VERSION 5.8 ;
BUSBITCHARS "[]" ;
DIVIDERCHAR "/" ;
UNITS
    DATABASE MICRONS 1000 ;
END UNITS

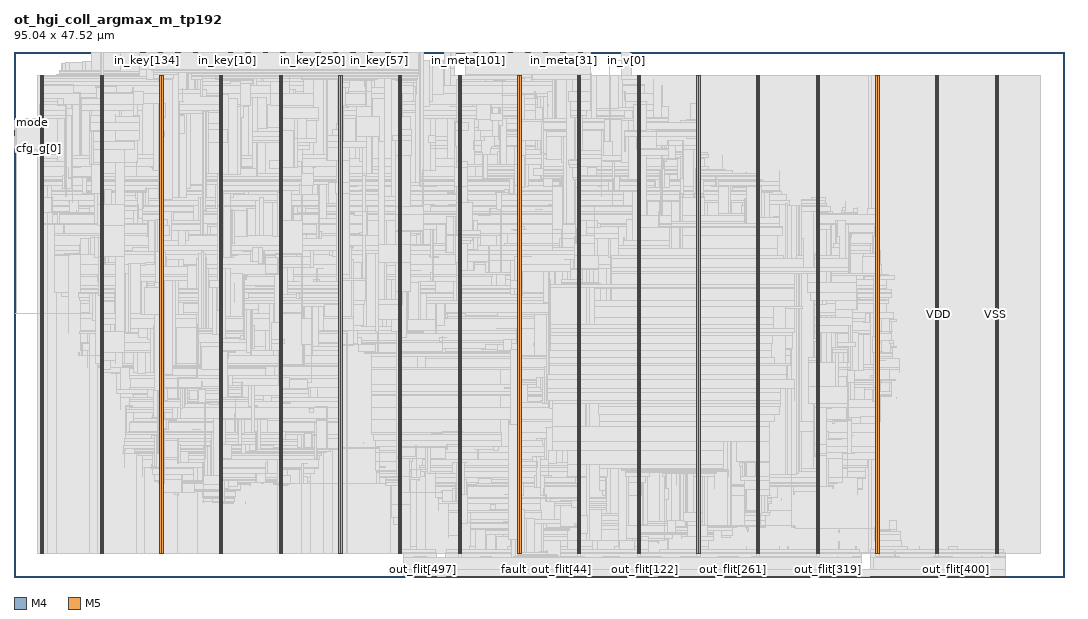
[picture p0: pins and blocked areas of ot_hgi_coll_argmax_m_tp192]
MACRO ot_hgi_coll_argmax_m_tp192
  FOREIGN ot_hgi_coll_argmax_m_tp192 0 0 ;
  CLASS BLOCK ;
  SIZE 95.04 BY 47.52 ;
  PIN cfg_g[0]
    DIRECTION INPUT ;
    USE SIGNAL ;
    PORT
      LAYER M4 ;
        RECT  0 38.736 0.084 38.76 ;
    END
  END cfg_g[0]
  PIN cfg_g[1]
    DIRECTION INPUT ;
    USE SIGNAL ;
    PORT
      LAYER M4 ;
        RECT  0 38.832 0.084 38.856 ;
    END
  END cfg_g[1]
  PIN cfg_g[2]
    DIRECTION INPUT ;
    USE SIGNAL ;
    PORT
      LAYER M4 ;
        RECT  0 38.928 0.084 38.952 ;
    END
  END cfg_g[2]
  PIN cfg_g[3]
    DIRECTION INPUT ;
    USE SIGNAL ;
    PORT
      LAYER M4 ;
        RECT  0 39.024 0.084 39.048 ;
    END
  END cfg_g[3]
  PIN cfg_g[4]
    DIRECTION INPUT ;
    USE SIGNAL ;
    PORT
      LAYER M4 ;
        RECT  0 39.12 0.084 39.144 ;
    END
  END cfg_g[4]
  PIN cfg_g[5]
    DIRECTION INPUT ;
    USE SIGNAL ;
    PORT
      LAYER M4 ;
        RECT  0 39.216 0.084 39.24 ;
    END
  END cfg_g[5]
  PIN cfg_g[6]
    DIRECTION INPUT ;
    USE SIGNAL ;
    PORT
      LAYER M4 ;
        RECT  0 39.312 0.084 39.336 ;
    END
  END cfg_g[6]
  PIN cfg_g[7]
    DIRECTION INPUT ;
    USE SIGNAL ;
    PORT
      LAYER M4 ;
        RECT  0 39.408 0.084 39.432 ;
    END
  END cfg_g[7]
  PIN cfg_gbase[0]
    DIRECTION INPUT ;
    USE SIGNAL ;
    PORT
      LAYER M4 ;
        RECT  0 39.504 0.084 39.528 ;
    END
  END cfg_gbase[0]
  PIN cfg_gbase[1]
    DIRECTION INPUT ;
    USE SIGNAL ;
    PORT
      LAYER M4 ;
        RECT  0 39.6 0.084 39.624 ;
    END
  END cfg_gbase[1]
  PIN cfg_gbase[2]
    DIRECTION INPUT ;
    USE SIGNAL ;
    PORT
      LAYER M4 ;
        RECT  0 39.696 0.084 39.72 ;
    END
  END cfg_gbase[2]
  PIN cfg_gbase[3]
    DIRECTION INPUT ;
    USE SIGNAL ;
    PORT
      LAYER M4 ;
        RECT  0 39.792 0.084 39.816 ;
    END
  END cfg_gbase[3]
  PIN cfg_gbase[4]
    DIRECTION INPUT ;
    USE SIGNAL ;
    PORT
      LAYER M4 ;
        RECT  0 39.888 0.084 39.912 ;
    END
  END cfg_gbase[4]
  PIN cfg_gbase[5]
    DIRECTION INPUT ;
    USE SIGNAL ;
    PORT
      LAYER M4 ;
        RECT  0 39.984 0.084 40.008 ;
    END
  END cfg_gbase[5]
  PIN cfg_gbase[6]
    DIRECTION INPUT ;
    USE SIGNAL ;
    PORT
      LAYER M4 ;
        RECT  0 40.08 0.084 40.104 ;
    END
  END cfg_gbase[6]
  PIN cfg_gbase[7]
    DIRECTION INPUT ;
    USE SIGNAL ;
    PORT
      LAYER M4 ;
        RECT  0 40.176 0.084 40.2 ;
    END
  END cfg_gbase[7]
  PIN cfg_rank[0]
    DIRECTION INPUT ;
    USE SIGNAL ;
    PORT
      LAYER M4 ;
        RECT  0 40.272 0.084 40.296 ;
    END
  END cfg_rank[0]
  PIN cfg_rank[1]
    DIRECTION INPUT ;
    USE SIGNAL ;
    PORT
      LAYER M4 ;
        RECT  0 40.368 0.084 40.392 ;
    END
  END cfg_rank[1]
  PIN cfg_rank[2]
    DIRECTION INPUT ;
    USE SIGNAL ;
    PORT
      LAYER M4 ;
        RECT  0 40.464 0.084 40.488 ;
    END
  END cfg_rank[2]
  PIN cfg_rank[3]
    DIRECTION INPUT ;
    USE SIGNAL ;
    PORT
      LAYER M4 ;
        RECT  0 40.56 0.084 40.584 ;
    END
  END cfg_rank[3]
  PIN cfg_rank[4]
    DIRECTION INPUT ;
    USE SIGNAL ;
    PORT
      LAYER M4 ;
        RECT  0 40.656 0.084 40.68 ;
    END
  END cfg_rank[4]
  PIN cfg_rank[5]
    DIRECTION INPUT ;
    USE SIGNAL ;
    PORT
      LAYER M4 ;
        RECT  0 40.752 0.084 40.776 ;
    END
  END cfg_rank[5]
  PIN cfg_rank[6]
    DIRECTION INPUT ;
    USE SIGNAL ;
    PORT
      LAYER M4 ;
        RECT  0 40.848 0.084 40.872 ;
    END
  END cfg_rank[6]
  PIN cfg_rank[7]
    DIRECTION INPUT ;
    USE SIGNAL ;
    PORT
      LAYER M4 ;
        RECT  0 40.944 0.084 40.968 ;
    END
  END cfg_rank[7]
  PIN clk
    DIRECTION INPUT ;
    USE SIGNAL ;
    PORT
      LAYER M4 ;
        RECT  0 41.04 0.084 41.064 ;
    END
  END clk
  PIN fault
    DIRECTION OUTPUT ;
    USE SIGNAL ;
    PORT
      LAYER M5 ;
        RECT  45.264 0 45.288 0.084 ;
    END
  END fault
  PIN flush_slot
    DIRECTION INPUT ;
    USE SIGNAL ;
    PORT
      LAYER M5 ;
        RECT  18.288 47.436 18.312 47.52 ;
    END
  END flush_slot
  PIN in_key[0]
    DIRECTION INPUT ;
    USE SIGNAL ;
    PORT
      LAYER M5 ;
        RECT  18.384 47.436 18.408 47.52 ;
    END
  END in_key[0]
  PIN in_key[100]
    DIRECTION INPUT ;
    USE SIGNAL ;
    PORT
      LAYER M5 ;
        RECT  34.128 47.436 34.152 47.52 ;
    END
  END in_key[100]
  PIN in_key[101]
    DIRECTION INPUT ;
    USE SIGNAL ;
    PORT
      LAYER M5 ;
        RECT  34.224 47.436 34.248 47.52 ;
    END
  END in_key[101]
  PIN in_key[102]
    DIRECTION INPUT ;
    USE SIGNAL ;
    PORT
      LAYER M5 ;
        RECT  34.32 47.436 34.344 47.52 ;
    END
  END in_key[102]
  PIN in_key[103]
    DIRECTION INPUT ;
    USE SIGNAL ;
    PORT
      LAYER M5 ;
        RECT  34.416 47.436 34.44 47.52 ;
    END
  END in_key[103]
  PIN in_key[104]
    DIRECTION INPUT ;
    USE SIGNAL ;
    PORT
      LAYER M5 ;
        RECT  34.512 47.436 34.536 47.52 ;
    END
  END in_key[104]
  PIN in_key[105]
    DIRECTION INPUT ;
    USE SIGNAL ;
    PORT
      LAYER M5 ;
        RECT  34.608 47.436 34.632 47.52 ;
    END
  END in_key[105]
  PIN in_key[106]
    DIRECTION INPUT ;
    USE SIGNAL ;
    PORT
      LAYER M5 ;
        RECT  34.704 47.436 34.728 47.52 ;
    END
  END in_key[106]
  PIN in_key[107]
    DIRECTION INPUT ;
    USE SIGNAL ;
    PORT
      LAYER M5 ;
        RECT  34.8 47.436 34.824 47.52 ;
    END
  END in_key[107]
  PIN in_key[108]
    DIRECTION INPUT ;
    USE SIGNAL ;
    PORT
      LAYER M5 ;
        RECT  34.896 47.436 34.92 47.52 ;
    END
  END in_key[108]
  PIN in_key[109]
    DIRECTION INPUT ;
    USE SIGNAL ;
    PORT
      LAYER M5 ;
        RECT  34.992 47.436 35.016 47.52 ;
    END
  END in_key[109]
  PIN in_key[10]
    DIRECTION INPUT ;
    USE SIGNAL ;
    PORT
      LAYER M5 ;
        RECT  19.344 47.436 19.368 47.52 ;
    END
  END in_key[10]
  PIN in_key[110]
    DIRECTION INPUT ;
    USE SIGNAL ;
    PORT
      LAYER M5 ;
        RECT  35.088 47.436 35.112 47.52 ;
    END
  END in_key[110]
  PIN in_key[111]
    DIRECTION INPUT ;
    USE SIGNAL ;
    PORT
      LAYER M5 ;
        RECT  35.184 47.436 35.208 47.52 ;
    END
  END in_key[111]
  PIN in_key[112]
    DIRECTION INPUT ;
    USE SIGNAL ;
    PORT
      LAYER M5 ;
        RECT  35.28 47.436 35.304 47.52 ;
    END
  END in_key[112]
  PIN in_key[113]
    DIRECTION INPUT ;
    USE SIGNAL ;
    PORT
      LAYER M5 ;
        RECT  35.376 47.436 35.4 47.52 ;
    END
  END in_key[113]
  PIN in_key[114]
    DIRECTION INPUT ;
    USE SIGNAL ;
    PORT
      LAYER M5 ;
        RECT  35.472 47.436 35.496 47.52 ;
    END
  END in_key[114]
  PIN in_key[115]
    DIRECTION INPUT ;
    USE SIGNAL ;
    PORT
      LAYER M5 ;
        RECT  35.568 47.436 35.592 47.52 ;
    END
  END in_key[115]
  PIN in_key[116]
    DIRECTION INPUT ;
    USE SIGNAL ;
    PORT
      LAYER M5 ;
        RECT  35.664 47.436 35.688 47.52 ;
    END
  END in_key[116]
  PIN in_key[117]
    DIRECTION INPUT ;
    USE SIGNAL ;
    PORT
      LAYER M5 ;
        RECT  35.76 47.436 35.784 47.52 ;
    END
  END in_key[117]
  PIN in_key[118]
    DIRECTION INPUT ;
    USE SIGNAL ;
    PORT
      LAYER M5 ;
        RECT  35.856 47.436 35.88 47.52 ;
    END
  END in_key[118]
  PIN in_key[119]
    DIRECTION INPUT ;
    USE SIGNAL ;
    PORT
      LAYER M5 ;
        RECT  35.952 47.436 35.976 47.52 ;
    END
  END in_key[119]
  PIN in_key[11]
    DIRECTION INPUT ;
    USE SIGNAL ;
    PORT
      LAYER M5 ;
        RECT  19.44 47.436 19.464 47.52 ;
    END
  END in_key[11]
  PIN in_key[120]
    DIRECTION INPUT ;
    USE SIGNAL ;
    PORT
      LAYER M5 ;
        RECT  36.048 47.436 36.072 47.52 ;
    END
  END in_key[120]
  PIN in_key[121]
    DIRECTION INPUT ;
    USE SIGNAL ;
    PORT
      LAYER M5 ;
        RECT  36.144 47.436 36.168 47.52 ;
    END
  END in_key[121]
  PIN in_key[122]
    DIRECTION INPUT ;
    USE SIGNAL ;
    PORT
      LAYER M5 ;
        RECT  36.24 47.436 36.264 47.52 ;
    END
  END in_key[122]
  PIN in_key[123]
    DIRECTION INPUT ;
    USE SIGNAL ;
    PORT
      LAYER M5 ;
        RECT  36.336 47.436 36.36 47.52 ;
    END
  END in_key[123]
  PIN in_key[124]
    DIRECTION INPUT ;
    USE SIGNAL ;
    PORT
      LAYER M5 ;
        RECT  36.432 47.436 36.456 47.52 ;
    END
  END in_key[124]
  PIN in_key[125]
    DIRECTION INPUT ;
    USE SIGNAL ;
    PORT
      LAYER M5 ;
        RECT  36.528 47.436 36.552 47.52 ;
    END
  END in_key[125]
  PIN in_key[126]
    DIRECTION INPUT ;
    USE SIGNAL ;
    PORT
      LAYER M5 ;
        RECT  36.624 47.436 36.648 47.52 ;
    END
  END in_key[126]
  PIN in_key[127]
    DIRECTION INPUT ;
    USE SIGNAL ;
    PORT
      LAYER M5 ;
        RECT  11.376 47.436 11.4 47.52 ;
    END
  END in_key[127]
  PIN in_key[128]
    DIRECTION INPUT ;
    USE SIGNAL ;
    PORT
      LAYER M5 ;
        RECT  11.472 47.436 11.496 47.52 ;
    END
  END in_key[128]
  PIN in_key[129]
    DIRECTION INPUT ;
    USE SIGNAL ;
    PORT
      LAYER M5 ;
        RECT  11.568 47.436 11.592 47.52 ;
    END
  END in_key[129]
  PIN in_key[12]
    DIRECTION INPUT ;
    USE SIGNAL ;
    PORT
      LAYER M5 ;
        RECT  19.536 47.436 19.56 47.52 ;
    END
  END in_key[12]
  PIN in_key[130]
    DIRECTION INPUT ;
    USE SIGNAL ;
    PORT
      LAYER M5 ;
        RECT  11.664 47.436 11.688 47.52 ;
    END
  END in_key[130]
  PIN in_key[131]
    DIRECTION INPUT ;
    USE SIGNAL ;
    PORT
      LAYER M5 ;
        RECT  11.76 47.436 11.784 47.52 ;
    END
  END in_key[131]
  PIN in_key[132]
    DIRECTION INPUT ;
    USE SIGNAL ;
    PORT
      LAYER M5 ;
        RECT  11.856 47.436 11.88 47.52 ;
    END
  END in_key[132]
  PIN in_key[133]
    DIRECTION INPUT ;
    USE SIGNAL ;
    PORT
      LAYER M5 ;
        RECT  11.952 47.436 11.976 47.52 ;
    END
  END in_key[133]
  PIN in_key[134]
    DIRECTION INPUT ;
    USE SIGNAL ;
    PORT
      LAYER M5 ;
        RECT  12.048 47.436 12.072 47.52 ;
    END
  END in_key[134]
  PIN in_key[135]
    DIRECTION INPUT ;
    USE SIGNAL ;
    PORT
      LAYER M5 ;
        RECT  12.144 47.436 12.168 47.52 ;
    END
  END in_key[135]
  PIN in_key[136]
    DIRECTION INPUT ;
    USE SIGNAL ;
    PORT
      LAYER M5 ;
        RECT  12.24 47.436 12.264 47.52 ;
    END
  END in_key[136]
  PIN in_key[137]
    DIRECTION INPUT ;
    USE SIGNAL ;
    PORT
      LAYER M5 ;
        RECT  12.336 47.436 12.36 47.52 ;
    END
  END in_key[137]
  PIN in_key[138]
    DIRECTION INPUT ;
    USE SIGNAL ;
    PORT
      LAYER M5 ;
        RECT  12.432 47.436 12.456 47.52 ;
    END
  END in_key[138]
  PIN in_key[139]
    DIRECTION INPUT ;
    USE SIGNAL ;
    PORT
      LAYER M5 ;
        RECT  12.528 47.436 12.552 47.52 ;
    END
  END in_key[139]
  PIN in_key[13]
    DIRECTION INPUT ;
    USE SIGNAL ;
    PORT
      LAYER M5 ;
        RECT  19.632 47.436 19.656 47.52 ;
    END
  END in_key[13]
  PIN in_key[140]
    DIRECTION INPUT ;
    USE SIGNAL ;
    PORT
      LAYER M5 ;
        RECT  12.624 47.436 12.648 47.52 ;
    END
  END in_key[140]
  PIN in_key[141]
    DIRECTION INPUT ;
    USE SIGNAL ;
    PORT
      LAYER M5 ;
        RECT  12.72 47.436 12.744 47.52 ;
    END
  END in_key[141]
  PIN in_key[142]
    DIRECTION INPUT ;
    USE SIGNAL ;
    PORT
      LAYER M5 ;
        RECT  12.816 47.436 12.84 47.52 ;
    END
  END in_key[142]
  PIN in_key[143]
    DIRECTION INPUT ;
    USE SIGNAL ;
    PORT
      LAYER M5 ;
        RECT  12.912 47.436 12.936 47.52 ;
    END
  END in_key[143]
  PIN in_key[144]
    DIRECTION INPUT ;
    USE SIGNAL ;
    PORT
      LAYER M5 ;
        RECT  13.008 47.436 13.032 47.52 ;
    END
  END in_key[144]
  PIN in_key[145]
    DIRECTION INPUT ;
    USE SIGNAL ;
    PORT
      LAYER M5 ;
        RECT  13.104 47.436 13.128 47.52 ;
    END
  END in_key[145]
  PIN in_key[146]
    DIRECTION INPUT ;
    USE SIGNAL ;
    PORT
      LAYER M5 ;
        RECT  13.2 47.436 13.224 47.52 ;
    END
  END in_key[146]
  PIN in_key[147]
    DIRECTION INPUT ;
    USE SIGNAL ;
    PORT
      LAYER M5 ;
        RECT  13.296 47.436 13.32 47.52 ;
    END
  END in_key[147]
  PIN in_key[148]
    DIRECTION INPUT ;
    USE SIGNAL ;
    PORT
      LAYER M5 ;
        RECT  13.392 47.436 13.416 47.52 ;
    END
  END in_key[148]
  PIN in_key[149]
    DIRECTION INPUT ;
    USE SIGNAL ;
    PORT
      LAYER M5 ;
        RECT  13.488 47.436 13.512 47.52 ;
    END
  END in_key[149]
  PIN in_key[14]
    DIRECTION INPUT ;
    USE SIGNAL ;
    PORT
      LAYER M5 ;
        RECT  19.728 47.436 19.752 47.52 ;
    END
  END in_key[14]
  PIN in_key[150]
    DIRECTION INPUT ;
    USE SIGNAL ;
    PORT
      LAYER M5 ;
        RECT  13.584 47.436 13.608 47.52 ;
    END
  END in_key[150]
  PIN in_key[151]
    DIRECTION INPUT ;
    USE SIGNAL ;
    PORT
      LAYER M5 ;
        RECT  13.68 47.436 13.704 47.52 ;
    END
  END in_key[151]
  PIN in_key[152]
    DIRECTION INPUT ;
    USE SIGNAL ;
    PORT
      LAYER M5 ;
        RECT  13.776 47.436 13.8 47.52 ;
    END
  END in_key[152]
  PIN in_key[153]
    DIRECTION INPUT ;
    USE SIGNAL ;
    PORT
      LAYER M5 ;
        RECT  13.872 47.436 13.896 47.52 ;
    END
  END in_key[153]
  PIN in_key[154]
    DIRECTION INPUT ;
    USE SIGNAL ;
    PORT
      LAYER M5 ;
        RECT  13.968 47.436 13.992 47.52 ;
    END
  END in_key[154]
  PIN in_key[155]
    DIRECTION INPUT ;
    USE SIGNAL ;
    PORT
      LAYER M5 ;
        RECT  14.064 47.436 14.088 47.52 ;
    END
  END in_key[155]
  PIN in_key[156]
    DIRECTION INPUT ;
    USE SIGNAL ;
    PORT
      LAYER M5 ;
        RECT  14.16 47.436 14.184 47.52 ;
    END
  END in_key[156]
  PIN in_key[157]
    DIRECTION INPUT ;
    USE SIGNAL ;
    PORT
      LAYER M5 ;
        RECT  14.256 47.436 14.28 47.52 ;
    END
  END in_key[157]
  PIN in_key[158]
    DIRECTION INPUT ;
    USE SIGNAL ;
    PORT
      LAYER M5 ;
        RECT  14.352 47.436 14.376 47.52 ;
    END
  END in_key[158]
  PIN in_key[159]
    DIRECTION INPUT ;
    USE SIGNAL ;
    PORT
      LAYER M5 ;
        RECT  27.504 47.436 27.528 47.52 ;
    END
  END in_key[159]
  PIN in_key[15]
    DIRECTION INPUT ;
    USE SIGNAL ;
    PORT
      LAYER M5 ;
        RECT  19.824 47.436 19.848 47.52 ;
    END
  END in_key[15]
  PIN in_key[160]
    DIRECTION INPUT ;
    USE SIGNAL ;
    PORT
      LAYER M5 ;
        RECT  27.6 47.436 27.624 47.52 ;
    END
  END in_key[160]
  PIN in_key[161]
    DIRECTION INPUT ;
    USE SIGNAL ;
    PORT
      LAYER M5 ;
        RECT  27.696 47.436 27.72 47.52 ;
    END
  END in_key[161]
  PIN in_key[162]
    DIRECTION INPUT ;
    USE SIGNAL ;
    PORT
      LAYER M5 ;
        RECT  27.792 47.436 27.816 47.52 ;
    END
  END in_key[162]
  PIN in_key[163]
    DIRECTION INPUT ;
    USE SIGNAL ;
    PORT
      LAYER M5 ;
        RECT  27.888 47.436 27.912 47.52 ;
    END
  END in_key[163]
  PIN in_key[164]
    DIRECTION INPUT ;
    USE SIGNAL ;
    PORT
      LAYER M5 ;
        RECT  27.984 47.436 28.008 47.52 ;
    END
  END in_key[164]
  PIN in_key[165]
    DIRECTION INPUT ;
    USE SIGNAL ;
    PORT
      LAYER M5 ;
        RECT  28.08 47.436 28.104 47.52 ;
    END
  END in_key[165]
  PIN in_key[166]
    DIRECTION INPUT ;
    USE SIGNAL ;
    PORT
      LAYER M5 ;
        RECT  28.176 47.436 28.2 47.52 ;
    END
  END in_key[166]
  PIN in_key[167]
    DIRECTION INPUT ;
    USE SIGNAL ;
    PORT
      LAYER M5 ;
        RECT  28.272 47.436 28.296 47.52 ;
    END
  END in_key[167]
  PIN in_key[168]
    DIRECTION INPUT ;
    USE SIGNAL ;
    PORT
      LAYER M5 ;
        RECT  28.368 47.436 28.392 47.52 ;
    END
  END in_key[168]
  PIN in_key[169]
    DIRECTION INPUT ;
    USE SIGNAL ;
    PORT
      LAYER M5 ;
        RECT  28.464 47.436 28.488 47.52 ;
    END
  END in_key[169]
  PIN in_key[16]
    DIRECTION INPUT ;
    USE SIGNAL ;
    PORT
      LAYER M5 ;
        RECT  19.92 47.436 19.944 47.52 ;
    END
  END in_key[16]
  PIN in_key[170]
    DIRECTION INPUT ;
    USE SIGNAL ;
    PORT
      LAYER M5 ;
        RECT  28.56 47.436 28.584 47.52 ;
    END
  END in_key[170]
  PIN in_key[171]
    DIRECTION INPUT ;
    USE SIGNAL ;
    PORT
      LAYER M5 ;
        RECT  28.656 47.436 28.68 47.52 ;
    END
  END in_key[171]
  PIN in_key[172]
    DIRECTION INPUT ;
    USE SIGNAL ;
    PORT
      LAYER M5 ;
        RECT  28.752 47.436 28.776 47.52 ;
    END
  END in_key[172]
  PIN in_key[173]
    DIRECTION INPUT ;
    USE SIGNAL ;
    PORT
      LAYER M5 ;
        RECT  28.848 47.436 28.872 47.52 ;
    END
  END in_key[173]
  PIN in_key[174]
    DIRECTION INPUT ;
    USE SIGNAL ;
    PORT
      LAYER M5 ;
        RECT  28.944 47.436 28.968 47.52 ;
    END
  END in_key[174]
  PIN in_key[175]
    DIRECTION INPUT ;
    USE SIGNAL ;
    PORT
      LAYER M5 ;
        RECT  29.04 47.436 29.064 47.52 ;
    END
  END in_key[175]
  PIN in_key[176]
    DIRECTION INPUT ;
    USE SIGNAL ;
    PORT
      LAYER M5 ;
        RECT  29.136 47.436 29.16 47.52 ;
    END
  END in_key[176]
  PIN in_key[177]
    DIRECTION INPUT ;
    USE SIGNAL ;
    PORT
      LAYER M5 ;
        RECT  29.232 47.436 29.256 47.52 ;
    END
  END in_key[177]
  PIN in_key[178]
    DIRECTION INPUT ;
    USE SIGNAL ;
    PORT
      LAYER M5 ;
        RECT  29.328 47.436 29.352 47.52 ;
    END
  END in_key[178]
  PIN in_key[179]
    DIRECTION INPUT ;
    USE SIGNAL ;
    PORT
      LAYER M5 ;
        RECT  29.424 47.436 29.448 47.52 ;
    END
  END in_key[179]
  PIN in_key[17]
    DIRECTION INPUT ;
    USE SIGNAL ;
    PORT
      LAYER M5 ;
        RECT  20.016 47.436 20.04 47.52 ;
    END
  END in_key[17]
  PIN in_key[180]
    DIRECTION INPUT ;
    USE SIGNAL ;
    PORT
      LAYER M5 ;
        RECT  29.52 47.436 29.544 47.52 ;
    END
  END in_key[180]
  PIN in_key[181]
    DIRECTION INPUT ;
    USE SIGNAL ;
    PORT
      LAYER M5 ;
        RECT  29.616 47.436 29.64 47.52 ;
    END
  END in_key[181]
  PIN in_key[182]
    DIRECTION INPUT ;
    USE SIGNAL ;
    PORT
      LAYER M5 ;
        RECT  29.712 47.436 29.736 47.52 ;
    END
  END in_key[182]
  PIN in_key[183]
    DIRECTION INPUT ;
    USE SIGNAL ;
    PORT
      LAYER M5 ;
        RECT  29.808 47.436 29.832 47.52 ;
    END
  END in_key[183]
  PIN in_key[184]
    DIRECTION INPUT ;
    USE SIGNAL ;
    PORT
      LAYER M5 ;
        RECT  29.904 47.436 29.928 47.52 ;
    END
  END in_key[184]
  PIN in_key[185]
    DIRECTION INPUT ;
    USE SIGNAL ;
    PORT
      LAYER M5 ;
        RECT  30 47.436 30.024 47.52 ;
    END
  END in_key[185]
  PIN in_key[186]
    DIRECTION INPUT ;
    USE SIGNAL ;
    PORT
      LAYER M5 ;
        RECT  30.096 47.436 30.12 47.52 ;
    END
  END in_key[186]
  PIN in_key[187]
    DIRECTION INPUT ;
    USE SIGNAL ;
    PORT
      LAYER M5 ;
        RECT  30.192 47.436 30.216 47.52 ;
    END
  END in_key[187]
  PIN in_key[188]
    DIRECTION INPUT ;
    USE SIGNAL ;
    PORT
      LAYER M5 ;
        RECT  30.288 47.436 30.312 47.52 ;
    END
  END in_key[188]
  PIN in_key[189]
    DIRECTION INPUT ;
    USE SIGNAL ;
    PORT
      LAYER M5 ;
        RECT  30.384 47.436 30.408 47.52 ;
    END
  END in_key[189]
  PIN in_key[18]
    DIRECTION INPUT ;
    USE SIGNAL ;
    PORT
      LAYER M5 ;
        RECT  20.112 47.436 20.136 47.52 ;
    END
  END in_key[18]
  PIN in_key[190]
    DIRECTION INPUT ;
    USE SIGNAL ;
    PORT
      LAYER M5 ;
        RECT  30.48 47.436 30.504 47.52 ;
    END
  END in_key[190]
  PIN in_key[191]
    DIRECTION INPUT ;
    USE SIGNAL ;
    PORT
      LAYER M5 ;
        RECT  14.448 47.436 14.472 47.52 ;
    END
  END in_key[191]
  PIN in_key[192]
    DIRECTION INPUT ;
    USE SIGNAL ;
    PORT
      LAYER M5 ;
        RECT  14.544 47.436 14.568 47.52 ;
    END
  END in_key[192]
  PIN in_key[193]
    DIRECTION INPUT ;
    USE SIGNAL ;
    PORT
      LAYER M5 ;
        RECT  14.64 47.436 14.664 47.52 ;
    END
  END in_key[193]
  PIN in_key[194]
    DIRECTION INPUT ;
    USE SIGNAL ;
    PORT
      LAYER M5 ;
        RECT  14.736 47.436 14.76 47.52 ;
    END
  END in_key[194]
  PIN in_key[195]
    DIRECTION INPUT ;
    USE SIGNAL ;
    PORT
      LAYER M5 ;
        RECT  14.832 47.436 14.856 47.52 ;
    END
  END in_key[195]
  PIN in_key[196]
    DIRECTION INPUT ;
    USE SIGNAL ;
    PORT
      LAYER M5 ;
        RECT  14.928 47.436 14.952 47.52 ;
    END
  END in_key[196]
  PIN in_key[197]
    DIRECTION INPUT ;
    USE SIGNAL ;
    PORT
      LAYER M5 ;
        RECT  15.024 47.436 15.048 47.52 ;
    END
  END in_key[197]
  PIN in_key[198]
    DIRECTION INPUT ;
    USE SIGNAL ;
    PORT
      LAYER M5 ;
        RECT  15.12 47.436 15.144 47.52 ;
    END
  END in_key[198]
  PIN in_key[199]
    DIRECTION INPUT ;
    USE SIGNAL ;
    PORT
      LAYER M5 ;
        RECT  15.216 47.436 15.24 47.52 ;
    END
  END in_key[199]
  PIN in_key[19]
    DIRECTION INPUT ;
    USE SIGNAL ;
    PORT
      LAYER M5 ;
        RECT  20.208 47.436 20.232 47.52 ;
    END
  END in_key[19]
  PIN in_key[1]
    DIRECTION INPUT ;
    USE SIGNAL ;
    PORT
      LAYER M5 ;
        RECT  18.48 47.436 18.504 47.52 ;
    END
  END in_key[1]
  PIN in_key[200]
    DIRECTION INPUT ;
    USE SIGNAL ;
    PORT
      LAYER M5 ;
        RECT  15.312 47.436 15.336 47.52 ;
    END
  END in_key[200]
  PIN in_key[201]
    DIRECTION INPUT ;
    USE SIGNAL ;
    PORT
      LAYER M5 ;
        RECT  15.408 47.436 15.432 47.52 ;
    END
  END in_key[201]
  PIN in_key[202]
    DIRECTION INPUT ;
    USE SIGNAL ;
    PORT
      LAYER M5 ;
        RECT  15.504 47.436 15.528 47.52 ;
    END
  END in_key[202]
  PIN in_key[203]
    DIRECTION INPUT ;
    USE SIGNAL ;
    PORT
      LAYER M5 ;
        RECT  15.6 47.436 15.624 47.52 ;
    END
  END in_key[203]
  PIN in_key[204]
    DIRECTION INPUT ;
    USE SIGNAL ;
    PORT
      LAYER M5 ;
        RECT  15.696 47.436 15.72 47.52 ;
    END
  END in_key[204]
  PIN in_key[205]
    DIRECTION INPUT ;
    USE SIGNAL ;
    PORT
      LAYER M5 ;
        RECT  15.792 47.436 15.816 47.52 ;
    END
  END in_key[205]
  PIN in_key[206]
    DIRECTION INPUT ;
    USE SIGNAL ;
    PORT
      LAYER M5 ;
        RECT  15.888 47.436 15.912 47.52 ;
    END
  END in_key[206]
  PIN in_key[207]
    DIRECTION INPUT ;
    USE SIGNAL ;
    PORT
      LAYER M5 ;
        RECT  15.984 47.436 16.008 47.52 ;
    END
  END in_key[207]
  PIN in_key[208]
    DIRECTION INPUT ;
    USE SIGNAL ;
    PORT
      LAYER M5 ;
        RECT  16.08 47.436 16.104 47.52 ;
    END
  END in_key[208]
  PIN in_key[209]
    DIRECTION INPUT ;
    USE SIGNAL ;
    PORT
      LAYER M5 ;
        RECT  16.176 47.436 16.2 47.52 ;
    END
  END in_key[209]
  PIN in_key[20]
    DIRECTION INPUT ;
    USE SIGNAL ;
    PORT
      LAYER M5 ;
        RECT  20.304 47.436 20.328 47.52 ;
    END
  END in_key[20]
  PIN in_key[210]
    DIRECTION INPUT ;
    USE SIGNAL ;
    PORT
      LAYER M5 ;
        RECT  16.272 47.436 16.296 47.52 ;
    END
  END in_key[210]
  PIN in_key[211]
    DIRECTION INPUT ;
    USE SIGNAL ;
    PORT
      LAYER M5 ;
        RECT  16.368 47.436 16.392 47.52 ;
    END
  END in_key[211]
  PIN in_key[212]
    DIRECTION INPUT ;
    USE SIGNAL ;
    PORT
      LAYER M5 ;
        RECT  16.464 47.436 16.488 47.52 ;
    END
  END in_key[212]
  PIN in_key[213]
    DIRECTION INPUT ;
    USE SIGNAL ;
    PORT
      LAYER M5 ;
        RECT  16.56 47.436 16.584 47.52 ;
    END
  END in_key[213]
  PIN in_key[214]
    DIRECTION INPUT ;
    USE SIGNAL ;
    PORT
      LAYER M5 ;
        RECT  16.656 47.436 16.68 47.52 ;
    END
  END in_key[214]
  PIN in_key[215]
    DIRECTION INPUT ;
    USE SIGNAL ;
    PORT
      LAYER M5 ;
        RECT  16.752 47.436 16.776 47.52 ;
    END
  END in_key[215]
  PIN in_key[216]
    DIRECTION INPUT ;
    USE SIGNAL ;
    PORT
      LAYER M5 ;
        RECT  16.848 47.436 16.872 47.52 ;
    END
  END in_key[216]
  PIN in_key[217]
    DIRECTION INPUT ;
    USE SIGNAL ;
    PORT
      LAYER M5 ;
        RECT  16.944 47.436 16.968 47.52 ;
    END
  END in_key[217]
  PIN in_key[218]
    DIRECTION INPUT ;
    USE SIGNAL ;
    PORT
      LAYER M5 ;
        RECT  17.04 47.436 17.064 47.52 ;
    END
  END in_key[218]
  PIN in_key[219]
    DIRECTION INPUT ;
    USE SIGNAL ;
    PORT
      LAYER M5 ;
        RECT  17.136 47.436 17.16 47.52 ;
    END
  END in_key[219]
  PIN in_key[21]
    DIRECTION INPUT ;
    USE SIGNAL ;
    PORT
      LAYER M5 ;
        RECT  20.4 47.436 20.424 47.52 ;
    END
  END in_key[21]
  PIN in_key[220]
    DIRECTION INPUT ;
    USE SIGNAL ;
    PORT
      LAYER M5 ;
        RECT  17.232 47.436 17.256 47.52 ;
    END
  END in_key[220]
  PIN in_key[221]
    DIRECTION INPUT ;
    USE SIGNAL ;
    PORT
      LAYER M5 ;
        RECT  17.328 47.436 17.352 47.52 ;
    END
  END in_key[221]
  PIN in_key[222]
    DIRECTION INPUT ;
    USE SIGNAL ;
    PORT
      LAYER M5 ;
        RECT  17.424 47.436 17.448 47.52 ;
    END
  END in_key[222]
  PIN in_key[223]
    DIRECTION INPUT ;
    USE SIGNAL ;
    PORT
      LAYER M5 ;
        RECT  24.432 47.436 24.456 47.52 ;
    END
  END in_key[223]
  PIN in_key[224]
    DIRECTION INPUT ;
    USE SIGNAL ;
    PORT
      LAYER M5 ;
        RECT  24.528 47.436 24.552 47.52 ;
    END
  END in_key[224]
  PIN in_key[225]
    DIRECTION INPUT ;
    USE SIGNAL ;
    PORT
      LAYER M5 ;
        RECT  24.624 47.436 24.648 47.52 ;
    END
  END in_key[225]
  PIN in_key[226]
    DIRECTION INPUT ;
    USE SIGNAL ;
    PORT
      LAYER M5 ;
        RECT  24.72 47.436 24.744 47.52 ;
    END
  END in_key[226]
  PIN in_key[227]
    DIRECTION INPUT ;
    USE SIGNAL ;
    PORT
      LAYER M5 ;
        RECT  24.816 47.436 24.84 47.52 ;
    END
  END in_key[227]
  PIN in_key[228]
    DIRECTION INPUT ;
    USE SIGNAL ;
    PORT
      LAYER M5 ;
        RECT  24.912 47.436 24.936 47.52 ;
    END
  END in_key[228]
  PIN in_key[229]
    DIRECTION INPUT ;
    USE SIGNAL ;
    PORT
      LAYER M5 ;
        RECT  25.008 47.436 25.032 47.52 ;
    END
  END in_key[229]
  PIN in_key[22]
    DIRECTION INPUT ;
    USE SIGNAL ;
    PORT
      LAYER M5 ;
        RECT  20.496 47.436 20.52 47.52 ;
    END
  END in_key[22]
  PIN in_key[230]
    DIRECTION INPUT ;
    USE SIGNAL ;
    PORT
      LAYER M5 ;
        RECT  25.104 47.436 25.128 47.52 ;
    END
  END in_key[230]
  PIN in_key[231]
    DIRECTION INPUT ;
    USE SIGNAL ;
    PORT
      LAYER M5 ;
        RECT  25.2 47.436 25.224 47.52 ;
    END
  END in_key[231]
  PIN in_key[232]
    DIRECTION INPUT ;
    USE SIGNAL ;
    PORT
      LAYER M5 ;
        RECT  25.296 47.436 25.32 47.52 ;
    END
  END in_key[232]
  PIN in_key[233]
    DIRECTION INPUT ;
    USE SIGNAL ;
    PORT
      LAYER M5 ;
        RECT  25.392 47.436 25.416 47.52 ;
    END
  END in_key[233]
  PIN in_key[234]
    DIRECTION INPUT ;
    USE SIGNAL ;
    PORT
      LAYER M5 ;
        RECT  25.488 47.436 25.512 47.52 ;
    END
  END in_key[234]
  PIN in_key[235]
    DIRECTION INPUT ;
    USE SIGNAL ;
    PORT
      LAYER M5 ;
        RECT  25.584 47.436 25.608 47.52 ;
    END
  END in_key[235]
  PIN in_key[236]
    DIRECTION INPUT ;
    USE SIGNAL ;
    PORT
      LAYER M5 ;
        RECT  25.68 47.436 25.704 47.52 ;
    END
  END in_key[236]
  PIN in_key[237]
    DIRECTION INPUT ;
    USE SIGNAL ;
    PORT
      LAYER M5 ;
        RECT  25.776 47.436 25.8 47.52 ;
    END
  END in_key[237]
  PIN in_key[238]
    DIRECTION INPUT ;
    USE SIGNAL ;
    PORT
      LAYER M5 ;
        RECT  25.872 47.436 25.896 47.52 ;
    END
  END in_key[238]
  PIN in_key[239]
    DIRECTION INPUT ;
    USE SIGNAL ;
    PORT
      LAYER M5 ;
        RECT  25.968 47.436 25.992 47.52 ;
    END
  END in_key[239]
  PIN in_key[23]
    DIRECTION INPUT ;
    USE SIGNAL ;
    PORT
      LAYER M5 ;
        RECT  20.592 47.436 20.616 47.52 ;
    END
  END in_key[23]
  PIN in_key[240]
    DIRECTION INPUT ;
    USE SIGNAL ;
    PORT
      LAYER M5 ;
        RECT  26.064 47.436 26.088 47.52 ;
    END
  END in_key[240]
  PIN in_key[241]
    DIRECTION INPUT ;
    USE SIGNAL ;
    PORT
      LAYER M5 ;
        RECT  26.16 47.436 26.184 47.52 ;
    END
  END in_key[241]
  PIN in_key[242]
    DIRECTION INPUT ;
    USE SIGNAL ;
    PORT
      LAYER M5 ;
        RECT  26.256 47.436 26.28 47.52 ;
    END
  END in_key[242]
  PIN in_key[243]
    DIRECTION INPUT ;
    USE SIGNAL ;
    PORT
      LAYER M5 ;
        RECT  26.352 47.436 26.376 47.52 ;
    END
  END in_key[243]
  PIN in_key[244]
    DIRECTION INPUT ;
    USE SIGNAL ;
    PORT
      LAYER M5 ;
        RECT  26.448 47.436 26.472 47.52 ;
    END
  END in_key[244]
  PIN in_key[245]
    DIRECTION INPUT ;
    USE SIGNAL ;
    PORT
      LAYER M5 ;
        RECT  26.544 47.436 26.568 47.52 ;
    END
  END in_key[245]
  PIN in_key[246]
    DIRECTION INPUT ;
    USE SIGNAL ;
    PORT
      LAYER M5 ;
        RECT  26.64 47.436 26.664 47.52 ;
    END
  END in_key[246]
  PIN in_key[247]
    DIRECTION INPUT ;
    USE SIGNAL ;
    PORT
      LAYER M5 ;
        RECT  26.736 47.436 26.76 47.52 ;
    END
  END in_key[247]
  PIN in_key[248]
    DIRECTION INPUT ;
    USE SIGNAL ;
    PORT
      LAYER M5 ;
        RECT  26.832 47.436 26.856 47.52 ;
    END
  END in_key[248]
  PIN in_key[249]
    DIRECTION INPUT ;
    USE SIGNAL ;
    PORT
      LAYER M5 ;
        RECT  26.928 47.436 26.952 47.52 ;
    END
  END in_key[249]
  PIN in_key[24]
    DIRECTION INPUT ;
    USE SIGNAL ;
    PORT
      LAYER M5 ;
        RECT  20.688 47.436 20.712 47.52 ;
    END
  END in_key[24]
  PIN in_key[250]
    DIRECTION INPUT ;
    USE SIGNAL ;
    PORT
      LAYER M5 ;
        RECT  27.024 47.436 27.048 47.52 ;
    END
  END in_key[250]
  PIN in_key[251]
    DIRECTION INPUT ;
    USE SIGNAL ;
    PORT
      LAYER M5 ;
        RECT  27.12 47.436 27.144 47.52 ;
    END
  END in_key[251]
  PIN in_key[252]
    DIRECTION INPUT ;
    USE SIGNAL ;
    PORT
      LAYER M5 ;
        RECT  27.216 47.436 27.24 47.52 ;
    END
  END in_key[252]
  PIN in_key[253]
    DIRECTION INPUT ;
    USE SIGNAL ;
    PORT
      LAYER M5 ;
        RECT  27.312 47.436 27.336 47.52 ;
    END
  END in_key[253]
  PIN in_key[254]
    DIRECTION INPUT ;
    USE SIGNAL ;
    PORT
      LAYER M5 ;
        RECT  27.408 47.436 27.432 47.52 ;
    END
  END in_key[254]
  PIN in_key[255]
    DIRECTION INPUT ;
    USE SIGNAL ;
    PORT
      LAYER M5 ;
        RECT  43.632 47.436 43.656 47.52 ;
    END
  END in_key[255]
  PIN in_key[25]
    DIRECTION INPUT ;
    USE SIGNAL ;
    PORT
      LAYER M5 ;
        RECT  20.784 47.436 20.808 47.52 ;
    END
  END in_key[25]
  PIN in_key[26]
    DIRECTION INPUT ;
    USE SIGNAL ;
    PORT
      LAYER M5 ;
        RECT  20.88 47.436 20.904 47.52 ;
    END
  END in_key[26]
  PIN in_key[27]
    DIRECTION INPUT ;
    USE SIGNAL ;
    PORT
      LAYER M5 ;
        RECT  20.976 47.436 21 47.52 ;
    END
  END in_key[27]
  PIN in_key[28]
    DIRECTION INPUT ;
    USE SIGNAL ;
    PORT
      LAYER M5 ;
        RECT  21.072 47.436 21.096 47.52 ;
    END
  END in_key[28]
  PIN in_key[29]
    DIRECTION INPUT ;
    USE SIGNAL ;
    PORT
      LAYER M5 ;
        RECT  21.168 47.436 21.192 47.52 ;
    END
  END in_key[29]
  PIN in_key[2]
    DIRECTION INPUT ;
    USE SIGNAL ;
    PORT
      LAYER M5 ;
        RECT  18.576 47.436 18.6 47.52 ;
    END
  END in_key[2]
  PIN in_key[30]
    DIRECTION INPUT ;
    USE SIGNAL ;
    PORT
      LAYER M5 ;
        RECT  21.264 47.436 21.288 47.52 ;
    END
  END in_key[30]
  PIN in_key[31]
    DIRECTION INPUT ;
    USE SIGNAL ;
    PORT
      LAYER M5 ;
        RECT  30.576 47.436 30.6 47.52 ;
    END
  END in_key[31]
  PIN in_key[32]
    DIRECTION INPUT ;
    USE SIGNAL ;
    PORT
      LAYER M5 ;
        RECT  30.672 47.436 30.696 47.52 ;
    END
  END in_key[32]
  PIN in_key[33]
    DIRECTION INPUT ;
    USE SIGNAL ;
    PORT
      LAYER M5 ;
        RECT  30.768 47.436 30.792 47.52 ;
    END
  END in_key[33]
  PIN in_key[34]
    DIRECTION INPUT ;
    USE SIGNAL ;
    PORT
      LAYER M5 ;
        RECT  30.864 47.436 30.888 47.52 ;
    END
  END in_key[34]
  PIN in_key[35]
    DIRECTION INPUT ;
    USE SIGNAL ;
    PORT
      LAYER M5 ;
        RECT  30.96 47.436 30.984 47.52 ;
    END
  END in_key[35]
  PIN in_key[36]
    DIRECTION INPUT ;
    USE SIGNAL ;
    PORT
      LAYER M5 ;
        RECT  31.056 47.436 31.08 47.52 ;
    END
  END in_key[36]
  PIN in_key[37]
    DIRECTION INPUT ;
    USE SIGNAL ;
    PORT
      LAYER M5 ;
        RECT  31.152 47.436 31.176 47.52 ;
    END
  END in_key[37]
  PIN in_key[38]
    DIRECTION INPUT ;
    USE SIGNAL ;
    PORT
      LAYER M5 ;
        RECT  31.248 47.436 31.272 47.52 ;
    END
  END in_key[38]
  PIN in_key[39]
    DIRECTION INPUT ;
    USE SIGNAL ;
    PORT
      LAYER M5 ;
        RECT  31.344 47.436 31.368 47.52 ;
    END
  END in_key[39]
  PIN in_key[3]
    DIRECTION INPUT ;
    USE SIGNAL ;
    PORT
      LAYER M5 ;
        RECT  18.672 47.436 18.696 47.52 ;
    END
  END in_key[3]
  PIN in_key[40]
    DIRECTION INPUT ;
    USE SIGNAL ;
    PORT
      LAYER M5 ;
        RECT  31.44 47.436 31.464 47.52 ;
    END
  END in_key[40]
  PIN in_key[41]
    DIRECTION INPUT ;
    USE SIGNAL ;
    PORT
      LAYER M5 ;
        RECT  31.536 47.436 31.56 47.52 ;
    END
  END in_key[41]
  PIN in_key[42]
    DIRECTION INPUT ;
    USE SIGNAL ;
    PORT
      LAYER M5 ;
        RECT  31.632 47.436 31.656 47.52 ;
    END
  END in_key[42]
  PIN in_key[43]
    DIRECTION INPUT ;
    USE SIGNAL ;
    PORT
      LAYER M5 ;
        RECT  31.728 47.436 31.752 47.52 ;
    END
  END in_key[43]
  PIN in_key[44]
    DIRECTION INPUT ;
    USE SIGNAL ;
    PORT
      LAYER M5 ;
        RECT  31.824 47.436 31.848 47.52 ;
    END
  END in_key[44]
  PIN in_key[45]
    DIRECTION INPUT ;
    USE SIGNAL ;
    PORT
      LAYER M5 ;
        RECT  31.92 47.436 31.944 47.52 ;
    END
  END in_key[45]
  PIN in_key[46]
    DIRECTION INPUT ;
    USE SIGNAL ;
    PORT
      LAYER M5 ;
        RECT  32.016 47.436 32.04 47.52 ;
    END
  END in_key[46]
  PIN in_key[47]
    DIRECTION INPUT ;
    USE SIGNAL ;
    PORT
      LAYER M5 ;
        RECT  32.112 47.436 32.136 47.52 ;
    END
  END in_key[47]
  PIN in_key[48]
    DIRECTION INPUT ;
    USE SIGNAL ;
    PORT
      LAYER M5 ;
        RECT  32.208 47.436 32.232 47.52 ;
    END
  END in_key[48]
  PIN in_key[49]
    DIRECTION INPUT ;
    USE SIGNAL ;
    PORT
      LAYER M5 ;
        RECT  32.304 47.436 32.328 47.52 ;
    END
  END in_key[49]
  PIN in_key[4]
    DIRECTION INPUT ;
    USE SIGNAL ;
    PORT
      LAYER M5 ;
        RECT  18.768 47.436 18.792 47.52 ;
    END
  END in_key[4]
  PIN in_key[50]
    DIRECTION INPUT ;
    USE SIGNAL ;
    PORT
      LAYER M5 ;
        RECT  32.4 47.436 32.424 47.52 ;
    END
  END in_key[50]
  PIN in_key[51]
    DIRECTION INPUT ;
    USE SIGNAL ;
    PORT
      LAYER M5 ;
        RECT  32.496 47.436 32.52 47.52 ;
    END
  END in_key[51]
  PIN in_key[52]
    DIRECTION INPUT ;
    USE SIGNAL ;
    PORT
      LAYER M5 ;
        RECT  32.592 47.436 32.616 47.52 ;
    END
  END in_key[52]
  PIN in_key[53]
    DIRECTION INPUT ;
    USE SIGNAL ;
    PORT
      LAYER M5 ;
        RECT  32.688 47.436 32.712 47.52 ;
    END
  END in_key[53]
  PIN in_key[54]
    DIRECTION INPUT ;
    USE SIGNAL ;
    PORT
      LAYER M5 ;
        RECT  32.784 47.436 32.808 47.52 ;
    END
  END in_key[54]
  PIN in_key[55]
    DIRECTION INPUT ;
    USE SIGNAL ;
    PORT
      LAYER M5 ;
        RECT  32.88 47.436 32.904 47.52 ;
    END
  END in_key[55]
  PIN in_key[56]
    DIRECTION INPUT ;
    USE SIGNAL ;
    PORT
      LAYER M5 ;
        RECT  32.976 47.436 33 47.52 ;
    END
  END in_key[56]
  PIN in_key[57]
    DIRECTION INPUT ;
    USE SIGNAL ;
    PORT
      LAYER M5 ;
        RECT  33.072 47.436 33.096 47.52 ;
    END
  END in_key[57]
  PIN in_key[58]
    DIRECTION INPUT ;
    USE SIGNAL ;
    PORT
      LAYER M5 ;
        RECT  33.168 47.436 33.192 47.52 ;
    END
  END in_key[58]
  PIN in_key[59]
    DIRECTION INPUT ;
    USE SIGNAL ;
    PORT
      LAYER M5 ;
        RECT  33.264 47.436 33.288 47.52 ;
    END
  END in_key[59]
  PIN in_key[5]
    DIRECTION INPUT ;
    USE SIGNAL ;
    PORT
      LAYER M5 ;
        RECT  18.864 47.436 18.888 47.52 ;
    END
  END in_key[5]
  PIN in_key[60]
    DIRECTION INPUT ;
    USE SIGNAL ;
    PORT
      LAYER M5 ;
        RECT  33.36 47.436 33.384 47.52 ;
    END
  END in_key[60]
  PIN in_key[61]
    DIRECTION INPUT ;
    USE SIGNAL ;
    PORT
      LAYER M5 ;
        RECT  33.456 47.436 33.48 47.52 ;
    END
  END in_key[61]
  PIN in_key[62]
    DIRECTION INPUT ;
    USE SIGNAL ;
    PORT
      LAYER M5 ;
        RECT  33.552 47.436 33.576 47.52 ;
    END
  END in_key[62]
  PIN in_key[63]
    DIRECTION INPUT ;
    USE SIGNAL ;
    PORT
      LAYER M5 ;
        RECT  21.36 47.436 21.384 47.52 ;
    END
  END in_key[63]
  PIN in_key[64]
    DIRECTION INPUT ;
    USE SIGNAL ;
    PORT
      LAYER M5 ;
        RECT  21.456 47.436 21.48 47.52 ;
    END
  END in_key[64]
  PIN in_key[65]
    DIRECTION INPUT ;
    USE SIGNAL ;
    PORT
      LAYER M5 ;
        RECT  21.552 47.436 21.576 47.52 ;
    END
  END in_key[65]
  PIN in_key[66]
    DIRECTION INPUT ;
    USE SIGNAL ;
    PORT
      LAYER M5 ;
        RECT  21.648 47.436 21.672 47.52 ;
    END
  END in_key[66]
  PIN in_key[67]
    DIRECTION INPUT ;
    USE SIGNAL ;
    PORT
      LAYER M5 ;
        RECT  21.744 47.436 21.768 47.52 ;
    END
  END in_key[67]
  PIN in_key[68]
    DIRECTION INPUT ;
    USE SIGNAL ;
    PORT
      LAYER M5 ;
        RECT  21.84 47.436 21.864 47.52 ;
    END
  END in_key[68]
  PIN in_key[69]
    DIRECTION INPUT ;
    USE SIGNAL ;
    PORT
      LAYER M5 ;
        RECT  21.936 47.436 21.96 47.52 ;
    END
  END in_key[69]
  PIN in_key[6]
    DIRECTION INPUT ;
    USE SIGNAL ;
    PORT
      LAYER M5 ;
        RECT  18.96 47.436 18.984 47.52 ;
    END
  END in_key[6]
  PIN in_key[70]
    DIRECTION INPUT ;
    USE SIGNAL ;
    PORT
      LAYER M5 ;
        RECT  22.032 47.436 22.056 47.52 ;
    END
  END in_key[70]
  PIN in_key[71]
    DIRECTION INPUT ;
    USE SIGNAL ;
    PORT
      LAYER M5 ;
        RECT  22.128 47.436 22.152 47.52 ;
    END
  END in_key[71]
  PIN in_key[72]
    DIRECTION INPUT ;
    USE SIGNAL ;
    PORT
      LAYER M5 ;
        RECT  22.224 47.436 22.248 47.52 ;
    END
  END in_key[72]
  PIN in_key[73]
    DIRECTION INPUT ;
    USE SIGNAL ;
    PORT
      LAYER M5 ;
        RECT  22.32 47.436 22.344 47.52 ;
    END
  END in_key[73]
  PIN in_key[74]
    DIRECTION INPUT ;
    USE SIGNAL ;
    PORT
      LAYER M5 ;
        RECT  22.416 47.436 22.44 47.52 ;
    END
  END in_key[74]
  PIN in_key[75]
    DIRECTION INPUT ;
    USE SIGNAL ;
    PORT
      LAYER M5 ;
        RECT  22.512 47.436 22.536 47.52 ;
    END
  END in_key[75]
  PIN in_key[76]
    DIRECTION INPUT ;
    USE SIGNAL ;
    PORT
      LAYER M5 ;
        RECT  22.608 47.436 22.632 47.52 ;
    END
  END in_key[76]
  PIN in_key[77]
    DIRECTION INPUT ;
    USE SIGNAL ;
    PORT
      LAYER M5 ;
        RECT  22.704 47.436 22.728 47.52 ;
    END
  END in_key[77]
  PIN in_key[78]
    DIRECTION INPUT ;
    USE SIGNAL ;
    PORT
      LAYER M5 ;
        RECT  22.8 47.436 22.824 47.52 ;
    END
  END in_key[78]
  PIN in_key[79]
    DIRECTION INPUT ;
    USE SIGNAL ;
    PORT
      LAYER M5 ;
        RECT  22.896 47.436 22.92 47.52 ;
    END
  END in_key[79]
  PIN in_key[7]
    DIRECTION INPUT ;
    USE SIGNAL ;
    PORT
      LAYER M5 ;
        RECT  19.056 47.436 19.08 47.52 ;
    END
  END in_key[7]
  PIN in_key[80]
    DIRECTION INPUT ;
    USE SIGNAL ;
    PORT
      LAYER M5 ;
        RECT  22.992 47.436 23.016 47.52 ;
    END
  END in_key[80]
  PIN in_key[81]
    DIRECTION INPUT ;
    USE SIGNAL ;
    PORT
      LAYER M5 ;
        RECT  23.088 47.436 23.112 47.52 ;
    END
  END in_key[81]
  PIN in_key[82]
    DIRECTION INPUT ;
    USE SIGNAL ;
    PORT
      LAYER M5 ;
        RECT  23.184 47.436 23.208 47.52 ;
    END
  END in_key[82]
  PIN in_key[83]
    DIRECTION INPUT ;
    USE SIGNAL ;
    PORT
      LAYER M5 ;
        RECT  23.28 47.436 23.304 47.52 ;
    END
  END in_key[83]
  PIN in_key[84]
    DIRECTION INPUT ;
    USE SIGNAL ;
    PORT
      LAYER M5 ;
        RECT  23.376 47.436 23.4 47.52 ;
    END
  END in_key[84]
  PIN in_key[85]
    DIRECTION INPUT ;
    USE SIGNAL ;
    PORT
      LAYER M5 ;
        RECT  23.472 47.436 23.496 47.52 ;
    END
  END in_key[85]
  PIN in_key[86]
    DIRECTION INPUT ;
    USE SIGNAL ;
    PORT
      LAYER M5 ;
        RECT  23.568 47.436 23.592 47.52 ;
    END
  END in_key[86]
  PIN in_key[87]
    DIRECTION INPUT ;
    USE SIGNAL ;
    PORT
      LAYER M5 ;
        RECT  23.664 47.436 23.688 47.52 ;
    END
  END in_key[87]
  PIN in_key[88]
    DIRECTION INPUT ;
    USE SIGNAL ;
    PORT
      LAYER M5 ;
        RECT  23.76 47.436 23.784 47.52 ;
    END
  END in_key[88]
  PIN in_key[89]
    DIRECTION INPUT ;
    USE SIGNAL ;
    PORT
      LAYER M5 ;
        RECT  23.856 47.436 23.88 47.52 ;
    END
  END in_key[89]
  PIN in_key[8]
    DIRECTION INPUT ;
    USE SIGNAL ;
    PORT
      LAYER M5 ;
        RECT  19.152 47.436 19.176 47.52 ;
    END
  END in_key[8]
  PIN in_key[90]
    DIRECTION INPUT ;
    USE SIGNAL ;
    PORT
      LAYER M5 ;
        RECT  23.952 47.436 23.976 47.52 ;
    END
  END in_key[90]
  PIN in_key[91]
    DIRECTION INPUT ;
    USE SIGNAL ;
    PORT
      LAYER M5 ;
        RECT  24.048 47.436 24.072 47.52 ;
    END
  END in_key[91]
  PIN in_key[92]
    DIRECTION INPUT ;
    USE SIGNAL ;
    PORT
      LAYER M5 ;
        RECT  24.144 47.436 24.168 47.52 ;
    END
  END in_key[92]
  PIN in_key[93]
    DIRECTION INPUT ;
    USE SIGNAL ;
    PORT
      LAYER M5 ;
        RECT  24.24 47.436 24.264 47.52 ;
    END
  END in_key[93]
  PIN in_key[94]
    DIRECTION INPUT ;
    USE SIGNAL ;
    PORT
      LAYER M5 ;
        RECT  24.336 47.436 24.36 47.52 ;
    END
  END in_key[94]
  PIN in_key[95]
    DIRECTION INPUT ;
    USE SIGNAL ;
    PORT
      LAYER M5 ;
        RECT  33.648 47.436 33.672 47.52 ;
    END
  END in_key[95]
  PIN in_key[96]
    DIRECTION INPUT ;
    USE SIGNAL ;
    PORT
      LAYER M5 ;
        RECT  33.744 47.436 33.768 47.52 ;
    END
  END in_key[96]
  PIN in_key[97]
    DIRECTION INPUT ;
    USE SIGNAL ;
    PORT
      LAYER M5 ;
        RECT  33.84 47.436 33.864 47.52 ;
    END
  END in_key[97]
  PIN in_key[98]
    DIRECTION INPUT ;
    USE SIGNAL ;
    PORT
      LAYER M5 ;
        RECT  33.936 47.436 33.96 47.52 ;
    END
  END in_key[98]
  PIN in_key[99]
    DIRECTION INPUT ;
    USE SIGNAL ;
    PORT
      LAYER M5 ;
        RECT  34.032 47.436 34.056 47.52 ;
    END
  END in_key[99]
  PIN in_key[9]
    DIRECTION INPUT ;
    USE SIGNAL ;
    PORT
      LAYER M5 ;
        RECT  19.248 47.436 19.272 47.52 ;
    END
  END in_key[9]
  PIN in_meta[0]
    DIRECTION INPUT ;
    USE SIGNAL ;
    PORT
      LAYER M5 ;
        RECT  43.728 47.436 43.752 47.52 ;
    END
  END in_meta[0]
  PIN in_meta[100]
    DIRECTION INPUT ;
    USE SIGNAL ;
    PORT
      LAYER M5 ;
        RECT  41.04 47.436 41.064 47.52 ;
    END
  END in_meta[100]
  PIN in_meta[101]
    DIRECTION INPUT ;
    USE SIGNAL ;
    PORT
      LAYER M5 ;
        RECT  41.136 47.436 41.16 47.52 ;
    END
  END in_meta[101]
  PIN in_meta[102]
    DIRECTION INPUT ;
    USE SIGNAL ;
    PORT
      LAYER M5 ;
        RECT  41.232 47.436 41.256 47.52 ;
    END
  END in_meta[102]
  PIN in_meta[103]
    DIRECTION INPUT ;
    USE SIGNAL ;
    PORT
      LAYER M5 ;
        RECT  41.328 47.436 41.352 47.52 ;
    END
  END in_meta[103]
  PIN in_meta[104]
    DIRECTION INPUT ;
    USE SIGNAL ;
    PORT
      LAYER M5 ;
        RECT  41.424 47.436 41.448 47.52 ;
    END
  END in_meta[104]
  PIN in_meta[105]
    DIRECTION INPUT ;
    USE SIGNAL ;
    PORT
      LAYER M5 ;
        RECT  41.52 47.436 41.544 47.52 ;
    END
  END in_meta[105]
  PIN in_meta[106]
    DIRECTION INPUT ;
    USE SIGNAL ;
    PORT
      LAYER M5 ;
        RECT  41.616 47.436 41.64 47.52 ;
    END
  END in_meta[106]
  PIN in_meta[107]
    DIRECTION INPUT ;
    USE SIGNAL ;
    PORT
      LAYER M5 ;
        RECT  41.712 47.436 41.736 47.52 ;
    END
  END in_meta[107]
  PIN in_meta[108]
    DIRECTION INPUT ;
    USE SIGNAL ;
    PORT
      LAYER M5 ;
        RECT  41.808 47.436 41.832 47.52 ;
    END
  END in_meta[108]
  PIN in_meta[109]
    DIRECTION INPUT ;
    USE SIGNAL ;
    PORT
      LAYER M5 ;
        RECT  41.904 47.436 41.928 47.52 ;
    END
  END in_meta[109]
  PIN in_meta[10]
    DIRECTION INPUT ;
    USE SIGNAL ;
    PORT
      LAYER M5 ;
        RECT  44.688 47.436 44.712 47.52 ;
    END
  END in_meta[10]
  PIN in_meta[110]
    DIRECTION INPUT ;
    USE SIGNAL ;
    PORT
      LAYER M5 ;
        RECT  42 47.436 42.024 47.52 ;
    END
  END in_meta[110]
  PIN in_meta[111]
    DIRECTION INPUT ;
    USE SIGNAL ;
    PORT
      LAYER M5 ;
        RECT  42.096 47.436 42.12 47.52 ;
    END
  END in_meta[111]
  PIN in_meta[112]
    DIRECTION INPUT ;
    USE SIGNAL ;
    PORT
      LAYER M5 ;
        RECT  42.192 47.436 42.216 47.52 ;
    END
  END in_meta[112]
  PIN in_meta[113]
    DIRECTION INPUT ;
    USE SIGNAL ;
    PORT
      LAYER M5 ;
        RECT  42.288 47.436 42.312 47.52 ;
    END
  END in_meta[113]
  PIN in_meta[114]
    DIRECTION INPUT ;
    USE SIGNAL ;
    PORT
      LAYER M5 ;
        RECT  42.384 47.436 42.408 47.52 ;
    END
  END in_meta[114]
  PIN in_meta[115]
    DIRECTION INPUT ;
    USE SIGNAL ;
    PORT
      LAYER M5 ;
        RECT  42.48 47.436 42.504 47.52 ;
    END
  END in_meta[115]
  PIN in_meta[116]
    DIRECTION INPUT ;
    USE SIGNAL ;
    PORT
      LAYER M5 ;
        RECT  42.576 47.436 42.6 47.52 ;
    END
  END in_meta[116]
  PIN in_meta[117]
    DIRECTION INPUT ;
    USE SIGNAL ;
    PORT
      LAYER M5 ;
        RECT  42.672 47.436 42.696 47.52 ;
    END
  END in_meta[117]
  PIN in_meta[118]
    DIRECTION INPUT ;
    USE SIGNAL ;
    PORT
      LAYER M5 ;
        RECT  42.768 47.436 42.792 47.52 ;
    END
  END in_meta[118]
  PIN in_meta[119]
    DIRECTION INPUT ;
    USE SIGNAL ;
    PORT
      LAYER M5 ;
        RECT  42.864 47.436 42.888 47.52 ;
    END
  END in_meta[119]
  PIN in_meta[11]
    DIRECTION INPUT ;
    USE SIGNAL ;
    PORT
      LAYER M5 ;
        RECT  44.784 47.436 44.808 47.52 ;
    END
  END in_meta[11]
  PIN in_meta[120]
    DIRECTION INPUT ;
    USE SIGNAL ;
    PORT
      LAYER M5 ;
        RECT  42.96 47.436 42.984 47.52 ;
    END
  END in_meta[120]
  PIN in_meta[121]
    DIRECTION INPUT ;
    USE SIGNAL ;
    PORT
      LAYER M5 ;
        RECT  43.056 47.436 43.08 47.52 ;
    END
  END in_meta[121]
  PIN in_meta[122]
    DIRECTION INPUT ;
    USE SIGNAL ;
    PORT
      LAYER M5 ;
        RECT  43.152 47.436 43.176 47.52 ;
    END
  END in_meta[122]
  PIN in_meta[123]
    DIRECTION INPUT ;
    USE SIGNAL ;
    PORT
      LAYER M5 ;
        RECT  43.248 47.436 43.272 47.52 ;
    END
  END in_meta[123]
  PIN in_meta[124]
    DIRECTION INPUT ;
    USE SIGNAL ;
    PORT
      LAYER M5 ;
        RECT  43.344 47.436 43.368 47.52 ;
    END
  END in_meta[124]
  PIN in_meta[125]
    DIRECTION INPUT ;
    USE SIGNAL ;
    PORT
      LAYER M5 ;
        RECT  43.44 47.436 43.464 47.52 ;
    END
  END in_meta[125]
  PIN in_meta[126]
    DIRECTION INPUT ;
    USE SIGNAL ;
    PORT
      LAYER M5 ;
        RECT  43.536 47.436 43.56 47.52 ;
    END
  END in_meta[126]
  PIN in_meta[127]
    DIRECTION INPUT ;
    USE SIGNAL ;
    PORT
      LAYER M5 ;
        RECT  54.576 47.436 54.6 47.52 ;
    END
  END in_meta[127]
  PIN in_meta[128]
    DIRECTION INPUT ;
    USE SIGNAL ;
    PORT
      LAYER M5 ;
        RECT  54.672 47.436 54.696 47.52 ;
    END
  END in_meta[128]
  PIN in_meta[129]
    DIRECTION INPUT ;
    USE SIGNAL ;
    PORT
      LAYER M5 ;
        RECT  54.768 47.436 54.792 47.52 ;
    END
  END in_meta[129]
  PIN in_meta[12]
    DIRECTION INPUT ;
    USE SIGNAL ;
    PORT
      LAYER M5 ;
        RECT  44.88 47.436 44.904 47.52 ;
    END
  END in_meta[12]
  PIN in_meta[130]
    DIRECTION INPUT ;
    USE SIGNAL ;
    PORT
      LAYER M5 ;
        RECT  54.864 47.436 54.888 47.52 ;
    END
  END in_meta[130]
  PIN in_meta[131]
    DIRECTION INPUT ;
    USE SIGNAL ;
    PORT
      LAYER M5 ;
        RECT  54.96 47.436 54.984 47.52 ;
    END
  END in_meta[131]
  PIN in_meta[13]
    DIRECTION INPUT ;
    USE SIGNAL ;
    PORT
      LAYER M5 ;
        RECT  44.976 47.436 45 47.52 ;
    END
  END in_meta[13]
  PIN in_meta[14]
    DIRECTION INPUT ;
    USE SIGNAL ;
    PORT
      LAYER M5 ;
        RECT  45.072 47.436 45.096 47.52 ;
    END
  END in_meta[14]
  PIN in_meta[15]
    DIRECTION INPUT ;
    USE SIGNAL ;
    PORT
      LAYER M5 ;
        RECT  45.168 47.436 45.192 47.52 ;
    END
  END in_meta[15]
  PIN in_meta[16]
    DIRECTION INPUT ;
    USE SIGNAL ;
    PORT
      LAYER M5 ;
        RECT  45.264 47.436 45.288 47.52 ;
    END
  END in_meta[16]
  PIN in_meta[17]
    DIRECTION INPUT ;
    USE SIGNAL ;
    PORT
      LAYER M5 ;
        RECT  45.36 47.436 45.384 47.52 ;
    END
  END in_meta[17]
  PIN in_meta[18]
    DIRECTION INPUT ;
    USE SIGNAL ;
    PORT
      LAYER M5 ;
        RECT  45.456 47.436 45.48 47.52 ;
    END
  END in_meta[18]
  PIN in_meta[19]
    DIRECTION INPUT ;
    USE SIGNAL ;
    PORT
      LAYER M5 ;
        RECT  45.552 47.436 45.576 47.52 ;
    END
  END in_meta[19]
  PIN in_meta[1]
    DIRECTION INPUT ;
    USE SIGNAL ;
    PORT
      LAYER M5 ;
        RECT  43.824 47.436 43.848 47.52 ;
    END
  END in_meta[1]
  PIN in_meta[20]
    DIRECTION INPUT ;
    USE SIGNAL ;
    PORT
      LAYER M5 ;
        RECT  45.648 47.436 45.672 47.52 ;
    END
  END in_meta[20]
  PIN in_meta[21]
    DIRECTION INPUT ;
    USE SIGNAL ;
    PORT
      LAYER M5 ;
        RECT  45.744 47.436 45.768 47.52 ;
    END
  END in_meta[21]
  PIN in_meta[22]
    DIRECTION INPUT ;
    USE SIGNAL ;
    PORT
      LAYER M5 ;
        RECT  45.84 47.436 45.864 47.52 ;
    END
  END in_meta[22]
  PIN in_meta[23]
    DIRECTION INPUT ;
    USE SIGNAL ;
    PORT
      LAYER M5 ;
        RECT  45.936 47.436 45.96 47.52 ;
    END
  END in_meta[23]
  PIN in_meta[24]
    DIRECTION INPUT ;
    USE SIGNAL ;
    PORT
      LAYER M5 ;
        RECT  46.032 47.436 46.056 47.52 ;
    END
  END in_meta[24]
  PIN in_meta[25]
    DIRECTION INPUT ;
    USE SIGNAL ;
    PORT
      LAYER M5 ;
        RECT  46.128 47.436 46.152 47.52 ;
    END
  END in_meta[25]
  PIN in_meta[26]
    DIRECTION INPUT ;
    USE SIGNAL ;
    PORT
      LAYER M5 ;
        RECT  46.224 47.436 46.248 47.52 ;
    END
  END in_meta[26]
  PIN in_meta[27]
    DIRECTION INPUT ;
    USE SIGNAL ;
    PORT
      LAYER M5 ;
        RECT  46.32 47.436 46.344 47.52 ;
    END
  END in_meta[27]
  PIN in_meta[28]
    DIRECTION INPUT ;
    USE SIGNAL ;
    PORT
      LAYER M5 ;
        RECT  46.416 47.436 46.44 47.52 ;
    END
  END in_meta[28]
  PIN in_meta[29]
    DIRECTION INPUT ;
    USE SIGNAL ;
    PORT
      LAYER M5 ;
        RECT  46.512 47.436 46.536 47.52 ;
    END
  END in_meta[29]
  PIN in_meta[2]
    DIRECTION INPUT ;
    USE SIGNAL ;
    PORT
      LAYER M5 ;
        RECT  43.92 47.436 43.944 47.52 ;
    END
  END in_meta[2]
  PIN in_meta[30]
    DIRECTION INPUT ;
    USE SIGNAL ;
    PORT
      LAYER M5 ;
        RECT  46.608 47.436 46.632 47.52 ;
    END
  END in_meta[30]
  PIN in_meta[31]
    DIRECTION INPUT ;
    USE SIGNAL ;
    PORT
      LAYER M5 ;
        RECT  49.776 47.436 49.8 47.52 ;
    END
  END in_meta[31]
  PIN in_meta[32]
    DIRECTION INPUT ;
    USE SIGNAL ;
    PORT
      LAYER M5 ;
        RECT  49.872 47.436 49.896 47.52 ;
    END
  END in_meta[32]
  PIN in_meta[33]
    DIRECTION INPUT ;
    USE SIGNAL ;
    PORT
      LAYER M5 ;
        RECT  49.968 47.436 49.992 47.52 ;
    END
  END in_meta[33]
  PIN in_meta[34]
    DIRECTION INPUT ;
    USE SIGNAL ;
    PORT
      LAYER M5 ;
        RECT  50.064 47.436 50.088 47.52 ;
    END
  END in_meta[34]
  PIN in_meta[35]
    DIRECTION INPUT ;
    USE SIGNAL ;
    PORT
      LAYER M5 ;
        RECT  50.16 47.436 50.184 47.52 ;
    END
  END in_meta[35]
  PIN in_meta[36]
    DIRECTION INPUT ;
    USE SIGNAL ;
    PORT
      LAYER M5 ;
        RECT  50.256 47.436 50.28 47.52 ;
    END
  END in_meta[36]
  PIN in_meta[37]
    DIRECTION INPUT ;
    USE SIGNAL ;
    PORT
      LAYER M5 ;
        RECT  50.352 47.436 50.376 47.52 ;
    END
  END in_meta[37]
  PIN in_meta[38]
    DIRECTION INPUT ;
    USE SIGNAL ;
    PORT
      LAYER M5 ;
        RECT  50.448 47.436 50.472 47.52 ;
    END
  END in_meta[38]
  PIN in_meta[39]
    DIRECTION INPUT ;
    USE SIGNAL ;
    PORT
      LAYER M5 ;
        RECT  50.544 47.436 50.568 47.52 ;
    END
  END in_meta[39]
  PIN in_meta[3]
    DIRECTION INPUT ;
    USE SIGNAL ;
    PORT
      LAYER M5 ;
        RECT  44.016 47.436 44.04 47.52 ;
    END
  END in_meta[3]
  PIN in_meta[40]
    DIRECTION INPUT ;
    USE SIGNAL ;
    PORT
      LAYER M5 ;
        RECT  50.64 47.436 50.664 47.52 ;
    END
  END in_meta[40]
  PIN in_meta[41]
    DIRECTION INPUT ;
    USE SIGNAL ;
    PORT
      LAYER M5 ;
        RECT  50.736 47.436 50.76 47.52 ;
    END
  END in_meta[41]
  PIN in_meta[42]
    DIRECTION INPUT ;
    USE SIGNAL ;
    PORT
      LAYER M5 ;
        RECT  50.832 47.436 50.856 47.52 ;
    END
  END in_meta[42]
  PIN in_meta[43]
    DIRECTION INPUT ;
    USE SIGNAL ;
    PORT
      LAYER M5 ;
        RECT  50.928 47.436 50.952 47.52 ;
    END
  END in_meta[43]
  PIN in_meta[44]
    DIRECTION INPUT ;
    USE SIGNAL ;
    PORT
      LAYER M5 ;
        RECT  51.024 47.436 51.048 47.52 ;
    END
  END in_meta[44]
  PIN in_meta[45]
    DIRECTION INPUT ;
    USE SIGNAL ;
    PORT
      LAYER M5 ;
        RECT  51.12 47.436 51.144 47.52 ;
    END
  END in_meta[45]
  PIN in_meta[46]
    DIRECTION INPUT ;
    USE SIGNAL ;
    PORT
      LAYER M5 ;
        RECT  51.216 47.436 51.24 47.52 ;
    END
  END in_meta[46]
  PIN in_meta[47]
    DIRECTION INPUT ;
    USE SIGNAL ;
    PORT
      LAYER M5 ;
        RECT  51.312 47.436 51.336 47.52 ;
    END
  END in_meta[47]
  PIN in_meta[48]
    DIRECTION INPUT ;
    USE SIGNAL ;
    PORT
      LAYER M5 ;
        RECT  51.408 47.436 51.432 47.52 ;
    END
  END in_meta[48]
  PIN in_meta[49]
    DIRECTION INPUT ;
    USE SIGNAL ;
    PORT
      LAYER M5 ;
        RECT  51.504 47.436 51.528 47.52 ;
    END
  END in_meta[49]
  PIN in_meta[4]
    DIRECTION INPUT ;
    USE SIGNAL ;
    PORT
      LAYER M5 ;
        RECT  44.112 47.436 44.136 47.52 ;
    END
  END in_meta[4]
  PIN in_meta[50]
    DIRECTION INPUT ;
    USE SIGNAL ;
    PORT
      LAYER M5 ;
        RECT  51.6 47.436 51.624 47.52 ;
    END
  END in_meta[50]
  PIN in_meta[51]
    DIRECTION INPUT ;
    USE SIGNAL ;
    PORT
      LAYER M5 ;
        RECT  51.696 47.436 51.72 47.52 ;
    END
  END in_meta[51]
  PIN in_meta[52]
    DIRECTION INPUT ;
    USE SIGNAL ;
    PORT
      LAYER M5 ;
        RECT  51.792 47.436 51.816 47.52 ;
    END
  END in_meta[52]
  PIN in_meta[53]
    DIRECTION INPUT ;
    USE SIGNAL ;
    PORT
      LAYER M5 ;
        RECT  51.888 47.436 51.912 47.52 ;
    END
  END in_meta[53]
  PIN in_meta[54]
    DIRECTION INPUT ;
    USE SIGNAL ;
    PORT
      LAYER M5 ;
        RECT  51.984 47.436 52.008 47.52 ;
    END
  END in_meta[54]
  PIN in_meta[55]
    DIRECTION INPUT ;
    USE SIGNAL ;
    PORT
      LAYER M5 ;
        RECT  52.08 47.436 52.104 47.52 ;
    END
  END in_meta[55]
  PIN in_meta[56]
    DIRECTION INPUT ;
    USE SIGNAL ;
    PORT
      LAYER M5 ;
        RECT  52.176 47.436 52.2 47.52 ;
    END
  END in_meta[56]
  PIN in_meta[57]
    DIRECTION INPUT ;
    USE SIGNAL ;
    PORT
      LAYER M5 ;
        RECT  52.272 47.436 52.296 47.52 ;
    END
  END in_meta[57]
  PIN in_meta[58]
    DIRECTION INPUT ;
    USE SIGNAL ;
    PORT
      LAYER M5 ;
        RECT  52.368 47.436 52.392 47.52 ;
    END
  END in_meta[58]
  PIN in_meta[59]
    DIRECTION INPUT ;
    USE SIGNAL ;
    PORT
      LAYER M5 ;
        RECT  52.464 47.436 52.488 47.52 ;
    END
  END in_meta[59]
  PIN in_meta[5]
    DIRECTION INPUT ;
    USE SIGNAL ;
    PORT
      LAYER M5 ;
        RECT  44.208 47.436 44.232 47.52 ;
    END
  END in_meta[5]
  PIN in_meta[60]
    DIRECTION INPUT ;
    USE SIGNAL ;
    PORT
      LAYER M5 ;
        RECT  52.56 47.436 52.584 47.52 ;
    END
  END in_meta[60]
  PIN in_meta[61]
    DIRECTION INPUT ;
    USE SIGNAL ;
    PORT
      LAYER M5 ;
        RECT  52.656 47.436 52.68 47.52 ;
    END
  END in_meta[61]
  PIN in_meta[62]
    DIRECTION INPUT ;
    USE SIGNAL ;
    PORT
      LAYER M5 ;
        RECT  52.752 47.436 52.776 47.52 ;
    END
  END in_meta[62]
  PIN in_meta[63]
    DIRECTION INPUT ;
    USE SIGNAL ;
    PORT
      LAYER M5 ;
        RECT  46.704 47.436 46.728 47.52 ;
    END
  END in_meta[63]
  PIN in_meta[64]
    DIRECTION INPUT ;
    USE SIGNAL ;
    PORT
      LAYER M5 ;
        RECT  46.8 47.436 46.824 47.52 ;
    END
  END in_meta[64]
  PIN in_meta[65]
    DIRECTION INPUT ;
    USE SIGNAL ;
    PORT
      LAYER M5 ;
        RECT  46.896 47.436 46.92 47.52 ;
    END
  END in_meta[65]
  PIN in_meta[66]
    DIRECTION INPUT ;
    USE SIGNAL ;
    PORT
      LAYER M5 ;
        RECT  46.992 47.436 47.016 47.52 ;
    END
  END in_meta[66]
  PIN in_meta[67]
    DIRECTION INPUT ;
    USE SIGNAL ;
    PORT
      LAYER M5 ;
        RECT  47.088 47.436 47.112 47.52 ;
    END
  END in_meta[67]
  PIN in_meta[68]
    DIRECTION INPUT ;
    USE SIGNAL ;
    PORT
      LAYER M5 ;
        RECT  47.184 47.436 47.208 47.52 ;
    END
  END in_meta[68]
  PIN in_meta[69]
    DIRECTION INPUT ;
    USE SIGNAL ;
    PORT
      LAYER M5 ;
        RECT  47.28 47.436 47.304 47.52 ;
    END
  END in_meta[69]
  PIN in_meta[6]
    DIRECTION INPUT ;
    USE SIGNAL ;
    PORT
      LAYER M5 ;
        RECT  44.304 47.436 44.328 47.52 ;
    END
  END in_meta[6]
  PIN in_meta[70]
    DIRECTION INPUT ;
    USE SIGNAL ;
    PORT
      LAYER M5 ;
        RECT  47.376 47.436 47.4 47.52 ;
    END
  END in_meta[70]
  PIN in_meta[71]
    DIRECTION INPUT ;
    USE SIGNAL ;
    PORT
      LAYER M5 ;
        RECT  47.472 47.436 47.496 47.52 ;
    END
  END in_meta[71]
  PIN in_meta[72]
    DIRECTION INPUT ;
    USE SIGNAL ;
    PORT
      LAYER M5 ;
        RECT  47.568 47.436 47.592 47.52 ;
    END
  END in_meta[72]
  PIN in_meta[73]
    DIRECTION INPUT ;
    USE SIGNAL ;
    PORT
      LAYER M5 ;
        RECT  47.664 47.436 47.688 47.52 ;
    END
  END in_meta[73]
  PIN in_meta[74]
    DIRECTION INPUT ;
    USE SIGNAL ;
    PORT
      LAYER M5 ;
        RECT  47.76 47.436 47.784 47.52 ;
    END
  END in_meta[74]
  PIN in_meta[75]
    DIRECTION INPUT ;
    USE SIGNAL ;
    PORT
      LAYER M5 ;
        RECT  47.856 47.436 47.88 47.52 ;
    END
  END in_meta[75]
  PIN in_meta[76]
    DIRECTION INPUT ;
    USE SIGNAL ;
    PORT
      LAYER M5 ;
        RECT  47.952 47.436 47.976 47.52 ;
    END
  END in_meta[76]
  PIN in_meta[77]
    DIRECTION INPUT ;
    USE SIGNAL ;
    PORT
      LAYER M5 ;
        RECT  48.048 47.436 48.072 47.52 ;
    END
  END in_meta[77]
  PIN in_meta[78]
    DIRECTION INPUT ;
    USE SIGNAL ;
    PORT
      LAYER M5 ;
        RECT  48.144 47.436 48.168 47.52 ;
    END
  END in_meta[78]
  PIN in_meta[79]
    DIRECTION INPUT ;
    USE SIGNAL ;
    PORT
      LAYER M5 ;
        RECT  48.24 47.436 48.264 47.52 ;
    END
  END in_meta[79]
  PIN in_meta[7]
    DIRECTION INPUT ;
    USE SIGNAL ;
    PORT
      LAYER M5 ;
        RECT  44.4 47.436 44.424 47.52 ;
    END
  END in_meta[7]
  PIN in_meta[80]
    DIRECTION INPUT ;
    USE SIGNAL ;
    PORT
      LAYER M5 ;
        RECT  48.336 47.436 48.36 47.52 ;
    END
  END in_meta[80]
  PIN in_meta[81]
    DIRECTION INPUT ;
    USE SIGNAL ;
    PORT
      LAYER M5 ;
        RECT  48.432 47.436 48.456 47.52 ;
    END
  END in_meta[81]
  PIN in_meta[82]
    DIRECTION INPUT ;
    USE SIGNAL ;
    PORT
      LAYER M5 ;
        RECT  48.528 47.436 48.552 47.52 ;
    END
  END in_meta[82]
  PIN in_meta[83]
    DIRECTION INPUT ;
    USE SIGNAL ;
    PORT
      LAYER M5 ;
        RECT  48.624 47.436 48.648 47.52 ;
    END
  END in_meta[83]
  PIN in_meta[84]
    DIRECTION INPUT ;
    USE SIGNAL ;
    PORT
      LAYER M5 ;
        RECT  48.72 47.436 48.744 47.52 ;
    END
  END in_meta[84]
  PIN in_meta[85]
    DIRECTION INPUT ;
    USE SIGNAL ;
    PORT
      LAYER M5 ;
        RECT  48.816 47.436 48.84 47.52 ;
    END
  END in_meta[85]
  PIN in_meta[86]
    DIRECTION INPUT ;
    USE SIGNAL ;
    PORT
      LAYER M5 ;
        RECT  48.912 47.436 48.936 47.52 ;
    END
  END in_meta[86]
  PIN in_meta[87]
    DIRECTION INPUT ;
    USE SIGNAL ;
    PORT
      LAYER M5 ;
        RECT  49.008 47.436 49.032 47.52 ;
    END
  END in_meta[87]
  PIN in_meta[88]
    DIRECTION INPUT ;
    USE SIGNAL ;
    PORT
      LAYER M5 ;
        RECT  49.104 47.436 49.128 47.52 ;
    END
  END in_meta[88]
  PIN in_meta[89]
    DIRECTION INPUT ;
    USE SIGNAL ;
    PORT
      LAYER M5 ;
        RECT  49.2 47.436 49.224 47.52 ;
    END
  END in_meta[89]
  PIN in_meta[8]
    DIRECTION INPUT ;
    USE SIGNAL ;
    PORT
      LAYER M5 ;
        RECT  44.496 47.436 44.52 47.52 ;
    END
  END in_meta[8]
  PIN in_meta[90]
    DIRECTION INPUT ;
    USE SIGNAL ;
    PORT
      LAYER M5 ;
        RECT  49.296 47.436 49.32 47.52 ;
    END
  END in_meta[90]
  PIN in_meta[91]
    DIRECTION INPUT ;
    USE SIGNAL ;
    PORT
      LAYER M5 ;
        RECT  49.392 47.436 49.416 47.52 ;
    END
  END in_meta[91]
  PIN in_meta[92]
    DIRECTION INPUT ;
    USE SIGNAL ;
    PORT
      LAYER M5 ;
        RECT  49.488 47.436 49.512 47.52 ;
    END
  END in_meta[92]
  PIN in_meta[93]
    DIRECTION INPUT ;
    USE SIGNAL ;
    PORT
      LAYER M5 ;
        RECT  49.584 47.436 49.608 47.52 ;
    END
  END in_meta[93]
  PIN in_meta[94]
    DIRECTION INPUT ;
    USE SIGNAL ;
    PORT
      LAYER M5 ;
        RECT  49.68 47.436 49.704 47.52 ;
    END
  END in_meta[94]
  PIN in_meta[95]
    DIRECTION INPUT ;
    USE SIGNAL ;
    PORT
      LAYER M5 ;
        RECT  40.56 47.436 40.584 47.52 ;
    END
  END in_meta[95]
  PIN in_meta[96]
    DIRECTION INPUT ;
    USE SIGNAL ;
    PORT
      LAYER M5 ;
        RECT  40.656 47.436 40.68 47.52 ;
    END
  END in_meta[96]
  PIN in_meta[97]
    DIRECTION INPUT ;
    USE SIGNAL ;
    PORT
      LAYER M5 ;
        RECT  40.752 47.436 40.776 47.52 ;
    END
  END in_meta[97]
  PIN in_meta[98]
    DIRECTION INPUT ;
    USE SIGNAL ;
    PORT
      LAYER M5 ;
        RECT  40.848 47.436 40.872 47.52 ;
    END
  END in_meta[98]
  PIN in_meta[99]
    DIRECTION INPUT ;
    USE SIGNAL ;
    PORT
      LAYER M5 ;
        RECT  40.944 47.436 40.968 47.52 ;
    END
  END in_meta[99]
  PIN in_meta[9]
    DIRECTION INPUT ;
    USE SIGNAL ;
    PORT
      LAYER M5 ;
        RECT  44.592 47.436 44.616 47.52 ;
    END
  END in_meta[9]
  PIN in_slot[0]
    DIRECTION INPUT ;
    USE SIGNAL ;
    PORT
      LAYER M5 ;
        RECT  55.056 47.436 55.08 47.52 ;
    END
  END in_slot[0]
  PIN in_slot[1]
    DIRECTION INPUT ;
    USE SIGNAL ;
    PORT
      LAYER M5 ;
        RECT  55.152 47.436 55.176 47.52 ;
    END
  END in_slot[1]
  PIN in_slot[2]
    DIRECTION INPUT ;
    USE SIGNAL ;
    PORT
      LAYER M5 ;
        RECT  55.248 47.436 55.272 47.52 ;
    END
  END in_slot[2]
  PIN in_slot[3]
    DIRECTION INPUT ;
    USE SIGNAL ;
    PORT
      LAYER M5 ;
        RECT  55.344 47.436 55.368 47.52 ;
    END
  END in_slot[3]
  PIN in_v[0]
    DIRECTION INPUT ;
    USE SIGNAL ;
    PORT
      LAYER M5 ;
        RECT  55.44 47.436 55.464 47.52 ;
    END
  END in_v[0]
  PIN in_v[1]
    DIRECTION INPUT ;
    USE SIGNAL ;
    PORT
      LAYER M5 ;
        RECT  55.536 47.436 55.56 47.52 ;
    END
  END in_v[1]
  PIN in_v[2]
    DIRECTION INPUT ;
    USE SIGNAL ;
    PORT
      LAYER M5 ;
        RECT  55.632 47.436 55.656 47.52 ;
    END
  END in_v[2]
  PIN in_v[3]
    DIRECTION INPUT ;
    USE SIGNAL ;
    PORT
      LAYER M5 ;
        RECT  55.728 47.436 55.752 47.52 ;
    END
  END in_v[3]
  PIN mode
    DIRECTION INPUT ;
    USE SIGNAL ;
    PORT
      LAYER M4 ;
        RECT  0 41.136 0.084 41.16 ;
    END
  END mode
  PIN out_flit[0]
    DIRECTION OUTPUT ;
    USE SIGNAL ;
    PORT
      LAYER M5 ;
        RECT  45.36 0 45.384 0.084 ;
    END
  END out_flit[0]
  PIN out_flit[100]
    DIRECTION OUTPUT ;
    USE SIGNAL ;
    PORT
      LAYER M5 ;
        RECT  54.96 0 54.984 0.084 ;
    END
  END out_flit[100]
  PIN out_flit[101]
    DIRECTION OUTPUT ;
    USE SIGNAL ;
    PORT
      LAYER M5 ;
        RECT  55.056 0 55.08 0.084 ;
    END
  END out_flit[101]
  PIN out_flit[102]
    DIRECTION OUTPUT ;
    USE SIGNAL ;
    PORT
      LAYER M5 ;
        RECT  55.152 0 55.176 0.084 ;
    END
  END out_flit[102]
  PIN out_flit[103]
    DIRECTION OUTPUT ;
    USE SIGNAL ;
    PORT
      LAYER M5 ;
        RECT  55.248 0 55.272 0.084 ;
    END
  END out_flit[103]
  PIN out_flit[104]
    DIRECTION OUTPUT ;
    USE SIGNAL ;
    PORT
      LAYER M5 ;
        RECT  55.344 0 55.368 0.084 ;
    END
  END out_flit[104]
  PIN out_flit[105]
    DIRECTION OUTPUT ;
    USE SIGNAL ;
    PORT
      LAYER M5 ;
        RECT  55.44 0 55.464 0.084 ;
    END
  END out_flit[105]
  PIN out_flit[106]
    DIRECTION OUTPUT ;
    USE SIGNAL ;
    PORT
      LAYER M5 ;
        RECT  55.536 0 55.56 0.084 ;
    END
  END out_flit[106]
  PIN out_flit[107]
    DIRECTION OUTPUT ;
    USE SIGNAL ;
    PORT
      LAYER M5 ;
        RECT  55.632 0 55.656 0.084 ;
    END
  END out_flit[107]
  PIN out_flit[108]
    DIRECTION OUTPUT ;
    USE SIGNAL ;
    PORT
      LAYER M5 ;
        RECT  55.728 0 55.752 0.084 ;
    END
  END out_flit[108]
  PIN out_flit[109]
    DIRECTION OUTPUT ;
    USE SIGNAL ;
    PORT
      LAYER M5 ;
        RECT  55.824 0 55.848 0.084 ;
    END
  END out_flit[109]
  PIN out_flit[10]
    DIRECTION OUTPUT ;
    USE SIGNAL ;
    PORT
      LAYER M5 ;
        RECT  46.32 0 46.344 0.084 ;
    END
  END out_flit[10]
  PIN out_flit[110]
    DIRECTION OUTPUT ;
    USE SIGNAL ;
    PORT
      LAYER M5 ;
        RECT  55.92 0 55.944 0.084 ;
    END
  END out_flit[110]
  PIN out_flit[111]
    DIRECTION OUTPUT ;
    USE SIGNAL ;
    PORT
      LAYER M5 ;
        RECT  56.016 0 56.04 0.084 ;
    END
  END out_flit[111]
  PIN out_flit[112]
    DIRECTION OUTPUT ;
    USE SIGNAL ;
    PORT
      LAYER M5 ;
        RECT  56.112 0 56.136 0.084 ;
    END
  END out_flit[112]
  PIN out_flit[113]
    DIRECTION OUTPUT ;
    USE SIGNAL ;
    PORT
      LAYER M5 ;
        RECT  56.208 0 56.232 0.084 ;
    END
  END out_flit[113]
  PIN out_flit[114]
    DIRECTION OUTPUT ;
    USE SIGNAL ;
    PORT
      LAYER M5 ;
        RECT  56.304 0 56.328 0.084 ;
    END
  END out_flit[114]
  PIN out_flit[115]
    DIRECTION OUTPUT ;
    USE SIGNAL ;
    PORT
      LAYER M5 ;
        RECT  56.4 0 56.424 0.084 ;
    END
  END out_flit[115]
  PIN out_flit[116]
    DIRECTION OUTPUT ;
    USE SIGNAL ;
    PORT
      LAYER M5 ;
        RECT  56.496 0 56.52 0.084 ;
    END
  END out_flit[116]
  PIN out_flit[117]
    DIRECTION OUTPUT ;
    USE SIGNAL ;
    PORT
      LAYER M5 ;
        RECT  56.592 0 56.616 0.084 ;
    END
  END out_flit[117]
  PIN out_flit[118]
    DIRECTION OUTPUT ;
    USE SIGNAL ;
    PORT
      LAYER M5 ;
        RECT  56.688 0 56.712 0.084 ;
    END
  END out_flit[118]
  PIN out_flit[119]
    DIRECTION OUTPUT ;
    USE SIGNAL ;
    PORT
      LAYER M5 ;
        RECT  56.784 0 56.808 0.084 ;
    END
  END out_flit[119]
  PIN out_flit[11]
    DIRECTION OUTPUT ;
    USE SIGNAL ;
    PORT
      LAYER M5 ;
        RECT  46.416 0 46.44 0.084 ;
    END
  END out_flit[11]
  PIN out_flit[120]
    DIRECTION OUTPUT ;
    USE SIGNAL ;
    PORT
      LAYER M5 ;
        RECT  56.88 0 56.904 0.084 ;
    END
  END out_flit[120]
  PIN out_flit[121]
    DIRECTION OUTPUT ;
    USE SIGNAL ;
    PORT
      LAYER M5 ;
        RECT  56.976 0 57 0.084 ;
    END
  END out_flit[121]
  PIN out_flit[122]
    DIRECTION OUTPUT ;
    USE SIGNAL ;
    PORT
      LAYER M5 ;
        RECT  57.072 0 57.096 0.084 ;
    END
  END out_flit[122]
  PIN out_flit[123]
    DIRECTION OUTPUT ;
    USE SIGNAL ;
    PORT
      LAYER M5 ;
        RECT  57.168 0 57.192 0.084 ;
    END
  END out_flit[123]
  PIN out_flit[124]
    DIRECTION OUTPUT ;
    USE SIGNAL ;
    PORT
      LAYER M5 ;
        RECT  57.264 0 57.288 0.084 ;
    END
  END out_flit[124]
  PIN out_flit[125]
    DIRECTION OUTPUT ;
    USE SIGNAL ;
    PORT
      LAYER M5 ;
        RECT  57.36 0 57.384 0.084 ;
    END
  END out_flit[125]
  PIN out_flit[126]
    DIRECTION OUTPUT ;
    USE SIGNAL ;
    PORT
      LAYER M5 ;
        RECT  57.456 0 57.48 0.084 ;
    END
  END out_flit[126]
  PIN out_flit[127]
    DIRECTION OUTPUT ;
    USE SIGNAL ;
    PORT
      LAYER M5 ;
        RECT  39.12 0 39.144 0.084 ;
    END
  END out_flit[127]
  PIN out_flit[128]
    DIRECTION OUTPUT ;
    USE SIGNAL ;
    PORT
      LAYER M5 ;
        RECT  39.216 0 39.24 0.084 ;
    END
  END out_flit[128]
  PIN out_flit[129]
    DIRECTION OUTPUT ;
    USE SIGNAL ;
    PORT
      LAYER M5 ;
        RECT  39.312 0 39.336 0.084 ;
    END
  END out_flit[129]
  PIN out_flit[12]
    DIRECTION OUTPUT ;
    USE SIGNAL ;
    PORT
      LAYER M5 ;
        RECT  46.512 0 46.536 0.084 ;
    END
  END out_flit[12]
  PIN out_flit[130]
    DIRECTION OUTPUT ;
    USE SIGNAL ;
    PORT
      LAYER M5 ;
        RECT  39.408 0 39.432 0.084 ;
    END
  END out_flit[130]
  PIN out_flit[131]
    DIRECTION OUTPUT ;
    USE SIGNAL ;
    PORT
      LAYER M5 ;
        RECT  39.504 0 39.528 0.084 ;
    END
  END out_flit[131]
  PIN out_flit[132]
    DIRECTION OUTPUT ;
    USE SIGNAL ;
    PORT
      LAYER M5 ;
        RECT  39.6 0 39.624 0.084 ;
    END
  END out_flit[132]
  PIN out_flit[133]
    DIRECTION OUTPUT ;
    USE SIGNAL ;
    PORT
      LAYER M5 ;
        RECT  39.696 0 39.72 0.084 ;
    END
  END out_flit[133]
  PIN out_flit[134]
    DIRECTION OUTPUT ;
    USE SIGNAL ;
    PORT
      LAYER M5 ;
        RECT  39.792 0 39.816 0.084 ;
    END
  END out_flit[134]
  PIN out_flit[135]
    DIRECTION OUTPUT ;
    USE SIGNAL ;
    PORT
      LAYER M5 ;
        RECT  39.888 0 39.912 0.084 ;
    END
  END out_flit[135]
  PIN out_flit[136]
    DIRECTION OUTPUT ;
    USE SIGNAL ;
    PORT
      LAYER M5 ;
        RECT  39.984 0 40.008 0.084 ;
    END
  END out_flit[136]
  PIN out_flit[137]
    DIRECTION OUTPUT ;
    USE SIGNAL ;
    PORT
      LAYER M5 ;
        RECT  40.08 0 40.104 0.084 ;
    END
  END out_flit[137]
  PIN out_flit[138]
    DIRECTION OUTPUT ;
    USE SIGNAL ;
    PORT
      LAYER M5 ;
        RECT  40.176 0 40.2 0.084 ;
    END
  END out_flit[138]
  PIN out_flit[139]
    DIRECTION OUTPUT ;
    USE SIGNAL ;
    PORT
      LAYER M5 ;
        RECT  40.272 0 40.296 0.084 ;
    END
  END out_flit[139]
  PIN out_flit[13]
    DIRECTION OUTPUT ;
    USE SIGNAL ;
    PORT
      LAYER M5 ;
        RECT  46.608 0 46.632 0.084 ;
    END
  END out_flit[13]
  PIN out_flit[140]
    DIRECTION OUTPUT ;
    USE SIGNAL ;
    PORT
      LAYER M5 ;
        RECT  40.368 0 40.392 0.084 ;
    END
  END out_flit[140]
  PIN out_flit[141]
    DIRECTION OUTPUT ;
    USE SIGNAL ;
    PORT
      LAYER M5 ;
        RECT  40.464 0 40.488 0.084 ;
    END
  END out_flit[141]
  PIN out_flit[142]
    DIRECTION OUTPUT ;
    USE SIGNAL ;
    PORT
      LAYER M5 ;
        RECT  40.56 0 40.584 0.084 ;
    END
  END out_flit[142]
  PIN out_flit[143]
    DIRECTION OUTPUT ;
    USE SIGNAL ;
    PORT
      LAYER M5 ;
        RECT  40.656 0 40.68 0.084 ;
    END
  END out_flit[143]
  PIN out_flit[144]
    DIRECTION OUTPUT ;
    USE SIGNAL ;
    PORT
      LAYER M5 ;
        RECT  40.752 0 40.776 0.084 ;
    END
  END out_flit[144]
  PIN out_flit[145]
    DIRECTION OUTPUT ;
    USE SIGNAL ;
    PORT
      LAYER M5 ;
        RECT  40.848 0 40.872 0.084 ;
    END
  END out_flit[145]
  PIN out_flit[146]
    DIRECTION OUTPUT ;
    USE SIGNAL ;
    PORT
      LAYER M5 ;
        RECT  40.944 0 40.968 0.084 ;
    END
  END out_flit[146]
  PIN out_flit[147]
    DIRECTION OUTPUT ;
    USE SIGNAL ;
    PORT
      LAYER M5 ;
        RECT  41.04 0 41.064 0.084 ;
    END
  END out_flit[147]
  PIN out_flit[148]
    DIRECTION OUTPUT ;
    USE SIGNAL ;
    PORT
      LAYER M5 ;
        RECT  41.136 0 41.16 0.084 ;
    END
  END out_flit[148]
  PIN out_flit[149]
    DIRECTION OUTPUT ;
    USE SIGNAL ;
    PORT
      LAYER M5 ;
        RECT  41.232 0 41.256 0.084 ;
    END
  END out_flit[149]
  PIN out_flit[14]
    DIRECTION OUTPUT ;
    USE SIGNAL ;
    PORT
      LAYER M5 ;
        RECT  46.704 0 46.728 0.084 ;
    END
  END out_flit[14]
  PIN out_flit[150]
    DIRECTION OUTPUT ;
    USE SIGNAL ;
    PORT
      LAYER M5 ;
        RECT  41.328 0 41.352 0.084 ;
    END
  END out_flit[150]
  PIN out_flit[151]
    DIRECTION OUTPUT ;
    USE SIGNAL ;
    PORT
      LAYER M5 ;
        RECT  41.424 0 41.448 0.084 ;
    END
  END out_flit[151]
  PIN out_flit[152]
    DIRECTION OUTPUT ;
    USE SIGNAL ;
    PORT
      LAYER M5 ;
        RECT  41.52 0 41.544 0.084 ;
    END
  END out_flit[152]
  PIN out_flit[153]
    DIRECTION OUTPUT ;
    USE SIGNAL ;
    PORT
      LAYER M5 ;
        RECT  41.616 0 41.64 0.084 ;
    END
  END out_flit[153]
  PIN out_flit[154]
    DIRECTION OUTPUT ;
    USE SIGNAL ;
    PORT
      LAYER M5 ;
        RECT  41.712 0 41.736 0.084 ;
    END
  END out_flit[154]
  PIN out_flit[155]
    DIRECTION OUTPUT ;
    USE SIGNAL ;
    PORT
      LAYER M5 ;
        RECT  41.808 0 41.832 0.084 ;
    END
  END out_flit[155]
  PIN out_flit[156]
    DIRECTION OUTPUT ;
    USE SIGNAL ;
    PORT
      LAYER M5 ;
        RECT  41.904 0 41.928 0.084 ;
    END
  END out_flit[156]
  PIN out_flit[157]
    DIRECTION OUTPUT ;
    USE SIGNAL ;
    PORT
      LAYER M5 ;
        RECT  42 0 42.024 0.084 ;
    END
  END out_flit[157]
  PIN out_flit[158]
    DIRECTION OUTPUT ;
    USE SIGNAL ;
    PORT
      LAYER M5 ;
        RECT  42.096 0 42.12 0.084 ;
    END
  END out_flit[158]
  PIN out_flit[159]
    DIRECTION OUTPUT ;
    USE SIGNAL ;
    PORT
      LAYER M5 ;
        RECT  51.408 0 51.432 0.084 ;
    END
  END out_flit[159]
  PIN out_flit[15]
    DIRECTION OUTPUT ;
    USE SIGNAL ;
    PORT
      LAYER M5 ;
        RECT  46.8 0 46.824 0.084 ;
    END
  END out_flit[15]
  PIN out_flit[160]
    DIRECTION OUTPUT ;
    USE SIGNAL ;
    PORT
      LAYER M5 ;
        RECT  51.504 0 51.528 0.084 ;
    END
  END out_flit[160]
  PIN out_flit[161]
    DIRECTION OUTPUT ;
    USE SIGNAL ;
    PORT
      LAYER M5 ;
        RECT  51.6 0 51.624 0.084 ;
    END
  END out_flit[161]
  PIN out_flit[162]
    DIRECTION OUTPUT ;
    USE SIGNAL ;
    PORT
      LAYER M5 ;
        RECT  51.696 0 51.72 0.084 ;
    END
  END out_flit[162]
  PIN out_flit[163]
    DIRECTION OUTPUT ;
    USE SIGNAL ;
    PORT
      LAYER M5 ;
        RECT  51.792 0 51.816 0.084 ;
    END
  END out_flit[163]
  PIN out_flit[164]
    DIRECTION OUTPUT ;
    USE SIGNAL ;
    PORT
      LAYER M5 ;
        RECT  51.888 0 51.912 0.084 ;
    END
  END out_flit[164]
  PIN out_flit[165]
    DIRECTION OUTPUT ;
    USE SIGNAL ;
    PORT
      LAYER M5 ;
        RECT  51.984 0 52.008 0.084 ;
    END
  END out_flit[165]
  PIN out_flit[166]
    DIRECTION OUTPUT ;
    USE SIGNAL ;
    PORT
      LAYER M5 ;
        RECT  52.08 0 52.104 0.084 ;
    END
  END out_flit[166]
  PIN out_flit[167]
    DIRECTION OUTPUT ;
    USE SIGNAL ;
    PORT
      LAYER M5 ;
        RECT  52.176 0 52.2 0.084 ;
    END
  END out_flit[167]
  PIN out_flit[168]
    DIRECTION OUTPUT ;
    USE SIGNAL ;
    PORT
      LAYER M5 ;
        RECT  52.272 0 52.296 0.084 ;
    END
  END out_flit[168]
  PIN out_flit[169]
    DIRECTION OUTPUT ;
    USE SIGNAL ;
    PORT
      LAYER M5 ;
        RECT  52.368 0 52.392 0.084 ;
    END
  END out_flit[169]
  PIN out_flit[16]
    DIRECTION OUTPUT ;
    USE SIGNAL ;
    PORT
      LAYER M5 ;
        RECT  46.896 0 46.92 0.084 ;
    END
  END out_flit[16]
  PIN out_flit[170]
    DIRECTION OUTPUT ;
    USE SIGNAL ;
    PORT
      LAYER M5 ;
        RECT  52.464 0 52.488 0.084 ;
    END
  END out_flit[170]
  PIN out_flit[171]
    DIRECTION OUTPUT ;
    USE SIGNAL ;
    PORT
      LAYER M5 ;
        RECT  52.56 0 52.584 0.084 ;
    END
  END out_flit[171]
  PIN out_flit[172]
    DIRECTION OUTPUT ;
    USE SIGNAL ;
    PORT
      LAYER M5 ;
        RECT  52.656 0 52.68 0.084 ;
    END
  END out_flit[172]
  PIN out_flit[173]
    DIRECTION OUTPUT ;
    USE SIGNAL ;
    PORT
      LAYER M5 ;
        RECT  52.752 0 52.776 0.084 ;
    END
  END out_flit[173]
  PIN out_flit[174]
    DIRECTION OUTPUT ;
    USE SIGNAL ;
    PORT
      LAYER M5 ;
        RECT  52.848 0 52.872 0.084 ;
    END
  END out_flit[174]
  PIN out_flit[175]
    DIRECTION OUTPUT ;
    USE SIGNAL ;
    PORT
      LAYER M5 ;
        RECT  52.944 0 52.968 0.084 ;
    END
  END out_flit[175]
  PIN out_flit[176]
    DIRECTION OUTPUT ;
    USE SIGNAL ;
    PORT
      LAYER M5 ;
        RECT  53.04 0 53.064 0.084 ;
    END
  END out_flit[176]
  PIN out_flit[177]
    DIRECTION OUTPUT ;
    USE SIGNAL ;
    PORT
      LAYER M5 ;
        RECT  53.136 0 53.16 0.084 ;
    END
  END out_flit[177]
  PIN out_flit[178]
    DIRECTION OUTPUT ;
    USE SIGNAL ;
    PORT
      LAYER M5 ;
        RECT  53.232 0 53.256 0.084 ;
    END
  END out_flit[178]
  PIN out_flit[179]
    DIRECTION OUTPUT ;
    USE SIGNAL ;
    PORT
      LAYER M5 ;
        RECT  53.328 0 53.352 0.084 ;
    END
  END out_flit[179]
  PIN out_flit[17]
    DIRECTION OUTPUT ;
    USE SIGNAL ;
    PORT
      LAYER M5 ;
        RECT  46.992 0 47.016 0.084 ;
    END
  END out_flit[17]
  PIN out_flit[180]
    DIRECTION OUTPUT ;
    USE SIGNAL ;
    PORT
      LAYER M5 ;
        RECT  53.424 0 53.448 0.084 ;
    END
  END out_flit[180]
  PIN out_flit[181]
    DIRECTION OUTPUT ;
    USE SIGNAL ;
    PORT
      LAYER M5 ;
        RECT  53.52 0 53.544 0.084 ;
    END
  END out_flit[181]
  PIN out_flit[182]
    DIRECTION OUTPUT ;
    USE SIGNAL ;
    PORT
      LAYER M5 ;
        RECT  53.616 0 53.64 0.084 ;
    END
  END out_flit[182]
  PIN out_flit[183]
    DIRECTION OUTPUT ;
    USE SIGNAL ;
    PORT
      LAYER M5 ;
        RECT  53.712 0 53.736 0.084 ;
    END
  END out_flit[183]
  PIN out_flit[184]
    DIRECTION OUTPUT ;
    USE SIGNAL ;
    PORT
      LAYER M5 ;
        RECT  53.808 0 53.832 0.084 ;
    END
  END out_flit[184]
  PIN out_flit[185]
    DIRECTION OUTPUT ;
    USE SIGNAL ;
    PORT
      LAYER M5 ;
        RECT  53.904 0 53.928 0.084 ;
    END
  END out_flit[185]
  PIN out_flit[186]
    DIRECTION OUTPUT ;
    USE SIGNAL ;
    PORT
      LAYER M5 ;
        RECT  54 0 54.024 0.084 ;
    END
  END out_flit[186]
  PIN out_flit[187]
    DIRECTION OUTPUT ;
    USE SIGNAL ;
    PORT
      LAYER M5 ;
        RECT  54.096 0 54.12 0.084 ;
    END
  END out_flit[187]
  PIN out_flit[188]
    DIRECTION OUTPUT ;
    USE SIGNAL ;
    PORT
      LAYER M5 ;
        RECT  54.192 0 54.216 0.084 ;
    END
  END out_flit[188]
  PIN out_flit[189]
    DIRECTION OUTPUT ;
    USE SIGNAL ;
    PORT
      LAYER M5 ;
        RECT  54.288 0 54.312 0.084 ;
    END
  END out_flit[189]
  PIN out_flit[18]
    DIRECTION OUTPUT ;
    USE SIGNAL ;
    PORT
      LAYER M5 ;
        RECT  47.088 0 47.112 0.084 ;
    END
  END out_flit[18]
  PIN out_flit[190]
    DIRECTION OUTPUT ;
    USE SIGNAL ;
    PORT
      LAYER M5 ;
        RECT  54.384 0 54.408 0.084 ;
    END
  END out_flit[190]
  PIN out_flit[191]
    DIRECTION OUTPUT ;
    USE SIGNAL ;
    PORT
      LAYER M5 ;
        RECT  42.192 0 42.216 0.084 ;
    END
  END out_flit[191]
  PIN out_flit[192]
    DIRECTION OUTPUT ;
    USE SIGNAL ;
    PORT
      LAYER M5 ;
        RECT  42.288 0 42.312 0.084 ;
    END
  END out_flit[192]
  PIN out_flit[193]
    DIRECTION OUTPUT ;
    USE SIGNAL ;
    PORT
      LAYER M5 ;
        RECT  42.384 0 42.408 0.084 ;
    END
  END out_flit[193]
  PIN out_flit[194]
    DIRECTION OUTPUT ;
    USE SIGNAL ;
    PORT
      LAYER M5 ;
        RECT  42.48 0 42.504 0.084 ;
    END
  END out_flit[194]
  PIN out_flit[195]
    DIRECTION OUTPUT ;
    USE SIGNAL ;
    PORT
      LAYER M5 ;
        RECT  42.576 0 42.6 0.084 ;
    END
  END out_flit[195]
  PIN out_flit[196]
    DIRECTION OUTPUT ;
    USE SIGNAL ;
    PORT
      LAYER M5 ;
        RECT  42.672 0 42.696 0.084 ;
    END
  END out_flit[196]
  PIN out_flit[197]
    DIRECTION OUTPUT ;
    USE SIGNAL ;
    PORT
      LAYER M5 ;
        RECT  42.768 0 42.792 0.084 ;
    END
  END out_flit[197]
  PIN out_flit[198]
    DIRECTION OUTPUT ;
    USE SIGNAL ;
    PORT
      LAYER M5 ;
        RECT  42.864 0 42.888 0.084 ;
    END
  END out_flit[198]
  PIN out_flit[199]
    DIRECTION OUTPUT ;
    USE SIGNAL ;
    PORT
      LAYER M5 ;
        RECT  42.96 0 42.984 0.084 ;
    END
  END out_flit[199]
  PIN out_flit[19]
    DIRECTION OUTPUT ;
    USE SIGNAL ;
    PORT
      LAYER M5 ;
        RECT  47.184 0 47.208 0.084 ;
    END
  END out_flit[19]
  PIN out_flit[1]
    DIRECTION OUTPUT ;
    USE SIGNAL ;
    PORT
      LAYER M5 ;
        RECT  45.456 0 45.48 0.084 ;
    END
  END out_flit[1]
  PIN out_flit[200]
    DIRECTION OUTPUT ;
    USE SIGNAL ;
    PORT
      LAYER M5 ;
        RECT  43.056 0 43.08 0.084 ;
    END
  END out_flit[200]
  PIN out_flit[201]
    DIRECTION OUTPUT ;
    USE SIGNAL ;
    PORT
      LAYER M5 ;
        RECT  43.152 0 43.176 0.084 ;
    END
  END out_flit[201]
  PIN out_flit[202]
    DIRECTION OUTPUT ;
    USE SIGNAL ;
    PORT
      LAYER M5 ;
        RECT  43.248 0 43.272 0.084 ;
    END
  END out_flit[202]
  PIN out_flit[203]
    DIRECTION OUTPUT ;
    USE SIGNAL ;
    PORT
      LAYER M5 ;
        RECT  43.344 0 43.368 0.084 ;
    END
  END out_flit[203]
  PIN out_flit[204]
    DIRECTION OUTPUT ;
    USE SIGNAL ;
    PORT
      LAYER M5 ;
        RECT  43.44 0 43.464 0.084 ;
    END
  END out_flit[204]
  PIN out_flit[205]
    DIRECTION OUTPUT ;
    USE SIGNAL ;
    PORT
      LAYER M5 ;
        RECT  43.536 0 43.56 0.084 ;
    END
  END out_flit[205]
  PIN out_flit[206]
    DIRECTION OUTPUT ;
    USE SIGNAL ;
    PORT
      LAYER M5 ;
        RECT  43.632 0 43.656 0.084 ;
    END
  END out_flit[206]
  PIN out_flit[207]
    DIRECTION OUTPUT ;
    USE SIGNAL ;
    PORT
      LAYER M5 ;
        RECT  43.728 0 43.752 0.084 ;
    END
  END out_flit[207]
  PIN out_flit[208]
    DIRECTION OUTPUT ;
    USE SIGNAL ;
    PORT
      LAYER M5 ;
        RECT  43.824 0 43.848 0.084 ;
    END
  END out_flit[208]
  PIN out_flit[209]
    DIRECTION OUTPUT ;
    USE SIGNAL ;
    PORT
      LAYER M5 ;
        RECT  43.92 0 43.944 0.084 ;
    END
  END out_flit[209]
  PIN out_flit[20]
    DIRECTION OUTPUT ;
    USE SIGNAL ;
    PORT
      LAYER M5 ;
        RECT  47.28 0 47.304 0.084 ;
    END
  END out_flit[20]
  PIN out_flit[210]
    DIRECTION OUTPUT ;
    USE SIGNAL ;
    PORT
      LAYER M5 ;
        RECT  44.016 0 44.04 0.084 ;
    END
  END out_flit[210]
  PIN out_flit[211]
    DIRECTION OUTPUT ;
    USE SIGNAL ;
    PORT
      LAYER M5 ;
        RECT  44.112 0 44.136 0.084 ;
    END
  END out_flit[211]
  PIN out_flit[212]
    DIRECTION OUTPUT ;
    USE SIGNAL ;
    PORT
      LAYER M5 ;
        RECT  44.208 0 44.232 0.084 ;
    END
  END out_flit[212]
  PIN out_flit[213]
    DIRECTION OUTPUT ;
    USE SIGNAL ;
    PORT
      LAYER M5 ;
        RECT  44.304 0 44.328 0.084 ;
    END
  END out_flit[213]
  PIN out_flit[214]
    DIRECTION OUTPUT ;
    USE SIGNAL ;
    PORT
      LAYER M5 ;
        RECT  44.4 0 44.424 0.084 ;
    END
  END out_flit[214]
  PIN out_flit[215]
    DIRECTION OUTPUT ;
    USE SIGNAL ;
    PORT
      LAYER M5 ;
        RECT  44.496 0 44.52 0.084 ;
    END
  END out_flit[215]
  PIN out_flit[216]
    DIRECTION OUTPUT ;
    USE SIGNAL ;
    PORT
      LAYER M5 ;
        RECT  44.592 0 44.616 0.084 ;
    END
  END out_flit[216]
  PIN out_flit[217]
    DIRECTION OUTPUT ;
    USE SIGNAL ;
    PORT
      LAYER M5 ;
        RECT  44.688 0 44.712 0.084 ;
    END
  END out_flit[217]
  PIN out_flit[218]
    DIRECTION OUTPUT ;
    USE SIGNAL ;
    PORT
      LAYER M5 ;
        RECT  44.784 0 44.808 0.084 ;
    END
  END out_flit[218]
  PIN out_flit[219]
    DIRECTION OUTPUT ;
    USE SIGNAL ;
    PORT
      LAYER M5 ;
        RECT  44.88 0 44.904 0.084 ;
    END
  END out_flit[219]
  PIN out_flit[21]
    DIRECTION OUTPUT ;
    USE SIGNAL ;
    PORT
      LAYER M5 ;
        RECT  47.376 0 47.4 0.084 ;
    END
  END out_flit[21]
  PIN out_flit[220]
    DIRECTION OUTPUT ;
    USE SIGNAL ;
    PORT
      LAYER M5 ;
        RECT  44.976 0 45 0.084 ;
    END
  END out_flit[220]
  PIN out_flit[221]
    DIRECTION OUTPUT ;
    USE SIGNAL ;
    PORT
      LAYER M5 ;
        RECT  45.072 0 45.096 0.084 ;
    END
  END out_flit[221]
  PIN out_flit[222]
    DIRECTION OUTPUT ;
    USE SIGNAL ;
    PORT
      LAYER M5 ;
        RECT  45.168 0 45.192 0.084 ;
    END
  END out_flit[222]
  PIN out_flit[223]
    DIRECTION OUTPUT ;
    USE SIGNAL ;
    PORT
      LAYER M5 ;
        RECT  58.32 0 58.344 0.084 ;
    END
  END out_flit[223]
  PIN out_flit[224]
    DIRECTION OUTPUT ;
    USE SIGNAL ;
    PORT
      LAYER M5 ;
        RECT  58.416 0 58.44 0.084 ;
    END
  END out_flit[224]
  PIN out_flit[225]
    DIRECTION OUTPUT ;
    USE SIGNAL ;
    PORT
      LAYER M5 ;
        RECT  58.512 0 58.536 0.084 ;
    END
  END out_flit[225]
  PIN out_flit[226]
    DIRECTION OUTPUT ;
    USE SIGNAL ;
    PORT
      LAYER M5 ;
        RECT  58.608 0 58.632 0.084 ;
    END
  END out_flit[226]
  PIN out_flit[227]
    DIRECTION OUTPUT ;
    USE SIGNAL ;
    PORT
      LAYER M5 ;
        RECT  58.704 0 58.728 0.084 ;
    END
  END out_flit[227]
  PIN out_flit[228]
    DIRECTION OUTPUT ;
    USE SIGNAL ;
    PORT
      LAYER M5 ;
        RECT  58.8 0 58.824 0.084 ;
    END
  END out_flit[228]
  PIN out_flit[229]
    DIRECTION OUTPUT ;
    USE SIGNAL ;
    PORT
      LAYER M5 ;
        RECT  58.896 0 58.92 0.084 ;
    END
  END out_flit[229]
  PIN out_flit[22]
    DIRECTION OUTPUT ;
    USE SIGNAL ;
    PORT
      LAYER M5 ;
        RECT  47.472 0 47.496 0.084 ;
    END
  END out_flit[22]
  PIN out_flit[230]
    DIRECTION OUTPUT ;
    USE SIGNAL ;
    PORT
      LAYER M5 ;
        RECT  58.992 0 59.016 0.084 ;
    END
  END out_flit[230]
  PIN out_flit[231]
    DIRECTION OUTPUT ;
    USE SIGNAL ;
    PORT
      LAYER M5 ;
        RECT  59.088 0 59.112 0.084 ;
    END
  END out_flit[231]
  PIN out_flit[232]
    DIRECTION OUTPUT ;
    USE SIGNAL ;
    PORT
      LAYER M5 ;
        RECT  59.184 0 59.208 0.084 ;
    END
  END out_flit[232]
  PIN out_flit[233]
    DIRECTION OUTPUT ;
    USE SIGNAL ;
    PORT
      LAYER M5 ;
        RECT  59.28 0 59.304 0.084 ;
    END
  END out_flit[233]
  PIN out_flit[234]
    DIRECTION OUTPUT ;
    USE SIGNAL ;
    PORT
      LAYER M5 ;
        RECT  59.376 0 59.4 0.084 ;
    END
  END out_flit[234]
  PIN out_flit[235]
    DIRECTION OUTPUT ;
    USE SIGNAL ;
    PORT
      LAYER M5 ;
        RECT  59.472 0 59.496 0.084 ;
    END
  END out_flit[235]
  PIN out_flit[236]
    DIRECTION OUTPUT ;
    USE SIGNAL ;
    PORT
      LAYER M5 ;
        RECT  59.568 0 59.592 0.084 ;
    END
  END out_flit[236]
  PIN out_flit[237]
    DIRECTION OUTPUT ;
    USE SIGNAL ;
    PORT
      LAYER M5 ;
        RECT  59.664 0 59.688 0.084 ;
    END
  END out_flit[237]
  PIN out_flit[238]
    DIRECTION OUTPUT ;
    USE SIGNAL ;
    PORT
      LAYER M5 ;
        RECT  59.76 0 59.784 0.084 ;
    END
  END out_flit[238]
  PIN out_flit[239]
    DIRECTION OUTPUT ;
    USE SIGNAL ;
    PORT
      LAYER M5 ;
        RECT  59.856 0 59.88 0.084 ;
    END
  END out_flit[239]
  PIN out_flit[23]
    DIRECTION OUTPUT ;
    USE SIGNAL ;
    PORT
      LAYER M5 ;
        RECT  47.568 0 47.592 0.084 ;
    END
  END out_flit[23]
  PIN out_flit[240]
    DIRECTION OUTPUT ;
    USE SIGNAL ;
    PORT
      LAYER M5 ;
        RECT  59.952 0 59.976 0.084 ;
    END
  END out_flit[240]
  PIN out_flit[241]
    DIRECTION OUTPUT ;
    USE SIGNAL ;
    PORT
      LAYER M5 ;
        RECT  60.048 0 60.072 0.084 ;
    END
  END out_flit[241]
  PIN out_flit[242]
    DIRECTION OUTPUT ;
    USE SIGNAL ;
    PORT
      LAYER M5 ;
        RECT  60.144 0 60.168 0.084 ;
    END
  END out_flit[242]
  PIN out_flit[243]
    DIRECTION OUTPUT ;
    USE SIGNAL ;
    PORT
      LAYER M5 ;
        RECT  60.24 0 60.264 0.084 ;
    END
  END out_flit[243]
  PIN out_flit[244]
    DIRECTION OUTPUT ;
    USE SIGNAL ;
    PORT
      LAYER M5 ;
        RECT  60.336 0 60.36 0.084 ;
    END
  END out_flit[244]
  PIN out_flit[245]
    DIRECTION OUTPUT ;
    USE SIGNAL ;
    PORT
      LAYER M5 ;
        RECT  60.432 0 60.456 0.084 ;
    END
  END out_flit[245]
  PIN out_flit[246]
    DIRECTION OUTPUT ;
    USE SIGNAL ;
    PORT
      LAYER M5 ;
        RECT  60.528 0 60.552 0.084 ;
    END
  END out_flit[246]
  PIN out_flit[247]
    DIRECTION OUTPUT ;
    USE SIGNAL ;
    PORT
      LAYER M5 ;
        RECT  60.624 0 60.648 0.084 ;
    END
  END out_flit[247]
  PIN out_flit[248]
    DIRECTION OUTPUT ;
    USE SIGNAL ;
    PORT
      LAYER M5 ;
        RECT  60.72 0 60.744 0.084 ;
    END
  END out_flit[248]
  PIN out_flit[249]
    DIRECTION OUTPUT ;
    USE SIGNAL ;
    PORT
      LAYER M5 ;
        RECT  60.816 0 60.84 0.084 ;
    END
  END out_flit[249]
  PIN out_flit[24]
    DIRECTION OUTPUT ;
    USE SIGNAL ;
    PORT
      LAYER M5 ;
        RECT  47.664 0 47.688 0.084 ;
    END
  END out_flit[24]
  PIN out_flit[250]
    DIRECTION OUTPUT ;
    USE SIGNAL ;
    PORT
      LAYER M5 ;
        RECT  60.912 0 60.936 0.084 ;
    END
  END out_flit[250]
  PIN out_flit[251]
    DIRECTION OUTPUT ;
    USE SIGNAL ;
    PORT
      LAYER M5 ;
        RECT  61.008 0 61.032 0.084 ;
    END
  END out_flit[251]
  PIN out_flit[252]
    DIRECTION OUTPUT ;
    USE SIGNAL ;
    PORT
      LAYER M5 ;
        RECT  61.104 0 61.128 0.084 ;
    END
  END out_flit[252]
  PIN out_flit[253]
    DIRECTION OUTPUT ;
    USE SIGNAL ;
    PORT
      LAYER M5 ;
        RECT  61.2 0 61.224 0.084 ;
    END
  END out_flit[253]
  PIN out_flit[254]
    DIRECTION OUTPUT ;
    USE SIGNAL ;
    PORT
      LAYER M5 ;
        RECT  61.296 0 61.32 0.084 ;
    END
  END out_flit[254]
  PIN out_flit[255]
    DIRECTION OUTPUT ;
    USE SIGNAL ;
    PORT
      LAYER M5 ;
        RECT  64.464 0 64.488 0.084 ;
    END
  END out_flit[255]
  PIN out_flit[256]
    DIRECTION OUTPUT ;
    USE SIGNAL ;
    PORT
      LAYER M5 ;
        RECT  64.56 0 64.584 0.084 ;
    END
  END out_flit[256]
  PIN out_flit[257]
    DIRECTION OUTPUT ;
    USE SIGNAL ;
    PORT
      LAYER M5 ;
        RECT  64.656 0 64.68 0.084 ;
    END
  END out_flit[257]
  PIN out_flit[258]
    DIRECTION OUTPUT ;
    USE SIGNAL ;
    PORT
      LAYER M5 ;
        RECT  64.752 0 64.776 0.084 ;
    END
  END out_flit[258]
  PIN out_flit[259]
    DIRECTION OUTPUT ;
    USE SIGNAL ;
    PORT
      LAYER M5 ;
        RECT  64.848 0 64.872 0.084 ;
    END
  END out_flit[259]
  PIN out_flit[25]
    DIRECTION OUTPUT ;
    USE SIGNAL ;
    PORT
      LAYER M5 ;
        RECT  47.76 0 47.784 0.084 ;
    END
  END out_flit[25]
  PIN out_flit[260]
    DIRECTION OUTPUT ;
    USE SIGNAL ;
    PORT
      LAYER M5 ;
        RECT  64.944 0 64.968 0.084 ;
    END
  END out_flit[260]
  PIN out_flit[261]
    DIRECTION OUTPUT ;
    USE SIGNAL ;
    PORT
      LAYER M5 ;
        RECT  65.04 0 65.064 0.084 ;
    END
  END out_flit[261]
  PIN out_flit[262]
    DIRECTION OUTPUT ;
    USE SIGNAL ;
    PORT
      LAYER M5 ;
        RECT  65.136 0 65.16 0.084 ;
    END
  END out_flit[262]
  PIN out_flit[263]
    DIRECTION OUTPUT ;
    USE SIGNAL ;
    PORT
      LAYER M5 ;
        RECT  65.232 0 65.256 0.084 ;
    END
  END out_flit[263]
  PIN out_flit[264]
    DIRECTION OUTPUT ;
    USE SIGNAL ;
    PORT
      LAYER M5 ;
        RECT  65.328 0 65.352 0.084 ;
    END
  END out_flit[264]
  PIN out_flit[265]
    DIRECTION OUTPUT ;
    USE SIGNAL ;
    PORT
      LAYER M5 ;
        RECT  65.424 0 65.448 0.084 ;
    END
  END out_flit[265]
  PIN out_flit[266]
    DIRECTION OUTPUT ;
    USE SIGNAL ;
    PORT
      LAYER M5 ;
        RECT  65.52 0 65.544 0.084 ;
    END
  END out_flit[266]
  PIN out_flit[267]
    DIRECTION OUTPUT ;
    USE SIGNAL ;
    PORT
      LAYER M5 ;
        RECT  65.616 0 65.64 0.084 ;
    END
  END out_flit[267]
  PIN out_flit[268]
    DIRECTION OUTPUT ;
    USE SIGNAL ;
    PORT
      LAYER M5 ;
        RECT  65.712 0 65.736 0.084 ;
    END
  END out_flit[268]
  PIN out_flit[269]
    DIRECTION OUTPUT ;
    USE SIGNAL ;
    PORT
      LAYER M5 ;
        RECT  65.808 0 65.832 0.084 ;
    END
  END out_flit[269]
  PIN out_flit[26]
    DIRECTION OUTPUT ;
    USE SIGNAL ;
    PORT
      LAYER M5 ;
        RECT  47.856 0 47.88 0.084 ;
    END
  END out_flit[26]
  PIN out_flit[270]
    DIRECTION OUTPUT ;
    USE SIGNAL ;
    PORT
      LAYER M5 ;
        RECT  65.904 0 65.928 0.084 ;
    END
  END out_flit[270]
  PIN out_flit[271]
    DIRECTION OUTPUT ;
    USE SIGNAL ;
    PORT
      LAYER M5 ;
        RECT  66 0 66.024 0.084 ;
    END
  END out_flit[271]
  PIN out_flit[272]
    DIRECTION OUTPUT ;
    USE SIGNAL ;
    PORT
      LAYER M5 ;
        RECT  66.096 0 66.12 0.084 ;
    END
  END out_flit[272]
  PIN out_flit[273]
    DIRECTION OUTPUT ;
    USE SIGNAL ;
    PORT
      LAYER M5 ;
        RECT  66.192 0 66.216 0.084 ;
    END
  END out_flit[273]
  PIN out_flit[274]
    DIRECTION OUTPUT ;
    USE SIGNAL ;
    PORT
      LAYER M5 ;
        RECT  66.288 0 66.312 0.084 ;
    END
  END out_flit[274]
  PIN out_flit[275]
    DIRECTION OUTPUT ;
    USE SIGNAL ;
    PORT
      LAYER M5 ;
        RECT  66.384 0 66.408 0.084 ;
    END
  END out_flit[275]
  PIN out_flit[276]
    DIRECTION OUTPUT ;
    USE SIGNAL ;
    PORT
      LAYER M5 ;
        RECT  66.48 0 66.504 0.084 ;
    END
  END out_flit[276]
  PIN out_flit[277]
    DIRECTION OUTPUT ;
    USE SIGNAL ;
    PORT
      LAYER M5 ;
        RECT  66.576 0 66.6 0.084 ;
    END
  END out_flit[277]
  PIN out_flit[278]
    DIRECTION OUTPUT ;
    USE SIGNAL ;
    PORT
      LAYER M5 ;
        RECT  66.672 0 66.696 0.084 ;
    END
  END out_flit[278]
  PIN out_flit[279]
    DIRECTION OUTPUT ;
    USE SIGNAL ;
    PORT
      LAYER M5 ;
        RECT  66.768 0 66.792 0.084 ;
    END
  END out_flit[279]
  PIN out_flit[27]
    DIRECTION OUTPUT ;
    USE SIGNAL ;
    PORT
      LAYER M5 ;
        RECT  47.952 0 47.976 0.084 ;
    END
  END out_flit[27]
  PIN out_flit[280]
    DIRECTION OUTPUT ;
    USE SIGNAL ;
    PORT
      LAYER M5 ;
        RECT  66.864 0 66.888 0.084 ;
    END
  END out_flit[280]
  PIN out_flit[281]
    DIRECTION OUTPUT ;
    USE SIGNAL ;
    PORT
      LAYER M5 ;
        RECT  66.96 0 66.984 0.084 ;
    END
  END out_flit[281]
  PIN out_flit[282]
    DIRECTION OUTPUT ;
    USE SIGNAL ;
    PORT
      LAYER M5 ;
        RECT  67.056 0 67.08 0.084 ;
    END
  END out_flit[282]
  PIN out_flit[283]
    DIRECTION OUTPUT ;
    USE SIGNAL ;
    PORT
      LAYER M5 ;
        RECT  67.152 0 67.176 0.084 ;
    END
  END out_flit[283]
  PIN out_flit[284]
    DIRECTION OUTPUT ;
    USE SIGNAL ;
    PORT
      LAYER M5 ;
        RECT  67.248 0 67.272 0.084 ;
    END
  END out_flit[284]
  PIN out_flit[285]
    DIRECTION OUTPUT ;
    USE SIGNAL ;
    PORT
      LAYER M5 ;
        RECT  67.344 0 67.368 0.084 ;
    END
  END out_flit[285]
  PIN out_flit[286]
    DIRECTION OUTPUT ;
    USE SIGNAL ;
    PORT
      LAYER M5 ;
        RECT  67.44 0 67.464 0.084 ;
    END
  END out_flit[286]
  PIN out_flit[287]
    DIRECTION OUTPUT ;
    USE SIGNAL ;
    PORT
      LAYER M5 ;
        RECT  61.392 0 61.416 0.084 ;
    END
  END out_flit[287]
  PIN out_flit[288]
    DIRECTION OUTPUT ;
    USE SIGNAL ;
    PORT
      LAYER M5 ;
        RECT  61.488 0 61.512 0.084 ;
    END
  END out_flit[288]
  PIN out_flit[289]
    DIRECTION OUTPUT ;
    USE SIGNAL ;
    PORT
      LAYER M5 ;
        RECT  61.584 0 61.608 0.084 ;
    END
  END out_flit[289]
  PIN out_flit[28]
    DIRECTION OUTPUT ;
    USE SIGNAL ;
    PORT
      LAYER M5 ;
        RECT  48.048 0 48.072 0.084 ;
    END
  END out_flit[28]
  PIN out_flit[290]
    DIRECTION OUTPUT ;
    USE SIGNAL ;
    PORT
      LAYER M5 ;
        RECT  61.68 0 61.704 0.084 ;
    END
  END out_flit[290]
  PIN out_flit[291]
    DIRECTION OUTPUT ;
    USE SIGNAL ;
    PORT
      LAYER M5 ;
        RECT  61.776 0 61.8 0.084 ;
    END
  END out_flit[291]
  PIN out_flit[292]
    DIRECTION OUTPUT ;
    USE SIGNAL ;
    PORT
      LAYER M5 ;
        RECT  61.872 0 61.896 0.084 ;
    END
  END out_flit[292]
  PIN out_flit[293]
    DIRECTION OUTPUT ;
    USE SIGNAL ;
    PORT
      LAYER M5 ;
        RECT  61.968 0 61.992 0.084 ;
    END
  END out_flit[293]
  PIN out_flit[294]
    DIRECTION OUTPUT ;
    USE SIGNAL ;
    PORT
      LAYER M5 ;
        RECT  62.064 0 62.088 0.084 ;
    END
  END out_flit[294]
  PIN out_flit[295]
    DIRECTION OUTPUT ;
    USE SIGNAL ;
    PORT
      LAYER M5 ;
        RECT  62.16 0 62.184 0.084 ;
    END
  END out_flit[295]
  PIN out_flit[296]
    DIRECTION OUTPUT ;
    USE SIGNAL ;
    PORT
      LAYER M5 ;
        RECT  62.256 0 62.28 0.084 ;
    END
  END out_flit[296]
  PIN out_flit[297]
    DIRECTION OUTPUT ;
    USE SIGNAL ;
    PORT
      LAYER M5 ;
        RECT  62.352 0 62.376 0.084 ;
    END
  END out_flit[297]
  PIN out_flit[298]
    DIRECTION OUTPUT ;
    USE SIGNAL ;
    PORT
      LAYER M5 ;
        RECT  62.448 0 62.472 0.084 ;
    END
  END out_flit[298]
  PIN out_flit[299]
    DIRECTION OUTPUT ;
    USE SIGNAL ;
    PORT
      LAYER M5 ;
        RECT  62.544 0 62.568 0.084 ;
    END
  END out_flit[299]
  PIN out_flit[29]
    DIRECTION OUTPUT ;
    USE SIGNAL ;
    PORT
      LAYER M5 ;
        RECT  48.144 0 48.168 0.084 ;
    END
  END out_flit[29]
  PIN out_flit[2]
    DIRECTION OUTPUT ;
    USE SIGNAL ;
    PORT
      LAYER M5 ;
        RECT  45.552 0 45.576 0.084 ;
    END
  END out_flit[2]
  PIN out_flit[300]
    DIRECTION OUTPUT ;
    USE SIGNAL ;
    PORT
      LAYER M5 ;
        RECT  62.64 0 62.664 0.084 ;
    END
  END out_flit[300]
  PIN out_flit[301]
    DIRECTION OUTPUT ;
    USE SIGNAL ;
    PORT
      LAYER M5 ;
        RECT  62.736 0 62.76 0.084 ;
    END
  END out_flit[301]
  PIN out_flit[302]
    DIRECTION OUTPUT ;
    USE SIGNAL ;
    PORT
      LAYER M5 ;
        RECT  62.832 0 62.856 0.084 ;
    END
  END out_flit[302]
  PIN out_flit[303]
    DIRECTION OUTPUT ;
    USE SIGNAL ;
    PORT
      LAYER M5 ;
        RECT  62.928 0 62.952 0.084 ;
    END
  END out_flit[303]
  PIN out_flit[304]
    DIRECTION OUTPUT ;
    USE SIGNAL ;
    PORT
      LAYER M5 ;
        RECT  63.024 0 63.048 0.084 ;
    END
  END out_flit[304]
  PIN out_flit[305]
    DIRECTION OUTPUT ;
    USE SIGNAL ;
    PORT
      LAYER M5 ;
        RECT  63.12 0 63.144 0.084 ;
    END
  END out_flit[305]
  PIN out_flit[306]
    DIRECTION OUTPUT ;
    USE SIGNAL ;
    PORT
      LAYER M5 ;
        RECT  63.216 0 63.24 0.084 ;
    END
  END out_flit[306]
  PIN out_flit[307]
    DIRECTION OUTPUT ;
    USE SIGNAL ;
    PORT
      LAYER M5 ;
        RECT  63.312 0 63.336 0.084 ;
    END
  END out_flit[307]
  PIN out_flit[308]
    DIRECTION OUTPUT ;
    USE SIGNAL ;
    PORT
      LAYER M5 ;
        RECT  63.408 0 63.432 0.084 ;
    END
  END out_flit[308]
  PIN out_flit[309]
    DIRECTION OUTPUT ;
    USE SIGNAL ;
    PORT
      LAYER M5 ;
        RECT  63.504 0 63.528 0.084 ;
    END
  END out_flit[309]
  PIN out_flit[30]
    DIRECTION OUTPUT ;
    USE SIGNAL ;
    PORT
      LAYER M5 ;
        RECT  48.24 0 48.264 0.084 ;
    END
  END out_flit[30]
  PIN out_flit[310]
    DIRECTION OUTPUT ;
    USE SIGNAL ;
    PORT
      LAYER M5 ;
        RECT  63.6 0 63.624 0.084 ;
    END
  END out_flit[310]
  PIN out_flit[311]
    DIRECTION OUTPUT ;
    USE SIGNAL ;
    PORT
      LAYER M5 ;
        RECT  63.696 0 63.72 0.084 ;
    END
  END out_flit[311]
  PIN out_flit[312]
    DIRECTION OUTPUT ;
    USE SIGNAL ;
    PORT
      LAYER M5 ;
        RECT  63.792 0 63.816 0.084 ;
    END
  END out_flit[312]
  PIN out_flit[313]
    DIRECTION OUTPUT ;
    USE SIGNAL ;
    PORT
      LAYER M5 ;
        RECT  63.888 0 63.912 0.084 ;
    END
  END out_flit[313]
  PIN out_flit[314]
    DIRECTION OUTPUT ;
    USE SIGNAL ;
    PORT
      LAYER M5 ;
        RECT  63.984 0 64.008 0.084 ;
    END
  END out_flit[314]
  PIN out_flit[315]
    DIRECTION OUTPUT ;
    USE SIGNAL ;
    PORT
      LAYER M5 ;
        RECT  64.08 0 64.104 0.084 ;
    END
  END out_flit[315]
  PIN out_flit[316]
    DIRECTION OUTPUT ;
    USE SIGNAL ;
    PORT
      LAYER M5 ;
        RECT  64.176 0 64.2 0.084 ;
    END
  END out_flit[316]
  PIN out_flit[317]
    DIRECTION OUTPUT ;
    USE SIGNAL ;
    PORT
      LAYER M5 ;
        RECT  64.272 0 64.296 0.084 ;
    END
  END out_flit[317]
  PIN out_flit[318]
    DIRECTION OUTPUT ;
    USE SIGNAL ;
    PORT
      LAYER M5 ;
        RECT  64.368 0 64.392 0.084 ;
    END
  END out_flit[318]
  PIN out_flit[319]
    DIRECTION OUTPUT ;
    USE SIGNAL ;
    PORT
      LAYER M5 ;
        RECT  73.68 0 73.704 0.084 ;
    END
  END out_flit[319]
  PIN out_flit[31]
    DIRECTION OUTPUT ;
    USE SIGNAL ;
    PORT
      LAYER M5 ;
        RECT  48.336 0 48.36 0.084 ;
    END
  END out_flit[31]
  PIN out_flit[320]
    DIRECTION OUTPUT ;
    USE SIGNAL ;
    PORT
      LAYER M5 ;
        RECT  73.776 0 73.8 0.084 ;
    END
  END out_flit[320]
  PIN out_flit[321]
    DIRECTION OUTPUT ;
    USE SIGNAL ;
    PORT
      LAYER M5 ;
        RECT  73.872 0 73.896 0.084 ;
    END
  END out_flit[321]
  PIN out_flit[322]
    DIRECTION OUTPUT ;
    USE SIGNAL ;
    PORT
      LAYER M5 ;
        RECT  73.968 0 73.992 0.084 ;
    END
  END out_flit[322]
  PIN out_flit[323]
    DIRECTION OUTPUT ;
    USE SIGNAL ;
    PORT
      LAYER M5 ;
        RECT  74.064 0 74.088 0.084 ;
    END
  END out_flit[323]
  PIN out_flit[324]
    DIRECTION OUTPUT ;
    USE SIGNAL ;
    PORT
      LAYER M5 ;
        RECT  74.16 0 74.184 0.084 ;
    END
  END out_flit[324]
  PIN out_flit[325]
    DIRECTION OUTPUT ;
    USE SIGNAL ;
    PORT
      LAYER M5 ;
        RECT  74.256 0 74.28 0.084 ;
    END
  END out_flit[325]
  PIN out_flit[326]
    DIRECTION OUTPUT ;
    USE SIGNAL ;
    PORT
      LAYER M5 ;
        RECT  74.352 0 74.376 0.084 ;
    END
  END out_flit[326]
  PIN out_flit[327]
    DIRECTION OUTPUT ;
    USE SIGNAL ;
    PORT
      LAYER M5 ;
        RECT  74.448 0 74.472 0.084 ;
    END
  END out_flit[327]
  PIN out_flit[328]
    DIRECTION OUTPUT ;
    USE SIGNAL ;
    PORT
      LAYER M5 ;
        RECT  74.544 0 74.568 0.084 ;
    END
  END out_flit[328]
  PIN out_flit[329]
    DIRECTION OUTPUT ;
    USE SIGNAL ;
    PORT
      LAYER M5 ;
        RECT  74.64 0 74.664 0.084 ;
    END
  END out_flit[329]
  PIN out_flit[32]
    DIRECTION OUTPUT ;
    USE SIGNAL ;
    PORT
      LAYER M5 ;
        RECT  48.432 0 48.456 0.084 ;
    END
  END out_flit[32]
  PIN out_flit[330]
    DIRECTION OUTPUT ;
    USE SIGNAL ;
    PORT
      LAYER M5 ;
        RECT  74.736 0 74.76 0.084 ;
    END
  END out_flit[330]
  PIN out_flit[331]
    DIRECTION OUTPUT ;
    USE SIGNAL ;
    PORT
      LAYER M5 ;
        RECT  74.832 0 74.856 0.084 ;
    END
  END out_flit[331]
  PIN out_flit[332]
    DIRECTION OUTPUT ;
    USE SIGNAL ;
    PORT
      LAYER M5 ;
        RECT  74.928 0 74.952 0.084 ;
    END
  END out_flit[332]
  PIN out_flit[333]
    DIRECTION OUTPUT ;
    USE SIGNAL ;
    PORT
      LAYER M5 ;
        RECT  75.024 0 75.048 0.084 ;
    END
  END out_flit[333]
  PIN out_flit[334]
    DIRECTION OUTPUT ;
    USE SIGNAL ;
    PORT
      LAYER M5 ;
        RECT  75.12 0 75.144 0.084 ;
    END
  END out_flit[334]
  PIN out_flit[335]
    DIRECTION OUTPUT ;
    USE SIGNAL ;
    PORT
      LAYER M5 ;
        RECT  75.216 0 75.24 0.084 ;
    END
  END out_flit[335]
  PIN out_flit[336]
    DIRECTION OUTPUT ;
    USE SIGNAL ;
    PORT
      LAYER M5 ;
        RECT  75.312 0 75.336 0.084 ;
    END
  END out_flit[336]
  PIN out_flit[337]
    DIRECTION OUTPUT ;
    USE SIGNAL ;
    PORT
      LAYER M5 ;
        RECT  75.408 0 75.432 0.084 ;
    END
  END out_flit[337]
  PIN out_flit[338]
    DIRECTION OUTPUT ;
    USE SIGNAL ;
    PORT
      LAYER M5 ;
        RECT  75.504 0 75.528 0.084 ;
    END
  END out_flit[338]
  PIN out_flit[339]
    DIRECTION OUTPUT ;
    USE SIGNAL ;
    PORT
      LAYER M5 ;
        RECT  75.6 0 75.624 0.084 ;
    END
  END out_flit[339]
  PIN out_flit[33]
    DIRECTION OUTPUT ;
    USE SIGNAL ;
    PORT
      LAYER M5 ;
        RECT  48.528 0 48.552 0.084 ;
    END
  END out_flit[33]
  PIN out_flit[340]
    DIRECTION OUTPUT ;
    USE SIGNAL ;
    PORT
      LAYER M5 ;
        RECT  75.696 0 75.72 0.084 ;
    END
  END out_flit[340]
  PIN out_flit[341]
    DIRECTION OUTPUT ;
    USE SIGNAL ;
    PORT
      LAYER M5 ;
        RECT  75.792 0 75.816 0.084 ;
    END
  END out_flit[341]
  PIN out_flit[342]
    DIRECTION OUTPUT ;
    USE SIGNAL ;
    PORT
      LAYER M5 ;
        RECT  75.888 0 75.912 0.084 ;
    END
  END out_flit[342]
  PIN out_flit[343]
    DIRECTION OUTPUT ;
    USE SIGNAL ;
    PORT
      LAYER M5 ;
        RECT  75.984 0 76.008 0.084 ;
    END
  END out_flit[343]
  PIN out_flit[344]
    DIRECTION OUTPUT ;
    USE SIGNAL ;
    PORT
      LAYER M5 ;
        RECT  76.08 0 76.104 0.084 ;
    END
  END out_flit[344]
  PIN out_flit[345]
    DIRECTION OUTPUT ;
    USE SIGNAL ;
    PORT
      LAYER M5 ;
        RECT  76.176 0 76.2 0.084 ;
    END
  END out_flit[345]
  PIN out_flit[346]
    DIRECTION OUTPUT ;
    USE SIGNAL ;
    PORT
      LAYER M5 ;
        RECT  76.272 0 76.296 0.084 ;
    END
  END out_flit[346]
  PIN out_flit[347]
    DIRECTION OUTPUT ;
    USE SIGNAL ;
    PORT
      LAYER M5 ;
        RECT  76.368 0 76.392 0.084 ;
    END
  END out_flit[347]
  PIN out_flit[348]
    DIRECTION OUTPUT ;
    USE SIGNAL ;
    PORT
      LAYER M5 ;
        RECT  76.464 0 76.488 0.084 ;
    END
  END out_flit[348]
  PIN out_flit[349]
    DIRECTION OUTPUT ;
    USE SIGNAL ;
    PORT
      LAYER M5 ;
        RECT  76.56 0 76.584 0.084 ;
    END
  END out_flit[349]
  PIN out_flit[34]
    DIRECTION OUTPUT ;
    USE SIGNAL ;
    PORT
      LAYER M5 ;
        RECT  48.624 0 48.648 0.084 ;
    END
  END out_flit[34]
  PIN out_flit[350]
    DIRECTION OUTPUT ;
    USE SIGNAL ;
    PORT
      LAYER M5 ;
        RECT  76.656 0 76.68 0.084 ;
    END
  END out_flit[350]
  PIN out_flit[351]
    DIRECTION OUTPUT ;
    USE SIGNAL ;
    PORT
      LAYER M5 ;
        RECT  67.536 0 67.56 0.084 ;
    END
  END out_flit[351]
  PIN out_flit[352]
    DIRECTION OUTPUT ;
    USE SIGNAL ;
    PORT
      LAYER M5 ;
        RECT  67.632 0 67.656 0.084 ;
    END
  END out_flit[352]
  PIN out_flit[353]
    DIRECTION OUTPUT ;
    USE SIGNAL ;
    PORT
      LAYER M5 ;
        RECT  67.728 0 67.752 0.084 ;
    END
  END out_flit[353]
  PIN out_flit[354]
    DIRECTION OUTPUT ;
    USE SIGNAL ;
    PORT
      LAYER M5 ;
        RECT  67.824 0 67.848 0.084 ;
    END
  END out_flit[354]
  PIN out_flit[355]
    DIRECTION OUTPUT ;
    USE SIGNAL ;
    PORT
      LAYER M5 ;
        RECT  67.92 0 67.944 0.084 ;
    END
  END out_flit[355]
  PIN out_flit[356]
    DIRECTION OUTPUT ;
    USE SIGNAL ;
    PORT
      LAYER M5 ;
        RECT  68.016 0 68.04 0.084 ;
    END
  END out_flit[356]
  PIN out_flit[357]
    DIRECTION OUTPUT ;
    USE SIGNAL ;
    PORT
      LAYER M5 ;
        RECT  68.112 0 68.136 0.084 ;
    END
  END out_flit[357]
  PIN out_flit[358]
    DIRECTION OUTPUT ;
    USE SIGNAL ;
    PORT
      LAYER M5 ;
        RECT  68.208 0 68.232 0.084 ;
    END
  END out_flit[358]
  PIN out_flit[359]
    DIRECTION OUTPUT ;
    USE SIGNAL ;
    PORT
      LAYER M5 ;
        RECT  68.304 0 68.328 0.084 ;
    END
  END out_flit[359]
  PIN out_flit[35]
    DIRECTION OUTPUT ;
    USE SIGNAL ;
    PORT
      LAYER M5 ;
        RECT  48.72 0 48.744 0.084 ;
    END
  END out_flit[35]
  PIN out_flit[360]
    DIRECTION OUTPUT ;
    USE SIGNAL ;
    PORT
      LAYER M5 ;
        RECT  68.4 0 68.424 0.084 ;
    END
  END out_flit[360]
  PIN out_flit[361]
    DIRECTION OUTPUT ;
    USE SIGNAL ;
    PORT
      LAYER M5 ;
        RECT  68.496 0 68.52 0.084 ;
    END
  END out_flit[361]
  PIN out_flit[362]
    DIRECTION OUTPUT ;
    USE SIGNAL ;
    PORT
      LAYER M5 ;
        RECT  68.592 0 68.616 0.084 ;
    END
  END out_flit[362]
  PIN out_flit[363]
    DIRECTION OUTPUT ;
    USE SIGNAL ;
    PORT
      LAYER M5 ;
        RECT  68.688 0 68.712 0.084 ;
    END
  END out_flit[363]
  PIN out_flit[364]
    DIRECTION OUTPUT ;
    USE SIGNAL ;
    PORT
      LAYER M5 ;
        RECT  68.784 0 68.808 0.084 ;
    END
  END out_flit[364]
  PIN out_flit[365]
    DIRECTION OUTPUT ;
    USE SIGNAL ;
    PORT
      LAYER M5 ;
        RECT  68.88 0 68.904 0.084 ;
    END
  END out_flit[365]
  PIN out_flit[366]
    DIRECTION OUTPUT ;
    USE SIGNAL ;
    PORT
      LAYER M5 ;
        RECT  68.976 0 69 0.084 ;
    END
  END out_flit[366]
  PIN out_flit[367]
    DIRECTION OUTPUT ;
    USE SIGNAL ;
    PORT
      LAYER M5 ;
        RECT  69.072 0 69.096 0.084 ;
    END
  END out_flit[367]
  PIN out_flit[368]
    DIRECTION OUTPUT ;
    USE SIGNAL ;
    PORT
      LAYER M5 ;
        RECT  69.168 0 69.192 0.084 ;
    END
  END out_flit[368]
  PIN out_flit[369]
    DIRECTION OUTPUT ;
    USE SIGNAL ;
    PORT
      LAYER M5 ;
        RECT  69.264 0 69.288 0.084 ;
    END
  END out_flit[369]
  PIN out_flit[36]
    DIRECTION OUTPUT ;
    USE SIGNAL ;
    PORT
      LAYER M5 ;
        RECT  48.816 0 48.84 0.084 ;
    END
  END out_flit[36]
  PIN out_flit[370]
    DIRECTION OUTPUT ;
    USE SIGNAL ;
    PORT
      LAYER M5 ;
        RECT  69.36 0 69.384 0.084 ;
    END
  END out_flit[370]
  PIN out_flit[371]
    DIRECTION OUTPUT ;
    USE SIGNAL ;
    PORT
      LAYER M5 ;
        RECT  69.456 0 69.48 0.084 ;
    END
  END out_flit[371]
  PIN out_flit[372]
    DIRECTION OUTPUT ;
    USE SIGNAL ;
    PORT
      LAYER M5 ;
        RECT  69.552 0 69.576 0.084 ;
    END
  END out_flit[372]
  PIN out_flit[373]
    DIRECTION OUTPUT ;
    USE SIGNAL ;
    PORT
      LAYER M5 ;
        RECT  69.648 0 69.672 0.084 ;
    END
  END out_flit[373]
  PIN out_flit[374]
    DIRECTION OUTPUT ;
    USE SIGNAL ;
    PORT
      LAYER M5 ;
        RECT  69.744 0 69.768 0.084 ;
    END
  END out_flit[374]
  PIN out_flit[375]
    DIRECTION OUTPUT ;
    USE SIGNAL ;
    PORT
      LAYER M5 ;
        RECT  69.84 0 69.864 0.084 ;
    END
  END out_flit[375]
  PIN out_flit[376]
    DIRECTION OUTPUT ;
    USE SIGNAL ;
    PORT
      LAYER M5 ;
        RECT  69.936 0 69.96 0.084 ;
    END
  END out_flit[376]
  PIN out_flit[377]
    DIRECTION OUTPUT ;
    USE SIGNAL ;
    PORT
      LAYER M5 ;
        RECT  70.032 0 70.056 0.084 ;
    END
  END out_flit[377]
  PIN out_flit[378]
    DIRECTION OUTPUT ;
    USE SIGNAL ;
    PORT
      LAYER M5 ;
        RECT  70.128 0 70.152 0.084 ;
    END
  END out_flit[378]
  PIN out_flit[379]
    DIRECTION OUTPUT ;
    USE SIGNAL ;
    PORT
      LAYER M5 ;
        RECT  70.224 0 70.248 0.084 ;
    END
  END out_flit[379]
  PIN out_flit[37]
    DIRECTION OUTPUT ;
    USE SIGNAL ;
    PORT
      LAYER M5 ;
        RECT  48.912 0 48.936 0.084 ;
    END
  END out_flit[37]
  PIN out_flit[380]
    DIRECTION OUTPUT ;
    USE SIGNAL ;
    PORT
      LAYER M5 ;
        RECT  70.32 0 70.344 0.084 ;
    END
  END out_flit[380]
  PIN out_flit[381]
    DIRECTION OUTPUT ;
    USE SIGNAL ;
    PORT
      LAYER M5 ;
        RECT  70.416 0 70.44 0.084 ;
    END
  END out_flit[381]
  PIN out_flit[382]
    DIRECTION OUTPUT ;
    USE SIGNAL ;
    PORT
      LAYER M5 ;
        RECT  70.512 0 70.536 0.084 ;
    END
  END out_flit[382]
  PIN out_flit[383]
    DIRECTION OUTPUT ;
    USE SIGNAL ;
    PORT
      LAYER M5 ;
        RECT  83.664 0 83.688 0.084 ;
    END
  END out_flit[383]
  PIN out_flit[384]
    DIRECTION OUTPUT ;
    USE SIGNAL ;
    PORT
      LAYER M5 ;
        RECT  83.76 0 83.784 0.084 ;
    END
  END out_flit[384]
  PIN out_flit[385]
    DIRECTION OUTPUT ;
    USE SIGNAL ;
    PORT
      LAYER M5 ;
        RECT  83.856 0 83.88 0.084 ;
    END
  END out_flit[385]
  PIN out_flit[386]
    DIRECTION OUTPUT ;
    USE SIGNAL ;
    PORT
      LAYER M5 ;
        RECT  83.952 0 83.976 0.084 ;
    END
  END out_flit[386]
  PIN out_flit[387]
    DIRECTION OUTPUT ;
    USE SIGNAL ;
    PORT
      LAYER M5 ;
        RECT  84.048 0 84.072 0.084 ;
    END
  END out_flit[387]
  PIN out_flit[388]
    DIRECTION OUTPUT ;
    USE SIGNAL ;
    PORT
      LAYER M5 ;
        RECT  84.144 0 84.168 0.084 ;
    END
  END out_flit[388]
  PIN out_flit[389]
    DIRECTION OUTPUT ;
    USE SIGNAL ;
    PORT
      LAYER M5 ;
        RECT  84.24 0 84.264 0.084 ;
    END
  END out_flit[389]
  PIN out_flit[38]
    DIRECTION OUTPUT ;
    USE SIGNAL ;
    PORT
      LAYER M5 ;
        RECT  49.008 0 49.032 0.084 ;
    END
  END out_flit[38]
  PIN out_flit[390]
    DIRECTION OUTPUT ;
    USE SIGNAL ;
    PORT
      LAYER M5 ;
        RECT  84.336 0 84.36 0.084 ;
    END
  END out_flit[390]
  PIN out_flit[391]
    DIRECTION OUTPUT ;
    USE SIGNAL ;
    PORT
      LAYER M5 ;
        RECT  84.432 0 84.456 0.084 ;
    END
  END out_flit[391]
  PIN out_flit[392]
    DIRECTION OUTPUT ;
    USE SIGNAL ;
    PORT
      LAYER M5 ;
        RECT  84.528 0 84.552 0.084 ;
    END
  END out_flit[392]
  PIN out_flit[393]
    DIRECTION OUTPUT ;
    USE SIGNAL ;
    PORT
      LAYER M5 ;
        RECT  84.624 0 84.648 0.084 ;
    END
  END out_flit[393]
  PIN out_flit[394]
    DIRECTION OUTPUT ;
    USE SIGNAL ;
    PORT
      LAYER M5 ;
        RECT  84.72 0 84.744 0.084 ;
    END
  END out_flit[394]
  PIN out_flit[395]
    DIRECTION OUTPUT ;
    USE SIGNAL ;
    PORT
      LAYER M5 ;
        RECT  84.816 0 84.84 0.084 ;
    END
  END out_flit[395]
  PIN out_flit[396]
    DIRECTION OUTPUT ;
    USE SIGNAL ;
    PORT
      LAYER M5 ;
        RECT  84.912 0 84.936 0.084 ;
    END
  END out_flit[396]
  PIN out_flit[397]
    DIRECTION OUTPUT ;
    USE SIGNAL ;
    PORT
      LAYER M5 ;
        RECT  85.008 0 85.032 0.084 ;
    END
  END out_flit[397]
  PIN out_flit[398]
    DIRECTION OUTPUT ;
    USE SIGNAL ;
    PORT
      LAYER M5 ;
        RECT  85.104 0 85.128 0.084 ;
    END
  END out_flit[398]
  PIN out_flit[399]
    DIRECTION OUTPUT ;
    USE SIGNAL ;
    PORT
      LAYER M5 ;
        RECT  85.2 0 85.224 0.084 ;
    END
  END out_flit[399]
  PIN out_flit[39]
    DIRECTION OUTPUT ;
    USE SIGNAL ;
    PORT
      LAYER M5 ;
        RECT  49.104 0 49.128 0.084 ;
    END
  END out_flit[39]
  PIN out_flit[3]
    DIRECTION OUTPUT ;
    USE SIGNAL ;
    PORT
      LAYER M5 ;
        RECT  45.648 0 45.672 0.084 ;
    END
  END out_flit[3]
  PIN out_flit[400]
    DIRECTION OUTPUT ;
    USE SIGNAL ;
    PORT
      LAYER M5 ;
        RECT  85.296 0 85.32 0.084 ;
    END
  END out_flit[400]
  PIN out_flit[401]
    DIRECTION OUTPUT ;
    USE SIGNAL ;
    PORT
      LAYER M5 ;
        RECT  85.392 0 85.416 0.084 ;
    END
  END out_flit[401]
  PIN out_flit[402]
    DIRECTION OUTPUT ;
    USE SIGNAL ;
    PORT
      LAYER M5 ;
        RECT  85.488 0 85.512 0.084 ;
    END
  END out_flit[402]
  PIN out_flit[403]
    DIRECTION OUTPUT ;
    USE SIGNAL ;
    PORT
      LAYER M5 ;
        RECT  85.584 0 85.608 0.084 ;
    END
  END out_flit[403]
  PIN out_flit[404]
    DIRECTION OUTPUT ;
    USE SIGNAL ;
    PORT
      LAYER M5 ;
        RECT  85.68 0 85.704 0.084 ;
    END
  END out_flit[404]
  PIN out_flit[405]
    DIRECTION OUTPUT ;
    USE SIGNAL ;
    PORT
      LAYER M5 ;
        RECT  85.776 0 85.8 0.084 ;
    END
  END out_flit[405]
  PIN out_flit[406]
    DIRECTION OUTPUT ;
    USE SIGNAL ;
    PORT
      LAYER M5 ;
        RECT  85.872 0 85.896 0.084 ;
    END
  END out_flit[406]
  PIN out_flit[407]
    DIRECTION OUTPUT ;
    USE SIGNAL ;
    PORT
      LAYER M5 ;
        RECT  85.968 0 85.992 0.084 ;
    END
  END out_flit[407]
  PIN out_flit[408]
    DIRECTION OUTPUT ;
    USE SIGNAL ;
    PORT
      LAYER M5 ;
        RECT  86.064 0 86.088 0.084 ;
    END
  END out_flit[408]
  PIN out_flit[409]
    DIRECTION OUTPUT ;
    USE SIGNAL ;
    PORT
      LAYER M5 ;
        RECT  86.16 0 86.184 0.084 ;
    END
  END out_flit[409]
  PIN out_flit[40]
    DIRECTION OUTPUT ;
    USE SIGNAL ;
    PORT
      LAYER M5 ;
        RECT  49.2 0 49.224 0.084 ;
    END
  END out_flit[40]
  PIN out_flit[410]
    DIRECTION OUTPUT ;
    USE SIGNAL ;
    PORT
      LAYER M5 ;
        RECT  86.256 0 86.28 0.084 ;
    END
  END out_flit[410]
  PIN out_flit[411]
    DIRECTION OUTPUT ;
    USE SIGNAL ;
    PORT
      LAYER M5 ;
        RECT  86.352 0 86.376 0.084 ;
    END
  END out_flit[411]
  PIN out_flit[412]
    DIRECTION OUTPUT ;
    USE SIGNAL ;
    PORT
      LAYER M5 ;
        RECT  86.448 0 86.472 0.084 ;
    END
  END out_flit[412]
  PIN out_flit[413]
    DIRECTION OUTPUT ;
    USE SIGNAL ;
    PORT
      LAYER M5 ;
        RECT  86.544 0 86.568 0.084 ;
    END
  END out_flit[413]
  PIN out_flit[414]
    DIRECTION OUTPUT ;
    USE SIGNAL ;
    PORT
      LAYER M5 ;
        RECT  86.64 0 86.664 0.084 ;
    END
  END out_flit[414]
  PIN out_flit[415]
    DIRECTION OUTPUT ;
    USE SIGNAL ;
    PORT
      LAYER M5 ;
        RECT  86.736 0 86.76 0.084 ;
    END
  END out_flit[415]
  PIN out_flit[416]
    DIRECTION OUTPUT ;
    USE SIGNAL ;
    PORT
      LAYER M5 ;
        RECT  86.832 0 86.856 0.084 ;
    END
  END out_flit[416]
  PIN out_flit[417]
    DIRECTION OUTPUT ;
    USE SIGNAL ;
    PORT
      LAYER M5 ;
        RECT  86.928 0 86.952 0.084 ;
    END
  END out_flit[417]
  PIN out_flit[418]
    DIRECTION OUTPUT ;
    USE SIGNAL ;
    PORT
      LAYER M5 ;
        RECT  87.024 0 87.048 0.084 ;
    END
  END out_flit[418]
  PIN out_flit[419]
    DIRECTION OUTPUT ;
    USE SIGNAL ;
    PORT
      LAYER M5 ;
        RECT  87.12 0 87.144 0.084 ;
    END
  END out_flit[419]
  PIN out_flit[41]
    DIRECTION OUTPUT ;
    USE SIGNAL ;
    PORT
      LAYER M5 ;
        RECT  49.296 0 49.32 0.084 ;
    END
  END out_flit[41]
  PIN out_flit[420]
    DIRECTION OUTPUT ;
    USE SIGNAL ;
    PORT
      LAYER M5 ;
        RECT  87.216 0 87.24 0.084 ;
    END
  END out_flit[420]
  PIN out_flit[421]
    DIRECTION OUTPUT ;
    USE SIGNAL ;
    PORT
      LAYER M5 ;
        RECT  87.312 0 87.336 0.084 ;
    END
  END out_flit[421]
  PIN out_flit[422]
    DIRECTION OUTPUT ;
    USE SIGNAL ;
    PORT
      LAYER M5 ;
        RECT  87.408 0 87.432 0.084 ;
    END
  END out_flit[422]
  PIN out_flit[423]
    DIRECTION OUTPUT ;
    USE SIGNAL ;
    PORT
      LAYER M5 ;
        RECT  87.504 0 87.528 0.084 ;
    END
  END out_flit[423]
  PIN out_flit[424]
    DIRECTION OUTPUT ;
    USE SIGNAL ;
    PORT
      LAYER M5 ;
        RECT  87.6 0 87.624 0.084 ;
    END
  END out_flit[424]
  PIN out_flit[425]
    DIRECTION OUTPUT ;
    USE SIGNAL ;
    PORT
      LAYER M5 ;
        RECT  87.696 0 87.72 0.084 ;
    END
  END out_flit[425]
  PIN out_flit[426]
    DIRECTION OUTPUT ;
    USE SIGNAL ;
    PORT
      LAYER M5 ;
        RECT  87.792 0 87.816 0.084 ;
    END
  END out_flit[426]
  PIN out_flit[427]
    DIRECTION OUTPUT ;
    USE SIGNAL ;
    PORT
      LAYER M5 ;
        RECT  87.888 0 87.912 0.084 ;
    END
  END out_flit[427]
  PIN out_flit[428]
    DIRECTION OUTPUT ;
    USE SIGNAL ;
    PORT
      LAYER M5 ;
        RECT  87.984 0 88.008 0.084 ;
    END
  END out_flit[428]
  PIN out_flit[429]
    DIRECTION OUTPUT ;
    USE SIGNAL ;
    PORT
      LAYER M5 ;
        RECT  88.08 0 88.104 0.084 ;
    END
  END out_flit[429]
  PIN out_flit[42]
    DIRECTION OUTPUT ;
    USE SIGNAL ;
    PORT
      LAYER M5 ;
        RECT  49.392 0 49.416 0.084 ;
    END
  END out_flit[42]
  PIN out_flit[430]
    DIRECTION OUTPUT ;
    USE SIGNAL ;
    PORT
      LAYER M5 ;
        RECT  88.176 0 88.2 0.084 ;
    END
  END out_flit[430]
  PIN out_flit[431]
    DIRECTION OUTPUT ;
    USE SIGNAL ;
    PORT
      LAYER M5 ;
        RECT  88.272 0 88.296 0.084 ;
    END
  END out_flit[431]
  PIN out_flit[432]
    DIRECTION OUTPUT ;
    USE SIGNAL ;
    PORT
      LAYER M5 ;
        RECT  88.368 0 88.392 0.084 ;
    END
  END out_flit[432]
  PIN out_flit[433]
    DIRECTION OUTPUT ;
    USE SIGNAL ;
    PORT
      LAYER M5 ;
        RECT  88.464 0 88.488 0.084 ;
    END
  END out_flit[433]
  PIN out_flit[434]
    DIRECTION OUTPUT ;
    USE SIGNAL ;
    PORT
      LAYER M5 ;
        RECT  88.56 0 88.584 0.084 ;
    END
  END out_flit[434]
  PIN out_flit[435]
    DIRECTION OUTPUT ;
    USE SIGNAL ;
    PORT
      LAYER M5 ;
        RECT  88.656 0 88.68 0.084 ;
    END
  END out_flit[435]
  PIN out_flit[436]
    DIRECTION OUTPUT ;
    USE SIGNAL ;
    PORT
      LAYER M5 ;
        RECT  88.752 0 88.776 0.084 ;
    END
  END out_flit[436]
  PIN out_flit[437]
    DIRECTION OUTPUT ;
    USE SIGNAL ;
    PORT
      LAYER M5 ;
        RECT  88.848 0 88.872 0.084 ;
    END
  END out_flit[437]
  PIN out_flit[438]
    DIRECTION OUTPUT ;
    USE SIGNAL ;
    PORT
      LAYER M5 ;
        RECT  88.944 0 88.968 0.084 ;
    END
  END out_flit[438]
  PIN out_flit[439]
    DIRECTION OUTPUT ;
    USE SIGNAL ;
    PORT
      LAYER M5 ;
        RECT  89.04 0 89.064 0.084 ;
    END
  END out_flit[439]
  PIN out_flit[43]
    DIRECTION OUTPUT ;
    USE SIGNAL ;
    PORT
      LAYER M5 ;
        RECT  49.488 0 49.512 0.084 ;
    END
  END out_flit[43]
  PIN out_flit[440]
    DIRECTION OUTPUT ;
    USE SIGNAL ;
    PORT
      LAYER M5 ;
        RECT  89.136 0 89.16 0.084 ;
    END
  END out_flit[440]
  PIN out_flit[441]
    DIRECTION OUTPUT ;
    USE SIGNAL ;
    PORT
      LAYER M5 ;
        RECT  89.232 0 89.256 0.084 ;
    END
  END out_flit[441]
  PIN out_flit[442]
    DIRECTION OUTPUT ;
    USE SIGNAL ;
    PORT
      LAYER M5 ;
        RECT  89.328 0 89.352 0.084 ;
    END
  END out_flit[442]
  PIN out_flit[443]
    DIRECTION OUTPUT ;
    USE SIGNAL ;
    PORT
      LAYER M5 ;
        RECT  89.424 0 89.448 0.084 ;
    END
  END out_flit[443]
  PIN out_flit[444]
    DIRECTION OUTPUT ;
    USE SIGNAL ;
    PORT
      LAYER M5 ;
        RECT  89.52 0 89.544 0.084 ;
    END
  END out_flit[444]
  PIN out_flit[445]
    DIRECTION OUTPUT ;
    USE SIGNAL ;
    PORT
      LAYER M5 ;
        RECT  89.616 0 89.64 0.084 ;
    END
  END out_flit[445]
  PIN out_flit[446]
    DIRECTION OUTPUT ;
    USE SIGNAL ;
    PORT
      LAYER M5 ;
        RECT  89.712 0 89.736 0.084 ;
    END
  END out_flit[446]
  PIN out_flit[447]
    DIRECTION OUTPUT ;
    USE SIGNAL ;
    PORT
      LAYER M5 ;
        RECT  80.592 0 80.616 0.084 ;
    END
  END out_flit[447]
  PIN out_flit[448]
    DIRECTION OUTPUT ;
    USE SIGNAL ;
    PORT
      LAYER M5 ;
        RECT  80.688 0 80.712 0.084 ;
    END
  END out_flit[448]
  PIN out_flit[449]
    DIRECTION OUTPUT ;
    USE SIGNAL ;
    PORT
      LAYER M5 ;
        RECT  80.784 0 80.808 0.084 ;
    END
  END out_flit[449]
  PIN out_flit[44]
    DIRECTION OUTPUT ;
    USE SIGNAL ;
    PORT
      LAYER M5 ;
        RECT  49.584 0 49.608 0.084 ;
    END
  END out_flit[44]
  PIN out_flit[450]
    DIRECTION OUTPUT ;
    USE SIGNAL ;
    PORT
      LAYER M5 ;
        RECT  80.88 0 80.904 0.084 ;
    END
  END out_flit[450]
  PIN out_flit[451]
    DIRECTION OUTPUT ;
    USE SIGNAL ;
    PORT
      LAYER M5 ;
        RECT  80.976 0 81 0.084 ;
    END
  END out_flit[451]
  PIN out_flit[452]
    DIRECTION OUTPUT ;
    USE SIGNAL ;
    PORT
      LAYER M5 ;
        RECT  81.072 0 81.096 0.084 ;
    END
  END out_flit[452]
  PIN out_flit[453]
    DIRECTION OUTPUT ;
    USE SIGNAL ;
    PORT
      LAYER M5 ;
        RECT  81.168 0 81.192 0.084 ;
    END
  END out_flit[453]
  PIN out_flit[454]
    DIRECTION OUTPUT ;
    USE SIGNAL ;
    PORT
      LAYER M5 ;
        RECT  81.264 0 81.288 0.084 ;
    END
  END out_flit[454]
  PIN out_flit[455]
    DIRECTION OUTPUT ;
    USE SIGNAL ;
    PORT
      LAYER M5 ;
        RECT  81.36 0 81.384 0.084 ;
    END
  END out_flit[455]
  PIN out_flit[456]
    DIRECTION OUTPUT ;
    USE SIGNAL ;
    PORT
      LAYER M5 ;
        RECT  81.456 0 81.48 0.084 ;
    END
  END out_flit[456]
  PIN out_flit[457]
    DIRECTION OUTPUT ;
    USE SIGNAL ;
    PORT
      LAYER M5 ;
        RECT  81.552 0 81.576 0.084 ;
    END
  END out_flit[457]
  PIN out_flit[458]
    DIRECTION OUTPUT ;
    USE SIGNAL ;
    PORT
      LAYER M5 ;
        RECT  81.648 0 81.672 0.084 ;
    END
  END out_flit[458]
  PIN out_flit[459]
    DIRECTION OUTPUT ;
    USE SIGNAL ;
    PORT
      LAYER M5 ;
        RECT  81.744 0 81.768 0.084 ;
    END
  END out_flit[459]
  PIN out_flit[45]
    DIRECTION OUTPUT ;
    USE SIGNAL ;
    PORT
      LAYER M5 ;
        RECT  49.68 0 49.704 0.084 ;
    END
  END out_flit[45]
  PIN out_flit[460]
    DIRECTION OUTPUT ;
    USE SIGNAL ;
    PORT
      LAYER M5 ;
        RECT  81.84 0 81.864 0.084 ;
    END
  END out_flit[460]
  PIN out_flit[461]
    DIRECTION OUTPUT ;
    USE SIGNAL ;
    PORT
      LAYER M5 ;
        RECT  81.936 0 81.96 0.084 ;
    END
  END out_flit[461]
  PIN out_flit[462]
    DIRECTION OUTPUT ;
    USE SIGNAL ;
    PORT
      LAYER M5 ;
        RECT  82.032 0 82.056 0.084 ;
    END
  END out_flit[462]
  PIN out_flit[463]
    DIRECTION OUTPUT ;
    USE SIGNAL ;
    PORT
      LAYER M5 ;
        RECT  82.128 0 82.152 0.084 ;
    END
  END out_flit[463]
  PIN out_flit[464]
    DIRECTION OUTPUT ;
    USE SIGNAL ;
    PORT
      LAYER M5 ;
        RECT  82.224 0 82.248 0.084 ;
    END
  END out_flit[464]
  PIN out_flit[465]
    DIRECTION OUTPUT ;
    USE SIGNAL ;
    PORT
      LAYER M5 ;
        RECT  82.32 0 82.344 0.084 ;
    END
  END out_flit[465]
  PIN out_flit[466]
    DIRECTION OUTPUT ;
    USE SIGNAL ;
    PORT
      LAYER M5 ;
        RECT  82.416 0 82.44 0.084 ;
    END
  END out_flit[466]
  PIN out_flit[467]
    DIRECTION OUTPUT ;
    USE SIGNAL ;
    PORT
      LAYER M5 ;
        RECT  82.512 0 82.536 0.084 ;
    END
  END out_flit[467]
  PIN out_flit[468]
    DIRECTION OUTPUT ;
    USE SIGNAL ;
    PORT
      LAYER M5 ;
        RECT  82.608 0 82.632 0.084 ;
    END
  END out_flit[468]
  PIN out_flit[469]
    DIRECTION OUTPUT ;
    USE SIGNAL ;
    PORT
      LAYER M5 ;
        RECT  82.704 0 82.728 0.084 ;
    END
  END out_flit[469]
  PIN out_flit[46]
    DIRECTION OUTPUT ;
    USE SIGNAL ;
    PORT
      LAYER M5 ;
        RECT  49.776 0 49.8 0.084 ;
    END
  END out_flit[46]
  PIN out_flit[470]
    DIRECTION OUTPUT ;
    USE SIGNAL ;
    PORT
      LAYER M5 ;
        RECT  82.8 0 82.824 0.084 ;
    END
  END out_flit[470]
  PIN out_flit[471]
    DIRECTION OUTPUT ;
    USE SIGNAL ;
    PORT
      LAYER M5 ;
        RECT  82.896 0 82.92 0.084 ;
    END
  END out_flit[471]
  PIN out_flit[472]
    DIRECTION OUTPUT ;
    USE SIGNAL ;
    PORT
      LAYER M5 ;
        RECT  82.992 0 83.016 0.084 ;
    END
  END out_flit[472]
  PIN out_flit[473]
    DIRECTION OUTPUT ;
    USE SIGNAL ;
    PORT
      LAYER M5 ;
        RECT  83.088 0 83.112 0.084 ;
    END
  END out_flit[473]
  PIN out_flit[474]
    DIRECTION OUTPUT ;
    USE SIGNAL ;
    PORT
      LAYER M5 ;
        RECT  83.184 0 83.208 0.084 ;
    END
  END out_flit[474]
  PIN out_flit[475]
    DIRECTION OUTPUT ;
    USE SIGNAL ;
    PORT
      LAYER M5 ;
        RECT  83.28 0 83.304 0.084 ;
    END
  END out_flit[475]
  PIN out_flit[476]
    DIRECTION OUTPUT ;
    USE SIGNAL ;
    PORT
      LAYER M5 ;
        RECT  83.376 0 83.4 0.084 ;
    END
  END out_flit[476]
  PIN out_flit[477]
    DIRECTION OUTPUT ;
    USE SIGNAL ;
    PORT
      LAYER M5 ;
        RECT  83.472 0 83.496 0.084 ;
    END
  END out_flit[477]
  PIN out_flit[478]
    DIRECTION OUTPUT ;
    USE SIGNAL ;
    PORT
      LAYER M5 ;
        RECT  83.568 0 83.592 0.084 ;
    END
  END out_flit[478]
  PIN out_flit[479]
    DIRECTION OUTPUT ;
    USE SIGNAL ;
    PORT
      LAYER M5 ;
        RECT  35.28 0 35.304 0.084 ;
    END
  END out_flit[479]
  PIN out_flit[47]
    DIRECTION OUTPUT ;
    USE SIGNAL ;
    PORT
      LAYER M5 ;
        RECT  49.872 0 49.896 0.084 ;
    END
  END out_flit[47]
  PIN out_flit[480]
    DIRECTION OUTPUT ;
    USE SIGNAL ;
    PORT
      LAYER M5 ;
        RECT  35.376 0 35.4 0.084 ;
    END
  END out_flit[480]
  PIN out_flit[481]
    DIRECTION OUTPUT ;
    USE SIGNAL ;
    PORT
      LAYER M5 ;
        RECT  35.472 0 35.496 0.084 ;
    END
  END out_flit[481]
  PIN out_flit[482]
    DIRECTION OUTPUT ;
    USE SIGNAL ;
    PORT
      LAYER M5 ;
        RECT  35.568 0 35.592 0.084 ;
    END
  END out_flit[482]
  PIN out_flit[483]
    DIRECTION OUTPUT ;
    USE SIGNAL ;
    PORT
      LAYER M5 ;
        RECT  35.664 0 35.688 0.084 ;
    END
  END out_flit[483]
  PIN out_flit[484]
    DIRECTION OUTPUT ;
    USE SIGNAL ;
    PORT
      LAYER M5 ;
        RECT  35.76 0 35.784 0.084 ;
    END
  END out_flit[484]
  PIN out_flit[485]
    DIRECTION OUTPUT ;
    USE SIGNAL ;
    PORT
      LAYER M5 ;
        RECT  35.856 0 35.88 0.084 ;
    END
  END out_flit[485]
  PIN out_flit[486]
    DIRECTION OUTPUT ;
    USE SIGNAL ;
    PORT
      LAYER M5 ;
        RECT  35.952 0 35.976 0.084 ;
    END
  END out_flit[486]
  PIN out_flit[487]
    DIRECTION OUTPUT ;
    USE SIGNAL ;
    PORT
      LAYER M5 ;
        RECT  36.048 0 36.072 0.084 ;
    END
  END out_flit[487]
  PIN out_flit[488]
    DIRECTION OUTPUT ;
    USE SIGNAL ;
    PORT
      LAYER M5 ;
        RECT  36.144 0 36.168 0.084 ;
    END
  END out_flit[488]
  PIN out_flit[489]
    DIRECTION OUTPUT ;
    USE SIGNAL ;
    PORT
      LAYER M5 ;
        RECT  36.24 0 36.264 0.084 ;
    END
  END out_flit[489]
  PIN out_flit[48]
    DIRECTION OUTPUT ;
    USE SIGNAL ;
    PORT
      LAYER M5 ;
        RECT  49.968 0 49.992 0.084 ;
    END
  END out_flit[48]
  PIN out_flit[490]
    DIRECTION OUTPUT ;
    USE SIGNAL ;
    PORT
      LAYER M5 ;
        RECT  36.336 0 36.36 0.084 ;
    END
  END out_flit[490]
  PIN out_flit[491]
    DIRECTION OUTPUT ;
    USE SIGNAL ;
    PORT
      LAYER M5 ;
        RECT  36.432 0 36.456 0.084 ;
    END
  END out_flit[491]
  PIN out_flit[492]
    DIRECTION OUTPUT ;
    USE SIGNAL ;
    PORT
      LAYER M5 ;
        RECT  36.528 0 36.552 0.084 ;
    END
  END out_flit[492]
  PIN out_flit[493]
    DIRECTION OUTPUT ;
    USE SIGNAL ;
    PORT
      LAYER M5 ;
        RECT  36.624 0 36.648 0.084 ;
    END
  END out_flit[493]
  PIN out_flit[494]
    DIRECTION OUTPUT ;
    USE SIGNAL ;
    PORT
      LAYER M5 ;
        RECT  36.72 0 36.744 0.084 ;
    END
  END out_flit[494]
  PIN out_flit[495]
    DIRECTION OUTPUT ;
    USE SIGNAL ;
    PORT
      LAYER M5 ;
        RECT  36.816 0 36.84 0.084 ;
    END
  END out_flit[495]
  PIN out_flit[496]
    DIRECTION OUTPUT ;
    USE SIGNAL ;
    PORT
      LAYER M5 ;
        RECT  36.912 0 36.936 0.084 ;
    END
  END out_flit[496]
  PIN out_flit[497]
    DIRECTION OUTPUT ;
    USE SIGNAL ;
    PORT
      LAYER M5 ;
        RECT  37.008 0 37.032 0.084 ;
    END
  END out_flit[497]
  PIN out_flit[498]
    DIRECTION OUTPUT ;
    USE SIGNAL ;
    PORT
      LAYER M5 ;
        RECT  37.104 0 37.128 0.084 ;
    END
  END out_flit[498]
  PIN out_flit[499]
    DIRECTION OUTPUT ;
    USE SIGNAL ;
    PORT
      LAYER M5 ;
        RECT  37.2 0 37.224 0.084 ;
    END
  END out_flit[499]
  PIN out_flit[49]
    DIRECTION OUTPUT ;
    USE SIGNAL ;
    PORT
      LAYER M5 ;
        RECT  50.064 0 50.088 0.084 ;
    END
  END out_flit[49]
  PIN out_flit[4]
    DIRECTION OUTPUT ;
    USE SIGNAL ;
    PORT
      LAYER M5 ;
        RECT  45.744 0 45.768 0.084 ;
    END
  END out_flit[4]
  PIN out_flit[500]
    DIRECTION OUTPUT ;
    USE SIGNAL ;
    PORT
      LAYER M5 ;
        RECT  37.296 0 37.32 0.084 ;
    END
  END out_flit[500]
  PIN out_flit[501]
    DIRECTION OUTPUT ;
    USE SIGNAL ;
    PORT
      LAYER M5 ;
        RECT  37.392 0 37.416 0.084 ;
    END
  END out_flit[501]
  PIN out_flit[502]
    DIRECTION OUTPUT ;
    USE SIGNAL ;
    PORT
      LAYER M5 ;
        RECT  37.488 0 37.512 0.084 ;
    END
  END out_flit[502]
  PIN out_flit[503]
    DIRECTION OUTPUT ;
    USE SIGNAL ;
    PORT
      LAYER M5 ;
        RECT  37.584 0 37.608 0.084 ;
    END
  END out_flit[503]
  PIN out_flit[504]
    DIRECTION OUTPUT ;
    USE SIGNAL ;
    PORT
      LAYER M5 ;
        RECT  37.68 0 37.704 0.084 ;
    END
  END out_flit[504]
  PIN out_flit[505]
    DIRECTION OUTPUT ;
    USE SIGNAL ;
    PORT
      LAYER M5 ;
        RECT  37.776 0 37.8 0.084 ;
    END
  END out_flit[505]
  PIN out_flit[506]
    DIRECTION OUTPUT ;
    USE SIGNAL ;
    PORT
      LAYER M5 ;
        RECT  37.872 0 37.896 0.084 ;
    END
  END out_flit[506]
  PIN out_flit[507]
    DIRECTION OUTPUT ;
    USE SIGNAL ;
    PORT
      LAYER M5 ;
        RECT  37.968 0 37.992 0.084 ;
    END
  END out_flit[507]
  PIN out_flit[508]
    DIRECTION OUTPUT ;
    USE SIGNAL ;
    PORT
      LAYER M5 ;
        RECT  38.064 0 38.088 0.084 ;
    END
  END out_flit[508]
  PIN out_flit[509]
    DIRECTION OUTPUT ;
    USE SIGNAL ;
    PORT
      LAYER M5 ;
        RECT  38.16 0 38.184 0.084 ;
    END
  END out_flit[509]
  PIN out_flit[50]
    DIRECTION OUTPUT ;
    USE SIGNAL ;
    PORT
      LAYER M5 ;
        RECT  50.16 0 50.184 0.084 ;
    END
  END out_flit[50]
  PIN out_flit[510]
    DIRECTION OUTPUT ;
    USE SIGNAL ;
    PORT
      LAYER M5 ;
        RECT  38.256 0 38.28 0.084 ;
    END
  END out_flit[510]
  PIN out_flit[511]
    DIRECTION OUTPUT ;
    USE SIGNAL ;
    PORT
      LAYER M5 ;
        RECT  77.52 0 77.544 0.084 ;
    END
  END out_flit[511]
  PIN out_flit[512]
    DIRECTION OUTPUT ;
    USE SIGNAL ;
    PORT
      LAYER M5 ;
        RECT  77.616 0 77.64 0.084 ;
    END
  END out_flit[512]
  PIN out_flit[513]
    DIRECTION OUTPUT ;
    USE SIGNAL ;
    PORT
      LAYER M5 ;
        RECT  77.712 0 77.736 0.084 ;
    END
  END out_flit[513]
  PIN out_flit[514]
    DIRECTION OUTPUT ;
    USE SIGNAL ;
    PORT
      LAYER M5 ;
        RECT  77.808 0 77.832 0.084 ;
    END
  END out_flit[514]
  PIN out_flit[515]
    DIRECTION OUTPUT ;
    USE SIGNAL ;
    PORT
      LAYER M5 ;
        RECT  77.904 0 77.928 0.084 ;
    END
  END out_flit[515]
  PIN out_flit[516]
    DIRECTION OUTPUT ;
    USE SIGNAL ;
    PORT
      LAYER M5 ;
        RECT  78 0 78.024 0.084 ;
    END
  END out_flit[516]
  PIN out_flit[517]
    DIRECTION OUTPUT ;
    USE SIGNAL ;
    PORT
      LAYER M5 ;
        RECT  78.096 0 78.12 0.084 ;
    END
  END out_flit[517]
  PIN out_flit[518]
    DIRECTION OUTPUT ;
    USE SIGNAL ;
    PORT
      LAYER M5 ;
        RECT  78.192 0 78.216 0.084 ;
    END
  END out_flit[518]
  PIN out_flit[519]
    DIRECTION OUTPUT ;
    USE SIGNAL ;
    PORT
      LAYER M5 ;
        RECT  78.288 0 78.312 0.084 ;
    END
  END out_flit[519]
  PIN out_flit[51]
    DIRECTION OUTPUT ;
    USE SIGNAL ;
    PORT
      LAYER M5 ;
        RECT  50.256 0 50.28 0.084 ;
    END
  END out_flit[51]
  PIN out_flit[520]
    DIRECTION OUTPUT ;
    USE SIGNAL ;
    PORT
      LAYER M5 ;
        RECT  78.384 0 78.408 0.084 ;
    END
  END out_flit[520]
  PIN out_flit[521]
    DIRECTION OUTPUT ;
    USE SIGNAL ;
    PORT
      LAYER M5 ;
        RECT  78.48 0 78.504 0.084 ;
    END
  END out_flit[521]
  PIN out_flit[522]
    DIRECTION OUTPUT ;
    USE SIGNAL ;
    PORT
      LAYER M5 ;
        RECT  78.576 0 78.6 0.084 ;
    END
  END out_flit[522]
  PIN out_flit[523]
    DIRECTION OUTPUT ;
    USE SIGNAL ;
    PORT
      LAYER M5 ;
        RECT  78.672 0 78.696 0.084 ;
    END
  END out_flit[523]
  PIN out_flit[524]
    DIRECTION OUTPUT ;
    USE SIGNAL ;
    PORT
      LAYER M5 ;
        RECT  78.768 0 78.792 0.084 ;
    END
  END out_flit[524]
  PIN out_flit[525]
    DIRECTION OUTPUT ;
    USE SIGNAL ;
    PORT
      LAYER M5 ;
        RECT  78.864 0 78.888 0.084 ;
    END
  END out_flit[525]
  PIN out_flit[526]
    DIRECTION OUTPUT ;
    USE SIGNAL ;
    PORT
      LAYER M5 ;
        RECT  78.96 0 78.984 0.084 ;
    END
  END out_flit[526]
  PIN out_flit[527]
    DIRECTION OUTPUT ;
    USE SIGNAL ;
    PORT
      LAYER M5 ;
        RECT  79.056 0 79.08 0.084 ;
    END
  END out_flit[527]
  PIN out_flit[528]
    DIRECTION OUTPUT ;
    USE SIGNAL ;
    PORT
      LAYER M5 ;
        RECT  79.152 0 79.176 0.084 ;
    END
  END out_flit[528]
  PIN out_flit[529]
    DIRECTION OUTPUT ;
    USE SIGNAL ;
    PORT
      LAYER M5 ;
        RECT  79.248 0 79.272 0.084 ;
    END
  END out_flit[529]
  PIN out_flit[52]
    DIRECTION OUTPUT ;
    USE SIGNAL ;
    PORT
      LAYER M5 ;
        RECT  50.352 0 50.376 0.084 ;
    END
  END out_flit[52]
  PIN out_flit[530]
    DIRECTION OUTPUT ;
    USE SIGNAL ;
    PORT
      LAYER M5 ;
        RECT  79.344 0 79.368 0.084 ;
    END
  END out_flit[530]
  PIN out_flit[531]
    DIRECTION OUTPUT ;
    USE SIGNAL ;
    PORT
      LAYER M5 ;
        RECT  79.44 0 79.464 0.084 ;
    END
  END out_flit[531]
  PIN out_flit[532]
    DIRECTION OUTPUT ;
    USE SIGNAL ;
    PORT
      LAYER M5 ;
        RECT  79.536 0 79.56 0.084 ;
    END
  END out_flit[532]
  PIN out_flit[533]
    DIRECTION OUTPUT ;
    USE SIGNAL ;
    PORT
      LAYER M5 ;
        RECT  79.632 0 79.656 0.084 ;
    END
  END out_flit[533]
  PIN out_flit[534]
    DIRECTION OUTPUT ;
    USE SIGNAL ;
    PORT
      LAYER M5 ;
        RECT  79.728 0 79.752 0.084 ;
    END
  END out_flit[534]
  PIN out_flit[535]
    DIRECTION OUTPUT ;
    USE SIGNAL ;
    PORT
      LAYER M5 ;
        RECT  79.824 0 79.848 0.084 ;
    END
  END out_flit[535]
  PIN out_flit[536]
    DIRECTION OUTPUT ;
    USE SIGNAL ;
    PORT
      LAYER M5 ;
        RECT  79.92 0 79.944 0.084 ;
    END
  END out_flit[536]
  PIN out_flit[537]
    DIRECTION OUTPUT ;
    USE SIGNAL ;
    PORT
      LAYER M5 ;
        RECT  80.016 0 80.04 0.084 ;
    END
  END out_flit[537]
  PIN out_flit[538]
    DIRECTION OUTPUT ;
    USE SIGNAL ;
    PORT
      LAYER M5 ;
        RECT  80.112 0 80.136 0.084 ;
    END
  END out_flit[538]
  PIN out_flit[539]
    DIRECTION OUTPUT ;
    USE SIGNAL ;
    PORT
      LAYER M5 ;
        RECT  80.208 0 80.232 0.084 ;
    END
  END out_flit[539]
  PIN out_flit[53]
    DIRECTION OUTPUT ;
    USE SIGNAL ;
    PORT
      LAYER M5 ;
        RECT  50.448 0 50.472 0.084 ;
    END
  END out_flit[53]
  PIN out_flit[540]
    DIRECTION OUTPUT ;
    USE SIGNAL ;
    PORT
      LAYER M5 ;
        RECT  80.304 0 80.328 0.084 ;
    END
  END out_flit[540]
  PIN out_flit[541]
    DIRECTION OUTPUT ;
    USE SIGNAL ;
    PORT
      LAYER M5 ;
        RECT  80.4 0 80.424 0.084 ;
    END
  END out_flit[541]
  PIN out_flit[542]
    DIRECTION OUTPUT ;
    USE SIGNAL ;
    PORT
      LAYER M5 ;
        RECT  80.496 0 80.52 0.084 ;
    END
  END out_flit[542]
  PIN out_flit[543]
    DIRECTION OUTPUT ;
    USE SIGNAL ;
    PORT
      LAYER M5 ;
        RECT  57.552 0 57.576 0.084 ;
    END
  END out_flit[543]
  PIN out_flit[544]
    DIRECTION OUTPUT ;
    USE SIGNAL ;
    PORT
      LAYER M5 ;
        RECT  57.648 0 57.672 0.084 ;
    END
  END out_flit[544]
  PIN out_flit[54]
    DIRECTION OUTPUT ;
    USE SIGNAL ;
    PORT
      LAYER M5 ;
        RECT  50.544 0 50.568 0.084 ;
    END
  END out_flit[54]
  PIN out_flit[55]
    DIRECTION OUTPUT ;
    USE SIGNAL ;
    PORT
      LAYER M5 ;
        RECT  50.64 0 50.664 0.084 ;
    END
  END out_flit[55]
  PIN out_flit[56]
    DIRECTION OUTPUT ;
    USE SIGNAL ;
    PORT
      LAYER M5 ;
        RECT  50.736 0 50.76 0.084 ;
    END
  END out_flit[56]
  PIN out_flit[57]
    DIRECTION OUTPUT ;
    USE SIGNAL ;
    PORT
      LAYER M5 ;
        RECT  50.832 0 50.856 0.084 ;
    END
  END out_flit[57]
  PIN out_flit[58]
    DIRECTION OUTPUT ;
    USE SIGNAL ;
    PORT
      LAYER M5 ;
        RECT  50.928 0 50.952 0.084 ;
    END
  END out_flit[58]
  PIN out_flit[59]
    DIRECTION OUTPUT ;
    USE SIGNAL ;
    PORT
      LAYER M5 ;
        RECT  51.024 0 51.048 0.084 ;
    END
  END out_flit[59]
  PIN out_flit[5]
    DIRECTION OUTPUT ;
    USE SIGNAL ;
    PORT
      LAYER M5 ;
        RECT  45.84 0 45.864 0.084 ;
    END
  END out_flit[5]
  PIN out_flit[60]
    DIRECTION OUTPUT ;
    USE SIGNAL ;
    PORT
      LAYER M5 ;
        RECT  51.12 0 51.144 0.084 ;
    END
  END out_flit[60]
  PIN out_flit[61]
    DIRECTION OUTPUT ;
    USE SIGNAL ;
    PORT
      LAYER M5 ;
        RECT  51.216 0 51.24 0.084 ;
    END
  END out_flit[61]
  PIN out_flit[62]
    DIRECTION OUTPUT ;
    USE SIGNAL ;
    PORT
      LAYER M5 ;
        RECT  51.312 0 51.336 0.084 ;
    END
  END out_flit[62]
  PIN out_flit[63]
    DIRECTION OUTPUT ;
    USE SIGNAL ;
    PORT
      LAYER M5 ;
        RECT  70.608 0 70.632 0.084 ;
    END
  END out_flit[63]
  PIN out_flit[64]
    DIRECTION OUTPUT ;
    USE SIGNAL ;
    PORT
      LAYER M5 ;
        RECT  70.704 0 70.728 0.084 ;
    END
  END out_flit[64]
  PIN out_flit[65]
    DIRECTION OUTPUT ;
    USE SIGNAL ;
    PORT
      LAYER M5 ;
        RECT  70.8 0 70.824 0.084 ;
    END
  END out_flit[65]
  PIN out_flit[66]
    DIRECTION OUTPUT ;
    USE SIGNAL ;
    PORT
      LAYER M5 ;
        RECT  70.896 0 70.92 0.084 ;
    END
  END out_flit[66]
  PIN out_flit[67]
    DIRECTION OUTPUT ;
    USE SIGNAL ;
    PORT
      LAYER M5 ;
        RECT  70.992 0 71.016 0.084 ;
    END
  END out_flit[67]
  PIN out_flit[68]
    DIRECTION OUTPUT ;
    USE SIGNAL ;
    PORT
      LAYER M5 ;
        RECT  71.088 0 71.112 0.084 ;
    END
  END out_flit[68]
  PIN out_flit[69]
    DIRECTION OUTPUT ;
    USE SIGNAL ;
    PORT
      LAYER M5 ;
        RECT  71.184 0 71.208 0.084 ;
    END
  END out_flit[69]
  PIN out_flit[6]
    DIRECTION OUTPUT ;
    USE SIGNAL ;
    PORT
      LAYER M5 ;
        RECT  45.936 0 45.96 0.084 ;
    END
  END out_flit[6]
  PIN out_flit[70]
    DIRECTION OUTPUT ;
    USE SIGNAL ;
    PORT
      LAYER M5 ;
        RECT  71.28 0 71.304 0.084 ;
    END
  END out_flit[70]
  PIN out_flit[71]
    DIRECTION OUTPUT ;
    USE SIGNAL ;
    PORT
      LAYER M5 ;
        RECT  71.376 0 71.4 0.084 ;
    END
  END out_flit[71]
  PIN out_flit[72]
    DIRECTION OUTPUT ;
    USE SIGNAL ;
    PORT
      LAYER M5 ;
        RECT  71.472 0 71.496 0.084 ;
    END
  END out_flit[72]
  PIN out_flit[73]
    DIRECTION OUTPUT ;
    USE SIGNAL ;
    PORT
      LAYER M5 ;
        RECT  71.568 0 71.592 0.084 ;
    END
  END out_flit[73]
  PIN out_flit[74]
    DIRECTION OUTPUT ;
    USE SIGNAL ;
    PORT
      LAYER M5 ;
        RECT  71.664 0 71.688 0.084 ;
    END
  END out_flit[74]
  PIN out_flit[75]
    DIRECTION OUTPUT ;
    USE SIGNAL ;
    PORT
      LAYER M5 ;
        RECT  71.76 0 71.784 0.084 ;
    END
  END out_flit[75]
  PIN out_flit[76]
    DIRECTION OUTPUT ;
    USE SIGNAL ;
    PORT
      LAYER M5 ;
        RECT  71.856 0 71.88 0.084 ;
    END
  END out_flit[76]
  PIN out_flit[77]
    DIRECTION OUTPUT ;
    USE SIGNAL ;
    PORT
      LAYER M5 ;
        RECT  71.952 0 71.976 0.084 ;
    END
  END out_flit[77]
  PIN out_flit[78]
    DIRECTION OUTPUT ;
    USE SIGNAL ;
    PORT
      LAYER M5 ;
        RECT  72.048 0 72.072 0.084 ;
    END
  END out_flit[78]
  PIN out_flit[79]
    DIRECTION OUTPUT ;
    USE SIGNAL ;
    PORT
      LAYER M5 ;
        RECT  72.144 0 72.168 0.084 ;
    END
  END out_flit[79]
  PIN out_flit[7]
    DIRECTION OUTPUT ;
    USE SIGNAL ;
    PORT
      LAYER M5 ;
        RECT  46.032 0 46.056 0.084 ;
    END
  END out_flit[7]
  PIN out_flit[80]
    DIRECTION OUTPUT ;
    USE SIGNAL ;
    PORT
      LAYER M5 ;
        RECT  72.24 0 72.264 0.084 ;
    END
  END out_flit[80]
  PIN out_flit[81]
    DIRECTION OUTPUT ;
    USE SIGNAL ;
    PORT
      LAYER M5 ;
        RECT  72.336 0 72.36 0.084 ;
    END
  END out_flit[81]
  PIN out_flit[82]
    DIRECTION OUTPUT ;
    USE SIGNAL ;
    PORT
      LAYER M5 ;
        RECT  72.432 0 72.456 0.084 ;
    END
  END out_flit[82]
  PIN out_flit[83]
    DIRECTION OUTPUT ;
    USE SIGNAL ;
    PORT
      LAYER M5 ;
        RECT  72.528 0 72.552 0.084 ;
    END
  END out_flit[83]
  PIN out_flit[84]
    DIRECTION OUTPUT ;
    USE SIGNAL ;
    PORT
      LAYER M5 ;
        RECT  72.624 0 72.648 0.084 ;
    END
  END out_flit[84]
  PIN out_flit[85]
    DIRECTION OUTPUT ;
    USE SIGNAL ;
    PORT
      LAYER M5 ;
        RECT  72.72 0 72.744 0.084 ;
    END
  END out_flit[85]
  PIN out_flit[86]
    DIRECTION OUTPUT ;
    USE SIGNAL ;
    PORT
      LAYER M5 ;
        RECT  72.816 0 72.84 0.084 ;
    END
  END out_flit[86]
  PIN out_flit[87]
    DIRECTION OUTPUT ;
    USE SIGNAL ;
    PORT
      LAYER M5 ;
        RECT  72.912 0 72.936 0.084 ;
    END
  END out_flit[87]
  PIN out_flit[88]
    DIRECTION OUTPUT ;
    USE SIGNAL ;
    PORT
      LAYER M5 ;
        RECT  73.008 0 73.032 0.084 ;
    END
  END out_flit[88]
  PIN out_flit[89]
    DIRECTION OUTPUT ;
    USE SIGNAL ;
    PORT
      LAYER M5 ;
        RECT  73.104 0 73.128 0.084 ;
    END
  END out_flit[89]
  PIN out_flit[8]
    DIRECTION OUTPUT ;
    USE SIGNAL ;
    PORT
      LAYER M5 ;
        RECT  46.128 0 46.152 0.084 ;
    END
  END out_flit[8]
  PIN out_flit[90]
    DIRECTION OUTPUT ;
    USE SIGNAL ;
    PORT
      LAYER M5 ;
        RECT  73.2 0 73.224 0.084 ;
    END
  END out_flit[90]
  PIN out_flit[91]
    DIRECTION OUTPUT ;
    USE SIGNAL ;
    PORT
      LAYER M5 ;
        RECT  73.296 0 73.32 0.084 ;
    END
  END out_flit[91]
  PIN out_flit[92]
    DIRECTION OUTPUT ;
    USE SIGNAL ;
    PORT
      LAYER M5 ;
        RECT  73.392 0 73.416 0.084 ;
    END
  END out_flit[92]
  PIN out_flit[93]
    DIRECTION OUTPUT ;
    USE SIGNAL ;
    PORT
      LAYER M5 ;
        RECT  73.488 0 73.512 0.084 ;
    END
  END out_flit[93]
  PIN out_flit[94]
    DIRECTION OUTPUT ;
    USE SIGNAL ;
    PORT
      LAYER M5 ;
        RECT  73.584 0 73.608 0.084 ;
    END
  END out_flit[94]
  PIN out_flit[95]
    DIRECTION OUTPUT ;
    USE SIGNAL ;
    PORT
      LAYER M5 ;
        RECT  54.48 0 54.504 0.084 ;
    END
  END out_flit[95]
  PIN out_flit[96]
    DIRECTION OUTPUT ;
    USE SIGNAL ;
    PORT
      LAYER M5 ;
        RECT  54.576 0 54.6 0.084 ;
    END
  END out_flit[96]
  PIN out_flit[97]
    DIRECTION OUTPUT ;
    USE SIGNAL ;
    PORT
      LAYER M5 ;
        RECT  54.672 0 54.696 0.084 ;
    END
  END out_flit[97]
  PIN out_flit[98]
    DIRECTION OUTPUT ;
    USE SIGNAL ;
    PORT
      LAYER M5 ;
        RECT  54.768 0 54.792 0.084 ;
    END
  END out_flit[98]
  PIN out_flit[99]
    DIRECTION OUTPUT ;
    USE SIGNAL ;
    PORT
      LAYER M5 ;
        RECT  54.864 0 54.888 0.084 ;
    END
  END out_flit[99]
  PIN out_flit[9]
    DIRECTION OUTPUT ;
    USE SIGNAL ;
    PORT
      LAYER M5 ;
        RECT  46.224 0 46.248 0.084 ;
    END
  END out_flit[9]
  PIN out_v
    DIRECTION OUTPUT ;
    USE SIGNAL ;
    PORT
      LAYER M5 ;
        RECT  57.744 0 57.768 0.084 ;
    END
  END out_v
  PIN publish_slot
    DIRECTION INPUT ;
    USE SIGNAL ;
    PORT
      LAYER M5 ;
        RECT  55.824 47.436 55.848 47.52 ;
    END
  END publish_slot
  PIN rst_n
    DIRECTION INPUT ;
    USE SIGNAL ;
    PORT
      LAYER M4 ;
        RECT  0 41.232 0.084 41.256 ;
    END
  END rst_n
  PIN start
    DIRECTION INPUT ;
    USE SIGNAL ;
    PORT
      LAYER M4 ;
        RECT  0 41.328 0.084 41.352 ;
    END
  END start
  PIN VDD
    DIRECTION INOUT ;
    USE POWER ;
    PORT
      LAYER M5 ;
        RECT  88.992 2.151 89.112 45.369 ;
        RECT  83.592 2.151 83.712 45.369 ;
        RECT  78.192 2.151 78.312 45.369 ;
        RECT  72.792 2.151 72.912 45.369 ;
        RECT  67.392 2.151 67.512 45.369 ;
        RECT  61.992 2.151 62.112 45.369 ;
        RECT  56.592 2.151 56.712 45.369 ;
        RECT  51.192 2.151 51.312 45.369 ;
        RECT  45.792 2.151 45.912 45.369 ;
        RECT  40.392 2.151 40.512 45.369 ;
        RECT  34.992 2.151 35.112 45.369 ;
        RECT  29.592 2.151 29.712 45.369 ;
        RECT  24.192 2.151 24.312 45.369 ;
        RECT  18.792 2.151 18.912 45.369 ;
        RECT  13.392 2.151 13.512 45.369 ;
        RECT  7.992 2.151 8.112 45.369 ;
        RECT  2.592 2.151 2.712 45.369 ;
    END
  END VDD
  PIN VSS
    DIRECTION INOUT ;
    USE GROUND ;
    PORT
      LAYER M5 ;
        RECT  88.8 2.137 88.92 45.383 ;
        RECT  83.4 2.137 83.52 45.383 ;
        RECT  78 2.137 78.12 45.383 ;
        RECT  72.6 2.137 72.72 45.383 ;
        RECT  67.2 2.137 67.32 45.383 ;
        RECT  61.8 2.137 61.92 45.383 ;
        RECT  56.4 2.137 56.52 45.383 ;
        RECT  51 2.137 51.12 45.383 ;
        RECT  45.6 2.137 45.72 45.383 ;
        RECT  40.2 2.137 40.32 45.383 ;
        RECT  34.8 2.137 34.92 45.383 ;
        RECT  29.4 2.137 29.52 45.383 ;
        RECT  24 2.137 24.12 45.383 ;
        RECT  18.6 2.137 18.72 45.383 ;
        RECT  13.2 2.137 13.32 45.383 ;
        RECT  7.8 2.137 7.92 45.383 ;
        RECT  2.4 2.137 2.52 45.383 ;
    END
  END VSS
  OBS
    LAYER RVTN ;
     RECT  2.16 2.16 92.88 2.295 ;
     RECT  2.16 2.565 92.88 2.835 ;
     RECT  2.16 3.105 92.88 3.375 ;
     RECT  2.16 3.645 92.88 3.915 ;
     RECT  2.16 4.185 92.88 4.455 ;
     RECT  2.16 4.725 92.88 4.995 ;
     RECT  2.16 5.265 92.88 5.535 ;
     RECT  2.16 5.805 92.88 6.075 ;
     RECT  2.16 6.345 92.88 6.615 ;
     RECT  2.16 6.885 92.88 7.155 ;
     RECT  2.16 7.425 92.88 7.695 ;
     RECT  2.16 7.965 92.88 8.235 ;
     RECT  2.16 8.505 92.88 8.775 ;
     RECT  2.16 9.045 92.88 9.315 ;
     RECT  2.16 9.585 92.88 9.855 ;
     RECT  2.16 10.125 92.88 10.395 ;
     RECT  2.16 10.665 92.88 10.935 ;
     RECT  2.16 11.205 92.88 11.475 ;
     RECT  2.16 11.745 92.88 12.015 ;
     RECT  2.16 12.285 92.88 12.555 ;
     RECT  2.16 12.825 92.88 13.095 ;
     RECT  2.16 13.365 92.88 13.635 ;
     RECT  2.16 13.905 92.88 14.175 ;
     RECT  2.16 14.445 92.88 14.715 ;
     RECT  2.16 14.985 92.88 15.255 ;
     RECT  2.16 15.525 92.88 15.795 ;
     RECT  2.16 16.065 92.88 16.335 ;
     RECT  2.16 16.605 92.88 16.875 ;
     RECT  2.16 17.145 92.88 17.415 ;
     RECT  2.16 17.685 92.88 17.955 ;
     RECT  2.16 18.225 92.88 18.495 ;
     RECT  2.16 18.765 92.88 19.035 ;
     RECT  2.16 19.305 92.88 19.575 ;
     RECT  2.16 19.845 92.88 20.115 ;
     RECT  2.16 20.385 92.88 20.655 ;
     RECT  2.16 20.925 92.88 21.195 ;
     RECT  2.16 21.465 92.88 21.735 ;
     RECT  2.16 22.005 92.88 22.275 ;
     RECT  2.16 22.545 92.88 22.815 ;
     RECT  2.16 23.085 92.88 23.355 ;
     RECT  2.16 23.625 92.88 23.895 ;
     RECT  2.16 24.165 92.88 24.435 ;
     RECT  2.16 24.705 92.88 24.975 ;
     RECT  2.16 25.245 92.88 25.515 ;
     RECT  2.16 25.785 92.88 26.055 ;
     RECT  2.16 26.325 92.88 26.595 ;
     RECT  2.16 26.865 92.88 27.135 ;
     RECT  2.16 27.405 92.88 27.675 ;
     RECT  2.16 27.945 92.88 28.215 ;
     RECT  2.16 28.485 92.88 28.755 ;
     RECT  2.16 29.025 92.88 29.295 ;
     RECT  2.16 29.565 92.88 29.835 ;
     RECT  2.16 30.105 92.88 30.375 ;
     RECT  2.16 30.645 92.88 30.915 ;
     RECT  2.16 31.185 92.88 31.455 ;
     RECT  2.16 31.725 92.88 31.995 ;
     RECT  2.16 32.265 92.88 32.535 ;
     RECT  2.16 32.805 92.88 33.075 ;
     RECT  2.16 33.345 92.88 33.615 ;
     RECT  2.16 33.885 92.88 34.155 ;
     RECT  2.16 34.425 92.88 34.695 ;
     RECT  2.16 34.965 92.88 35.235 ;
     RECT  2.16 35.505 92.88 35.775 ;
     RECT  2.16 36.045 92.88 36.315 ;
     RECT  2.16 36.585 92.88 36.855 ;
     RECT  2.16 37.125 92.88 37.395 ;
     RECT  2.16 37.665 92.88 37.935 ;
     RECT  2.16 38.205 92.88 38.475 ;
     RECT  2.16 38.745 92.88 39.015 ;
     RECT  2.16 39.285 92.88 39.555 ;
     RECT  2.16 39.825 92.88 40.095 ;
     RECT  2.16 40.365 92.88 40.635 ;
     RECT  2.16 40.905 92.88 41.175 ;
     RECT  2.16 41.445 92.88 41.715 ;
     RECT  2.16 41.985 92.88 42.255 ;
     RECT  2.16 42.525 92.88 42.795 ;
     RECT  2.16 43.065 92.88 43.335 ;
     RECT  2.16 43.605 92.88 43.875 ;
     RECT  2.16 44.145 92.88 44.415 ;
     RECT  2.16 44.685 92.88 44.955 ;
     RECT  2.16 45.225 92.88 45.36 ;
    LAYER RVTP ;
     RECT  2.16 2.295 92.88 2.565 ;
     RECT  2.16 2.835 92.88 3.105 ;
     RECT  2.16 3.375 92.88 3.645 ;
     RECT  2.16 3.915 92.88 4.185 ;
     RECT  2.16 4.455 92.88 4.725 ;
     RECT  2.16 4.995 92.88 5.265 ;
     RECT  2.16 5.535 92.88 5.805 ;
     RECT  2.16 6.075 92.88 6.345 ;
     RECT  2.16 6.615 92.88 6.885 ;
     RECT  2.16 7.155 92.88 7.425 ;
     RECT  2.16 7.695 92.88 7.965 ;
     RECT  2.16 8.235 92.88 8.505 ;
     RECT  2.16 8.775 92.88 9.045 ;
     RECT  2.16 9.315 92.88 9.585 ;
     RECT  2.16 9.855 92.88 10.125 ;
     RECT  2.16 10.395 92.88 10.665 ;
     RECT  2.16 10.935 92.88 11.205 ;
     RECT  2.16 11.475 92.88 11.745 ;
     RECT  2.16 12.015 92.88 12.285 ;
     RECT  2.16 12.555 92.88 12.825 ;
     RECT  2.16 13.095 92.88 13.365 ;
     RECT  2.16 13.635 92.88 13.905 ;
     RECT  2.16 14.175 92.88 14.445 ;
     RECT  2.16 14.715 92.88 14.985 ;
     RECT  2.16 15.255 92.88 15.525 ;
     RECT  2.16 15.795 92.88 16.065 ;
     RECT  2.16 16.335 92.88 16.605 ;
     RECT  2.16 16.875 92.88 17.145 ;
     RECT  2.16 17.415 92.88 17.685 ;
     RECT  2.16 17.955 92.88 18.225 ;
     RECT  2.16 18.495 92.88 18.765 ;
     RECT  2.16 19.035 92.88 19.305 ;
     RECT  2.16 19.575 92.88 19.845 ;
     RECT  2.16 20.115 92.88 20.385 ;
     RECT  2.16 20.655 92.88 20.925 ;
     RECT  2.16 21.195 92.88 21.465 ;
     RECT  2.16 21.735 92.88 22.005 ;
     RECT  2.16 22.275 92.88 22.545 ;
     RECT  2.16 22.815 92.88 23.085 ;
     RECT  2.16 23.355 92.88 23.625 ;
     RECT  2.16 23.895 92.88 24.165 ;
     RECT  2.16 24.435 92.88 24.705 ;
     RECT  2.16 24.975 92.88 25.245 ;
     RECT  2.16 25.515 92.88 25.785 ;
     RECT  2.16 26.055 92.88 26.325 ;
     RECT  2.16 26.595 92.88 26.865 ;
     RECT  2.16 27.135 92.88 27.405 ;
     RECT  2.16 27.675 92.88 27.945 ;
     RECT  2.16 28.215 92.88 28.485 ;
     RECT  2.16 28.755 92.88 29.025 ;
     RECT  2.16 29.295 92.88 29.565 ;
     RECT  2.16 29.835 92.88 30.105 ;
     RECT  2.16 30.375 92.88 30.645 ;
     RECT  2.16 30.915 92.88 31.185 ;
     RECT  2.16 31.455 92.88 31.725 ;
     RECT  2.16 31.995 92.88 32.265 ;
     RECT  2.16 32.535 92.88 32.805 ;
     RECT  2.16 33.075 92.88 33.345 ;
     RECT  2.16 33.615 92.88 33.885 ;
     RECT  2.16 34.155 92.88 34.425 ;
     RECT  2.16 34.695 92.88 34.965 ;
     RECT  2.16 35.235 92.88 35.505 ;
     RECT  2.16 35.775 92.88 36.045 ;
     RECT  2.16 36.315 92.88 36.585 ;
     RECT  2.16 36.855 92.88 37.125 ;
     RECT  2.16 37.395 92.88 37.665 ;
     RECT  2.16 37.935 92.88 38.205 ;
     RECT  2.16 38.475 92.88 38.745 ;
     RECT  2.16 39.015 92.88 39.285 ;
     RECT  2.16 39.555 92.88 39.825 ;
     RECT  2.16 40.095 92.88 40.365 ;
     RECT  2.16 40.635 92.88 40.905 ;
     RECT  2.16 41.175 92.88 41.445 ;
     RECT  2.16 41.715 92.88 41.985 ;
     RECT  2.16 42.255 92.88 42.525 ;
     RECT  2.16 42.795 92.88 43.065 ;
     RECT  2.16 43.335 92.88 43.605 ;
     RECT  2.16 43.875 92.88 44.145 ;
     RECT  2.16 44.415 92.88 44.685 ;
     RECT  2.16 44.955 92.88 45.225 ;
    LAYER M1 ;
     RECT  2.16 2.151 92.88 45.369 ;
    LAYER M2 ;
     RECT  0.103 38.412 0.139 38.43 ;
     RECT  0.139 38.412 2.16 38.736 ;
     RECT  0.103 39.87 2.16 40.356 ;
     RECT  2.16 2.151 3.055 45.369 ;
     RECT  3.055 2.151 3.847 45.414 ;
     RECT  3.847 2.151 6.835 45.45 ;
     RECT  6.835 2.151 6.871 45.486 ;
     RECT  6.871 2.151 7.591 45.558 ;
     RECT  10.651 46.701 10.751 46.719 ;
     RECT  7.591 2.151 11.075 45.594 ;
     RECT  11.075 2.151 11.803 45.558 ;
     RECT  11.803 2.151 14.783 45.594 ;
     RECT  14.783 2.151 16.619 45.558 ;
     RECT  16.619 2.151 18.859 45.486 ;
     RECT  18.859 2.151 23.855 45.522 ;
     RECT  24.619 46.701 24.719 46.719 ;
     RECT  23.855 2.151 25.979 45.414 ;
     RECT  25.979 2.151 26.815 45.369 ;
     RECT  26.815 2.151 27.995 45.414 ;
     RECT  27.995 2.151 28.831 45.369 ;
     RECT  28.831 2.151 30.091 45.414 ;
     RECT  30.091 2.151 30.191 45.594 ;
     RECT  30.191 2.151 34.043 45.414 ;
     RECT  34.043 2.151 36.463 45.369 ;
     RECT  36.463 2.151 37.247 45.414 ;
     RECT  37.247 2.151 43.699 45.369 ;
     RECT  43.699 2.151 52.835 45.414 ;
     RECT  52.835 2.151 56.335 45.369 ;
     RECT  56.335 2.07 56.507 45.369 ;
     RECT  56.507 2.151 77.323 45.369 ;
     RECT  77.323 2.106 77.639 45.369 ;
     RECT  77.639 2.151 92.88 45.369 ;
    LAYER M3 ;
     RECT  52.38 0.043 52.398 0.091 ;
     RECT  39.168 0.091 45.378 0.139 ;
     RECT  46.152 0.091 46.17 0.139 ;
     RECT  48.348 0.091 48.546 0.139 ;
     RECT  49.284 0.091 57.474 0.139 ;
     RECT  58.392 0.091 76.374 0.139 ;
     RECT  39.168 0.139 46.17 0.571 ;
     RECT  47.088 0.091 47.106 0.571 ;
     RECT  48.348 0.139 57.474 0.571 ;
     RECT  39.168 0.571 46.242 1.147 ;
     RECT  35.388 0.091 38.142 1.723 ;
     RECT  39.168 1.147 46.278 1.723 ;
     RECT  47.088 0.571 47.142 1.723 ;
     RECT  48.132 0.571 57.474 1.723 ;
     RECT  58.392 0.139 76.518 1.723 ;
     RECT  77.508 0.091 89.586 1.723 ;
     RECT  39.096 1.723 47.25 1.771 ;
     RECT  48.132 1.723 57.546 1.771 ;
     RECT  58.32 1.723 76.554 1.771 ;
     RECT  77.508 1.723 89.622 1.771 ;
     RECT  39.096 1.771 76.698 2.101 ;
     RECT  77.508 1.771 89.766 2.101 ;
     RECT  35.28 1.723 38.25 2.143 ;
     RECT  34.815 2.143 38.25 2.219 ;
     RECT  39.096 2.101 89.766 2.219 ;
     RECT  39.168 2.219 76.518 2.255 ;
     RECT  2.415 2.143 2.505 2.413 ;
     RECT  7.815 2.143 7.905 2.413 ;
     RECT  13.215 2.143 13.305 2.413 ;
     RECT  18.615 2.143 18.705 2.413 ;
     RECT  24.015 2.143 24.105 2.413 ;
     RECT  29.415 2.143 29.505 2.413 ;
     RECT  34.815 2.219 38.142 2.525 ;
     RECT  39.168 2.255 57.474 2.525 ;
     RECT  58.392 2.255 76.518 2.525 ;
     RECT  77.508 2.219 89.586 2.525 ;
     RECT  83.415 2.525 83.754 2.597 ;
     RECT  35.856 2.525 36.414 2.759 ;
     RECT  41.22 2.525 41.778 2.759 ;
     RECT  44.712 2.525 50.13 2.759 ;
     RECT  51.015 2.525 52.398 2.759 ;
     RECT  54.396 2.525 54.81 2.759 ;
     RECT  56.124 2.525 56.697 2.759 ;
     RECT  61.776 2.525 62.874 2.759 ;
     RECT  66.276 2.525 66.294 2.759 ;
     RECT  67.176 2.525 67.497 2.759 ;
     RECT  69.3 2.525 69.318 2.759 ;
     RECT  70.056 2.525 70.074 2.759 ;
     RECT  76.212 2.525 76.23 2.759 ;
     RECT  77.976 2.525 80.874 2.759 ;
     RECT  81.936 2.525 81.954 2.759 ;
     RECT  84.564 2.525 85.41 2.759 ;
     RECT  58.356 3.001 58.374 3.109 ;
     RECT  57.42 2.525 57.474 3.181 ;
     RECT  58.284 3.109 58.374 3.181 ;
     RECT  54.72 2.759 54.81 3.209 ;
     RECT  74.664 2.525 74.682 3.209 ;
     RECT  52.38 2.759 52.398 3.271 ;
     RECT  61.815 2.759 62.874 3.271 ;
     RECT  78.012 2.759 80.37 3.299 ;
     RECT  78.012 3.299 80.262 3.341 ;
     RECT  42.66 2.525 42.75 3.415 ;
     RECT  56.16 2.759 56.697 3.415 ;
     RECT  57.42 3.181 58.374 3.415 ;
     RECT  59.184 2.525 59.202 3.415 ;
     RECT  52.38 3.271 52.542 3.451 ;
     RECT  56.16 3.415 59.202 3.451 ;
     RECT  51.015 2.759 51.297 3.577 ;
     RECT  52.38 3.451 52.938 3.577 ;
     RECT  53.784 3.451 53.802 3.577 ;
     RECT  64.08 3.577 64.098 3.613 ;
     RECT  64.836 3.577 64.854 3.613 ;
     RECT  60.408 3.451 60.426 3.649 ;
     RECT  61.815 3.271 63.306 3.649 ;
     RECT  43.596 2.525 43.65 3.691 ;
     RECT  44.964 2.759 50.13 3.691 ;
     RECT  39.312 3.541 39.33 3.721 ;
     RECT  40.215 2.525 40.497 3.721 ;
     RECT  51.015 3.577 53.802 3.721 ;
     RECT  64.08 3.613 64.854 3.721 ;
     RECT  56.16 3.451 59.562 3.811 ;
     RECT  60.408 3.649 63.306 3.811 ;
     RECT  78.015 3.341 80.262 3.839 ;
     RECT  42.66 3.415 42.786 3.847 ;
     RECT  43.596 3.691 50.13 3.847 ;
     RECT  55.188 3.613 55.35 3.919 ;
     RECT  56.16 3.811 63.306 3.919 ;
     RECT  51.015 3.721 54.126 3.955 ;
     RECT  55.188 3.919 63.306 3.955 ;
     RECT  51.015 3.955 63.306 3.983 ;
     RECT  78.015 3.839 80.226 4.109 ;
     RECT  66.42 4.081 66.438 4.153 ;
     RECT  42.66 3.847 50.13 4.225 ;
     RECT  59.904 3.983 63.306 4.225 ;
     RECT  64.08 3.721 65.07 4.225 ;
     RECT  74.664 3.991 74.682 4.253 ;
     RECT  41.328 2.759 41.778 4.261 ;
     RECT  42.66 4.225 50.238 4.261 ;
     RECT  66.384 4.153 66.438 4.261 ;
     RECT  78.015 4.109 79.866 4.289 ;
     RECT  72.615 2.525 72.897 4.351 ;
     RECT  41.328 4.261 50.238 4.379 ;
     RECT  74.736 4.261 74.754 4.379 ;
     RECT  72.036 4.351 72.897 4.397 ;
     RECT  50.22 4.379 50.238 4.415 ;
     RECT  67.215 2.759 67.497 4.459 ;
     RECT  59.904 4.225 65.07 4.495 ;
     RECT  66.312 4.261 66.438 4.495 ;
     RECT  70.704 4.363 70.722 4.495 ;
     RECT  59.904 4.495 65.394 4.531 ;
     RECT  66.204 4.495 66.438 4.531 ;
     RECT  67.215 4.459 68.058 4.531 ;
     RECT  70.488 4.495 70.722 4.559 ;
     RECT  51.015 3.983 59.166 4.621 ;
     RECT  70.488 4.559 70.686 4.649 ;
     RECT  70.488 4.649 70.506 4.685 ;
     RECT  34.815 2.525 35.097 4.765 ;
     RECT  41.328 4.379 49.482 4.829 ;
     RECT  50.724 4.621 59.166 4.829 ;
     RECT  78.015 4.289 78.354 4.919 ;
     RECT  51.015 4.829 59.166 5.071 ;
     RECT  59.904 4.531 68.058 5.071 ;
     RECT  79.272 4.289 79.866 5.099 ;
     RECT  41.328 4.829 49.446 5.189 ;
     RECT  34.344 4.765 35.097 5.341 ;
     RECT  51.015 5.071 68.058 5.611 ;
     RECT  51.015 5.611 68.346 5.803 ;
     RECT  39.312 3.721 40.497 5.881 ;
     RECT  41.328 5.189 47.754 5.881 ;
     RECT  51.015 5.803 68.454 5.909 ;
     RECT  39.312 5.881 47.754 5.999 ;
     RECT  51.015 5.909 68.31 6.283 ;
     RECT  48.924 5.189 49.446 6.511 ;
     RECT  50.472 6.283 68.31 6.511 ;
     RECT  34.128 5.341 35.097 6.583 ;
     RECT  35.856 2.759 35.874 6.583 ;
     RECT  18.615 2.413 18.897 6.619 ;
     RECT  38.448 6.043 38.466 6.655 ;
     RECT  39.312 5.999 47.682 6.655 ;
     RECT  48.924 6.511 68.31 6.691 ;
     RECT  18.615 6.619 19.854 6.781 ;
     RECT  17.928 6.781 19.854 6.808 ;
     RECT  48.924 6.691 68.598 6.808 ;
     RECT  20.916 6.691 20.934 6.809 ;
     RECT  69.444 6.961 69.462 7.079 ;
     RECT  17.172 6.781 17.19 7.087 ;
     RECT  17.928 6.808 19.962 7.087 ;
     RECT  38.448 6.655 47.682 7.123 ;
     RECT  48.528 6.808 68.598 7.123 ;
     RECT  17.172 7.087 19.962 7.195 ;
     RECT  38.448 7.123 68.598 7.195 ;
     RECT  17.1 7.195 19.962 7.321 ;
     RECT  14.832 7.393 14.85 7.501 ;
     RECT  70.668 7.429 70.686 7.501 ;
     RECT  13.215 2.413 13.497 7.591 ;
     RECT  14.544 7.501 14.85 7.627 ;
     RECT  13.176 7.591 13.497 7.663 ;
     RECT  14.544 7.627 16.362 7.663 ;
     RECT  70.596 7.501 70.686 7.699 ;
     RECT  70.596 7.699 71.406 7.735 ;
     RECT  13.176 7.663 16.362 7.771 ;
     RECT  17.1 7.321 20.07 7.771 ;
     RECT  70.596 7.735 71.694 7.771 ;
     RECT  72.615 4.397 72.897 7.771 ;
     RECT  13.176 7.771 20.07 7.861 ;
     RECT  13.176 7.861 20.466 7.897 ;
     RECT  76.32 7.501 76.338 7.933 ;
     RECT  76.32 7.933 76.77 8.005 ;
     RECT  38.196 7.195 69.138 8.203 ;
     RECT  74.124 8.041 74.142 8.203 ;
     RECT  38.196 8.203 69.786 8.239 ;
     RECT  70.596 7.771 72.897 8.239 ;
     RECT  34.128 6.583 35.874 8.275 ;
     RECT  38.196 8.239 72.897 8.275 ;
     RECT  73.692 8.203 74.142 8.275 ;
     RECT  24.015 2.413 24.297 8.311 ;
     RECT  13.14 7.897 20.466 8.401 ;
     RECT  21.348 8.311 21.366 8.401 ;
     RECT  23.868 8.311 24.786 8.401 ;
     RECT  38.196 8.275 74.142 8.437 ;
     RECT  13.14 8.401 21.366 8.473 ;
     RECT  23.472 8.401 24.894 8.473 ;
     RECT  22.428 8.437 22.554 8.509 ;
     RECT  13.104 8.473 21.366 8.545 ;
     RECT  22.428 8.509 22.662 8.545 ;
     RECT  23.472 8.473 25.074 8.545 ;
     RECT  33.66 8.275 35.874 8.545 ;
     RECT  25.848 8.437 25.938 8.581 ;
     RECT  38.196 8.437 74.502 8.581 ;
     RECT  13.104 8.545 25.074 8.671 ;
     RECT  25.848 8.581 26.046 8.671 ;
     RECT  26.856 8.581 26.874 8.671 ;
     RECT  12.708 8.671 25.074 8.699 ;
     RECT  33.624 8.545 35.874 8.707 ;
     RECT  33.624 8.707 35.91 8.815 ;
     RECT  17.064 8.699 25.074 8.851 ;
     RECT  33.588 8.815 35.91 8.851 ;
     RECT  36.648 8.779 36.666 8.851 ;
     RECT  76.32 8.005 76.842 8.941 ;
     RECT  17.064 8.851 25.11 8.977 ;
     RECT  25.848 8.671 26.874 8.977 ;
     RECT  76.32 8.941 77.058 8.977 ;
     RECT  33.588 8.851 36.666 9.005 ;
     RECT  33.588 9.005 35.982 9.013 ;
     RECT  38.196 8.581 74.97 9.013 ;
     RECT  75.852 8.977 77.058 9.013 ;
     RECT  33.012 9.013 35.982 9.085 ;
     RECT  12.708 8.699 16.254 9.319 ;
     RECT  17.064 8.977 26.874 9.355 ;
     RECT  32.904 9.085 35.982 9.391 ;
     RECT  32.832 9.391 35.982 9.545 ;
     RECT  36.828 9.121 37.134 9.589 ;
     RECT  38.196 9.013 77.058 9.589 ;
     RECT  32.832 9.545 35.946 9.625 ;
     RECT  17.064 9.355 27.162 9.787 ;
     RECT  12.564 9.319 16.254 9.823 ;
     RECT  11.592 9.085 11.61 9.931 ;
     RECT  12.348 9.823 16.254 9.931 ;
     RECT  17.064 9.787 27.594 9.931 ;
     RECT  36.828 9.589 77.058 9.931 ;
     RECT  36.72 9.931 77.238 10.085 ;
     RECT  32.724 9.625 35.946 10.435 ;
     RECT  37.008 10.085 77.238 10.597 ;
     RECT  37.008 10.597 77.274 10.633 ;
     RECT  78.015 4.919 78.297 10.633 ;
     RECT  11.592 9.931 27.594 10.669 ;
     RECT  11.592 10.669 27.666 10.975 ;
     RECT  9.972 9.895 9.99 11.137 ;
     RECT  11.232 10.975 27.846 11.209 ;
     RECT  9.864 11.137 9.99 11.213 ;
     RECT  10.872 11.209 27.846 11.245 ;
     RECT  9.9 11.213 9.99 11.281 ;
     RECT  32.724 10.435 36.054 11.281 ;
     RECT  37.008 10.633 78.297 11.281 ;
     RECT  10.872 11.245 28.278 11.371 ;
     RECT  9.9 11.281 10.026 11.479 ;
     RECT  10.872 11.371 28.638 11.551 ;
     RECT  29.415 2.413 29.697 11.551 ;
     RECT  9.9 11.479 10.098 11.641 ;
     RECT  10.872 11.551 29.697 11.641 ;
     RECT  32.724 11.281 78.297 11.849 ;
     RECT  9.9 11.641 29.697 11.939 ;
     RECT  31.644 12.055 31.662 12.209 ;
     RECT  9.972 11.939 29.697 12.245 ;
     RECT  32.724 11.849 44.118 12.325 ;
     RECT  10.008 12.245 29.697 12.515 ;
     RECT  32.508 12.325 44.118 12.865 ;
     RECT  10.116 12.515 29.697 12.893 ;
     RECT  10.116 12.893 27.234 13.091 ;
     RECT  32.328 12.865 44.118 13.091 ;
     RECT  45.108 11.849 78.297 13.099 ;
     RECT  10.404 13.091 27.234 13.199 ;
     RECT  10.44 13.199 27.234 13.945 ;
     RECT  28.188 12.893 29.697 13.945 ;
     RECT  10.44 13.945 29.697 13.973 ;
     RECT  10.548 13.973 29.697 14.099 ;
     RECT  44.892 13.099 78.297 14.107 ;
     RECT  32.328 13.091 44.046 14.251 ;
     RECT  44.892 14.107 78.462 14.251 ;
     RECT  10.836 14.099 29.697 14.369 ;
     RECT  10.836 14.369 14.31 14.875 ;
     RECT  10.152 14.875 14.31 15.179 ;
     RECT  32.328 14.251 78.462 15.323 ;
     RECT  10.44 15.179 14.31 15.331 ;
     RECT  15.048 14.369 29.697 15.331 ;
     RECT  10.44 15.331 29.697 15.899 ;
     RECT  10.44 15.899 22.59 16.097 ;
     RECT  9.612 15.187 9.63 16.231 ;
     RECT  10.44 16.097 15.858 16.231 ;
     RECT  23.328 15.899 29.697 16.259 ;
     RECT  79.884 16.141 79.902 16.259 ;
     RECT  45.108 15.323 78.462 16.339 ;
     RECT  45.108 16.339 78.966 16.375 ;
     RECT  32.328 15.323 44.046 16.411 ;
     RECT  45.108 16.375 79.47 16.411 ;
     RECT  32.328 16.411 79.47 16.529 ;
     RECT  9.612 16.231 15.858 16.645 ;
     RECT  16.596 16.097 22.59 16.645 ;
     RECT  23.328 16.259 26.694 16.645 ;
     RECT  32.328 16.529 79.398 16.835 ;
     RECT  9.252 16.645 15.858 16.951 ;
     RECT  16.596 16.645 26.694 16.951 ;
     RECT  9.252 16.951 26.694 16.979 ;
     RECT  10.44 16.979 26.694 17.141 ;
     RECT  10.548 17.141 26.694 17.149 ;
     RECT  27.432 16.259 29.697 17.149 ;
     RECT  32.328 16.835 78.462 17.411 ;
     RECT  45.108 17.411 78.462 17.617 ;
     RECT  79.236 16.835 79.398 17.617 ;
     RECT  45.108 17.617 79.398 17.761 ;
     RECT  45.108 17.761 79.794 17.879 ;
     RECT  10.548 17.149 29.697 17.923 ;
     RECT  10.476 17.923 29.697 18.257 ;
     RECT  9.252 16.979 9.63 18.391 ;
     RECT  7.815 2.413 8.097 18.499 ;
     RECT  8.82 18.391 9.63 18.499 ;
     RECT  45.108 17.879 79.29 18.769 ;
     RECT  80.136 18.535 80.154 18.769 ;
     RECT  32.328 17.411 44.046 18.805 ;
     RECT  45.108 18.769 80.154 18.805 ;
     RECT  10.476 18.257 22.806 18.841 ;
     RECT  32.328 18.805 80.154 18.959 ;
     RECT  7.815 18.499 9.63 18.967 ;
     RECT  10.44 18.841 22.806 18.967 ;
     RECT  7.815 18.967 22.806 19.003 ;
     RECT  7.632 19.003 22.806 19.075 ;
     RECT  23.544 18.257 29.697 19.075 ;
     RECT  7.632 19.075 29.697 19.111 ;
     RECT  7.524 19.111 29.697 19.345 ;
     RECT  37.224 18.959 80.154 19.769 ;
     RECT  37.224 19.769 79.686 19.805 ;
     RECT  32.328 18.959 36.486 19.921 ;
     RECT  37.224 19.805 79.506 19.921 ;
     RECT  6.624 19.003 6.642 20.047 ;
     RECT  7.38 19.345 29.697 20.047 ;
     RECT  32.328 19.921 79.506 20.191 ;
     RECT  31.752 20.191 79.506 20.309 ;
     RECT  5.868 20.059 5.886 20.345 ;
     RECT  31.752 20.309 78.606 20.417 ;
     RECT  31.752 20.417 78.498 20.425 ;
     RECT  6.624 20.047 29.697 20.461 ;
     RECT  79.38 20.309 79.506 20.731 ;
     RECT  79.38 20.731 79.902 20.885 ;
     RECT  79.38 20.885 79.578 21.091 ;
     RECT  5.976 20.461 29.697 21.227 ;
     RECT  31.14 20.425 78.498 21.235 ;
     RECT  79.236 21.091 79.578 21.389 ;
     RECT  31.068 21.235 78.498 21.397 ;
     RECT  79.236 21.389 79.398 21.397 ;
     RECT  5.976 21.227 6.642 22.027 ;
     RECT  7.38 21.227 29.697 22.027 ;
     RECT  31.068 21.397 79.398 22.073 ;
     RECT  5.976 22.027 29.697 22.081 ;
     RECT  79.272 22.073 79.398 22.171 ;
     RECT  5.904 22.081 30.222 22.199 ;
     RECT  79.272 22.171 79.47 22.253 ;
     RECT  5.976 22.199 30.222 22.279 ;
     RECT  31.068 22.073 78.534 22.279 ;
     RECT  79.272 22.253 79.398 23.125 ;
     RECT  79.272 23.125 79.434 23.161 ;
     RECT  79.272 23.161 79.902 23.279 ;
     RECT  5.976 22.279 78.534 23.359 ;
     RECT  79.272 23.279 79.614 23.359 ;
     RECT  5.976 23.359 79.614 23.927 ;
     RECT  5.976 23.927 78.93 24.781 ;
     RECT  5.976 24.781 79.182 25.051 ;
     RECT  5.904 25.051 79.182 25.321 ;
     RECT  4.932 22.009 4.95 25.411 ;
     RECT  5.832 25.321 79.398 25.661 ;
     RECT  5.868 25.661 79.398 25.709 ;
     RECT  4.32 25.411 4.95 25.753 ;
     RECT  5.976 25.709 79.398 25.979 ;
     RECT  5.976 25.979 79.002 26.123 ;
     RECT  5.976 26.123 78.966 26.357 ;
     RECT  44.46 26.357 78.966 26.941 ;
     RECT  5.976 26.357 43.182 27.211 ;
     RECT  44.46 26.941 79.686 27.329 ;
     RECT  44.46 27.329 79.182 27.365 ;
     RECT  5.976 27.211 43.29 27.373 ;
     RECT  44.46 27.365 78.966 27.373 ;
     RECT  5.976 27.373 78.966 27.401 ;
     RECT  5.976 27.401 78.498 28.301 ;
     RECT  3.672 25.753 4.95 29.101 ;
     RECT  3.672 29.101 5.022 29.191 ;
     RECT  5.976 28.301 78.462 29.191 ;
     RECT  3.672 29.191 78.462 29.525 ;
     RECT  3.672 29.525 78.297 30.029 ;
     RECT  44.424 30.029 78.297 30.173 ;
     RECT  3.672 30.029 43.686 30.955 ;
     RECT  3.672 30.955 43.938 31.117 ;
     RECT  44.676 30.173 78.297 31.117 ;
     RECT  2.415 2.413 2.697 31.927 ;
     RECT  3.672 31.117 78.297 31.927 ;
     RECT  2.415 31.927 78.297 31.997 ;
     RECT  3.528 31.997 78.297 32.801 ;
     RECT  3.528 32.801 76.374 32.909 ;
     RECT  74.916 32.909 76.374 32.999 ;
     RECT  3.528 32.909 74.07 33.071 ;
     RECT  74.916 32.999 75.294 33.143 ;
     RECT  76.032 32.999 76.374 33.341 ;
     RECT  77.292 32.801 78.297 33.341 ;
     RECT  74.988 33.143 75.294 33.413 ;
     RECT  76.356 33.341 76.374 33.449 ;
     RECT  3.528 33.071 73.89 33.539 ;
     RECT  3.528 33.539 73.53 33.629 ;
     RECT  71.244 33.629 73.53 33.809 ;
     RECT  75.276 33.413 75.294 33.989 ;
     RECT  2.415 31.997 2.697 34.075 ;
     RECT  3.528 33.629 70.182 34.075 ;
     RECT  2.415 34.075 70.182 34.079 ;
     RECT  71.244 33.809 73.458 34.079 ;
     RECT  2.415 34.079 69.894 34.115 ;
     RECT  71.244 34.079 71.478 34.187 ;
     RECT  71.46 34.187 71.478 34.205 ;
     RECT  72.216 34.079 73.458 34.349 ;
     RECT  72.216 34.349 72.954 34.385 ;
     RECT  3.42 34.115 69.894 34.619 ;
     RECT  3.42 34.619 69.462 34.889 ;
     RECT  3.42 34.889 69.39 34.961 ;
     RECT  2.415 34.115 2.697 35.473 ;
     RECT  3.42 34.961 69.318 35.473 ;
     RECT  2.415 35.473 69.318 35.807 ;
     RECT  68.616 35.807 69.318 35.843 ;
     RECT  2.415 35.807 67.842 35.879 ;
     RECT  2.415 35.879 67.698 35.969 ;
     RECT  2.415 35.969 67.497 36.239 ;
     RECT  42.48 36.239 67.497 36.347 ;
     RECT  42.516 36.347 67.497 36.545 ;
     RECT  66.24 36.545 66.258 36.581 ;
     RECT  42.516 36.545 64.998 36.779 ;
     RECT  69.3 35.843 69.318 36.779 ;
     RECT  42.516 36.779 64.386 36.887 ;
     RECT  42.516 36.887 64.35 36.923 ;
     RECT  42.516 36.923 62.874 37.157 ;
     RECT  2.415 36.239 41.742 37.165 ;
     RECT  42.516 37.157 62.622 37.165 ;
     RECT  2.415 37.165 62.622 37.193 ;
     RECT  2.415 37.193 62.478 37.901 ;
     RECT  59.868 37.901 62.478 37.975 ;
     RECT  64.116 36.923 64.134 38.165 ;
     RECT  59.868 37.975 62.838 38.201 ;
     RECT  2.415 37.901 59.094 38.273 ;
     RECT  2.415 38.273 42.39 38.399 ;
     RECT  59.868 38.201 62.73 38.399 ;
     RECT  2.415 38.399 42.318 38.471 ;
     RECT  59.868 38.399 62.154 38.507 ;
     RECT  0.108 38.407 0.126 38.551 ;
     RECT  43.164 38.273 59.094 38.741 ;
     RECT  0.108 38.551 0.558 38.861 ;
     RECT  0.108 38.861 0.162 38.957 ;
     RECT  43.2 38.741 59.094 39.011 ;
     RECT  43.524 39.011 59.094 39.019 ;
     RECT  59.868 38.507 62.097 39.019 ;
     RECT  2.415 38.471 42.282 39.055 ;
     RECT  0.144 38.957 0.162 39.341 ;
     RECT  2.304 39.055 42.282 39.487 ;
     RECT  43.524 39.019 62.097 39.829 ;
     RECT  2.304 39.487 42.57 39.883 ;
     RECT  2.268 39.883 42.678 39.901 ;
     RECT  43.416 39.829 62.097 39.901 ;
     RECT  2.268 39.901 62.097 40.289 ;
     RECT  43.344 40.289 62.097 40.397 ;
     RECT  44.352 40.397 62.097 40.469 ;
     RECT  2.268 40.289 42.03 40.703 ;
     RECT  0.108 39.865 0.126 40.747 ;
     RECT  0.108 40.747 0.162 40.925 ;
     RECT  44.388 40.469 62.097 41.099 ;
     RECT  60.156 41.099 62.097 41.135 ;
     RECT  43.344 40.397 43.542 41.251 ;
     RECT  44.388 41.099 59.274 41.251 ;
     RECT  60.336 41.135 62.097 41.279 ;
     RECT  60.876 41.279 62.097 41.369 ;
     RECT  2.304 40.703 42.03 41.405 ;
     RECT  43.236 41.251 59.274 41.477 ;
     RECT  0.108 40.925 0.126 41.501 ;
     RECT  56.016 41.477 59.274 41.549 ;
     RECT  43.236 41.477 55.278 41.683 ;
     RECT  2.34 41.405 42.03 41.755 ;
     RECT  42.984 41.683 55.278 41.755 ;
     RECT  2.34 41.755 55.278 42.259 ;
     RECT  56.016 41.549 57.87 42.259 ;
     RECT  58.644 41.549 59.274 42.629 ;
     RECT  2.34 42.259 57.87 42.791 ;
     RECT  61.236 41.369 62.097 42.899 ;
     RECT  2.415 42.791 57.87 43.799 ;
     RECT  2.415 43.799 57.114 44.477 ;
     RECT  58.644 42.629 58.662 44.519 ;
     RECT  53.856 44.477 57.114 44.609 ;
     RECT  2.415 44.477 53.046 44.879 ;
     RECT  46.944 44.879 53.046 45.053 ;
     RECT  57.852 43.799 57.87 45.059 ;
     RECT  53.856 44.609 56.697 45.107 ;
     RECT  61.815 42.899 62.097 45.107 ;
     RECT  67.215 36.545 67.497 45.107 ;
     RECT  72.615 34.385 72.897 45.107 ;
     RECT  78.015 33.341 78.297 45.107 ;
     RECT  83.415 2.597 83.697 45.107 ;
     RECT  88.815 2.525 89.097 45.107 ;
     RECT  2.415 44.879 46.17 45.149 ;
     RECT  47.016 45.053 53.046 45.149 ;
     RECT  2.415 45.149 44.154 45.293 ;
     RECT  2.415 45.293 32.058 45.329 ;
     RECT  3.852 45.329 31.914 45.341 ;
     RECT  33.192 45.293 44.154 45.341 ;
     RECT  53.856 45.107 56.505 45.341 ;
     RECT  2.415 45.329 3.078 45.377 ;
     RECT  33.444 45.341 44.154 45.377 ;
     RECT  56.415 45.341 56.505 45.377 ;
     RECT  61.815 45.107 61.905 45.377 ;
     RECT  67.215 45.107 67.305 45.377 ;
     RECT  72.615 45.107 72.705 45.377 ;
     RECT  78.015 45.107 78.105 45.377 ;
     RECT  83.415 45.107 83.505 45.377 ;
     RECT  88.815 45.107 88.905 45.377 ;
     RECT  3.852 45.341 31.842 45.389 ;
     RECT  53.856 45.341 55.566 45.389 ;
     RECT  3.06 45.377 3.078 45.419 ;
     RECT  3.852 45.389 31.662 45.419 ;
     RECT  33.444 45.377 39.906 45.419 ;
     RECT  47.016 45.149 52.83 45.419 ;
     RECT  3.852 45.419 28.242 45.437 ;
     RECT  29.016 45.419 31.662 45.437 ;
     RECT  3.852 45.437 20.142 45.455 ;
     RECT  29.304 45.437 31.662 45.485 ;
     RECT  44.964 45.149 46.17 45.485 ;
     RECT  4.14 45.455 20.142 45.491 ;
     RECT  20.916 45.437 28.242 45.527 ;
     RECT  41.004 45.377 44.154 45.533 ;
     RECT  44.964 45.485 46.062 45.533 ;
     RECT  4.14 45.491 14.85 45.563 ;
     RECT  15.696 45.491 20.142 45.581 ;
     RECT  24.156 45.527 28.242 45.581 ;
     RECT  30.096 45.485 31.662 45.581 ;
     RECT  33.444 45.419 36.018 45.581 ;
     RECT  41.004 45.533 43.146 45.581 ;
     RECT  43.884 45.533 44.154 45.581 ;
     RECT  44.964 45.533 44.982 45.581 ;
     RECT  46.044 45.533 46.062 45.581 ;
     RECT  47.016 45.419 52.29 45.581 ;
     RECT  55.26 45.389 55.566 45.581 ;
     RECT  4.14 45.563 14.778 45.599 ;
     RECT  30.096 45.581 30.618 45.599 ;
     RECT  24.156 45.581 25.614 45.629 ;
     RECT  50.76 45.581 50.778 45.629 ;
     RECT  24.264 45.629 25.614 45.677 ;
     RECT  4.14 45.599 14.346 45.773 ;
     RECT  10.26 45.773 14.346 45.821 ;
     RECT  4.14 45.773 9.018 45.869 ;
     RECT  4.32 45.869 9.018 45.917 ;
     RECT  4.32 45.917 7.326 45.965 ;
     RECT  6.084 45.965 7.326 46.013 ;
     RECT  6.084 46.013 7.11 46.061 ;
     RECT  36.972 45.419 39.906 46.061 ;
     RECT  8.136 45.917 9.018 46.109 ;
     RECT  36.972 46.061 37.098 46.109 ;
     RECT  6.192 46.061 7.11 46.157 ;
     RECT  10.656 45.821 14.346 46.157 ;
     RECT  10.656 46.157 12.582 46.205 ;
     RECT  15.984 45.581 16.722 46.205 ;
     RECT  47.844 45.581 47.862 46.205 ;
     RECT  48.996 45.581 49.518 46.205 ;
     RECT  55.26 45.581 55.278 46.205 ;
     RECT  13.392 46.157 14.346 46.397 ;
     RECT  4.32 45.965 5.022 46.445 ;
     RECT  4.392 46.445 5.022 46.493 ;
     RECT  10.656 46.205 12.366 46.493 ;
     RECT  38.412 46.061 39.906 46.493 ;
     RECT  4.68 46.493 5.022 46.541 ;
     RECT  11.772 46.493 12.366 46.541 ;
     RECT  37.008 46.109 37.098 46.541 ;
     RECT  5.004 46.541 5.022 46.589 ;
     RECT  13.464 46.397 14.346 46.589 ;
     RECT  38.952 46.493 39.906 46.589 ;
     RECT  6.192 46.157 7.074 46.637 ;
     RECT  35.784 45.581 36.018 46.637 ;
     RECT  6.516 46.637 7.074 46.685 ;
     RECT  36 46.637 36.018 46.685 ;
     RECT  10.656 46.493 10.998 46.724 ;
     RECT  10.692 46.724 10.998 46.733 ;
     RECT  11.88 46.541 12.366 46.733 ;
     RECT  13.464 46.589 13.626 46.733 ;
     RECT  38.952 46.589 39.69 46.733 ;
     RECT  12.06 46.733 12.366 46.781 ;
     RECT  13.464 46.733 13.482 46.781 ;
     RECT  17.784 45.581 18.126 46.781 ;
     RECT  20.916 45.527 23.382 46.781 ;
     RECT  24.444 45.677 25.614 46.781 ;
     RECT  26.784 45.581 26.802 46.781 ;
     RECT  28.224 45.581 28.242 46.781 ;
     RECT  33.444 45.581 34.65 46.781 ;
     RECT  41.004 45.581 41.022 46.781 ;
     RECT  49.068 46.205 49.518 46.781 ;
     RECT  53.856 45.389 53.874 46.781 ;
     RECT  12.348 46.781 12.366 46.829 ;
     RECT  16.272 46.205 16.722 46.829 ;
     RECT  17.784 46.781 17.802 46.829 ;
     RECT  21.204 46.781 21.654 46.829 ;
     RECT  22.464 46.781 23.166 46.829 ;
     RECT  33.768 46.781 34.11 46.829 ;
     RECT  16.704 46.829 16.722 46.877 ;
     RECT  21.204 46.829 21.222 46.877 ;
     RECT  23.148 46.829 23.166 46.877 ;
     RECT  24.444 46.781 24.714 46.877 ;
     RECT  30.132 45.599 30.618 46.877 ;
     RECT  34.092 46.829 34.11 46.877 ;
     RECT  24.444 46.877 24.462 46.925 ;
     RECT  10.728 46.733 10.998 47.213 ;
     RECT  30.6 46.877 30.618 47.309 ;
     RECT  15.516 47.227 15.534 47.323 ;
     RECT  10.728 47.213 10.854 47.357 ;
     RECT  15.516 47.323 15.714 47.357 ;
     RECT  8.676 46.109 9.018 47.405 ;
     RECT  10.836 47.357 10.854 47.405 ;
     RECT  31.644 45.581 31.662 47.405 ;
     RECT  49.5 46.781 49.518 47.405 ;
     RECT  50.652 47.275 50.67 47.405 ;
     RECT  51.732 45.581 51.75 47.405 ;
     RECT  9 47.405 9.018 47.453 ;
     RECT  15.588 47.357 15.714 47.453 ;
     RECT  7.056 46.685 7.074 47.501 ;
     RECT  15.588 47.453 15.606 47.501 ;
     RECT  32.616 47.371 32.634 47.501 ;
     RECT  37.08 46.541 37.098 47.501 ;
     RECT  38.952 46.733 38.97 47.501 ;
     RECT  43.632 47.371 43.65 47.501 ;
    LAYER M4 ;
     RECT  0.06 38.736 0.097 41.352 ;
     RECT  0.181 23.856 2.408 23.88 ;
     RECT  0.097 38.736 2.408 41.496 ;
     RECT  2.408 2.148 2.512 45.372 ;
     RECT  2.512 2.418 2.704 45.102 ;
     RECT  2.704 34.08 3.443 34.344 ;
     RECT  3.443 34.32 3.593 34.344 ;
     RECT  2.704 31.968 3.913 31.992 ;
     RECT  2.704 32.976 3.913 33 ;
     RECT  2.704 43.008 3.913 43.32 ;
     RECT  2.704 37.584 3.949 37.608 ;
     RECT  2.704 38.64 3.949 41.496 ;
     RECT  3.913 31.968 4.133 33 ;
     RECT  4.129 45.84 4.309 45.864 ;
     RECT  4.309 35.184 4.381 35.208 ;
     RECT  4.345 36.288 4.381 36.312 ;
     RECT  4.309 45.84 4.381 46.44 ;
     RECT  4.133 31.968 4.489 31.992 ;
     RECT  3.913 42.72 4.493 43.32 ;
     RECT  4.381 35.184 4.561 36.312 ;
     RECT  3.949 37.584 4.561 41.496 ;
     RECT  4.489 31.152 4.601 31.992 ;
     RECT  4.561 35.184 4.669 41.496 ;
     RECT  4.493 42.72 4.669 42.744 ;
     RECT  4.381 45.84 4.669 46.488 ;
     RECT  4.669 34.464 4.781 42.744 ;
     RECT  4.669 45.84 4.993 46.536 ;
     RECT  4.133 32.976 5.029 33 ;
     RECT  4.957 34.032 5.029 34.056 ;
     RECT  4.781 35.184 5.249 42.744 ;
     RECT  5.249 35.424 5.285 42.744 ;
     RECT  5.285 37.104 5.315 42.744 ;
     RECT  2.704 44.592 5.353 44.616 ;
     RECT  5.353 43.872 5.393 44.616 ;
     RECT  5.029 32.976 5.825 34.056 ;
     RECT  4.597 29.232 5.929 29.256 ;
     RECT  5.929 29.232 5.965 29.304 ;
     RECT  5.315 38.16 5.965 42.744 ;
     RECT  5.393 43.872 5.965 43.896 ;
     RECT  5.965 38.16 6.005 43.896 ;
     RECT  5.965 29.232 6.037 30.072 ;
     RECT  5.315 37.104 6.041 37.128 ;
     RECT  6.005 38.16 6.113 43.368 ;
     RECT  4.993 45.84 6.181 46.584 ;
     RECT  5.285 35.424 6.217 36.12 ;
     RECT  6.181 45.84 6.505 46.632 ;
     RECT  6.217 34.752 6.581 36.12 ;
     RECT  6.037 29.232 6.757 30.6 ;
     RECT  2.704 23.856 6.793 23.88 ;
     RECT  5.857 20.064 6.829 20.088 ;
     RECT  6.101 21.12 6.829 21.144 ;
     RECT  6.793 23.856 6.829 24.648 ;
     RECT  5.821 25.632 6.829 25.656 ;
     RECT  6.113 38.16 6.829 42.216 ;
     RECT  5.825 32.976 6.865 33.336 ;
     RECT  6.757 29.232 6.901 30.648 ;
     RECT  6.829 37.296 7.045 42.216 ;
     RECT  6.505 45.84 7.045 46.68 ;
     RECT  6.829 23.856 7.117 25.656 ;
     RECT  6.901 29.232 7.261 30.744 ;
     RECT  4.601 31.968 7.261 31.992 ;
     RECT  6.865 32.976 7.261 33.576 ;
     RECT  6.581 34.752 7.261 34.824 ;
     RECT  6.829 20.064 7.369 22.056 ;
     RECT  7.117 23.232 7.369 25.656 ;
     RECT  6.113 43.344 7.429 43.368 ;
     RECT  7.369 44.352 7.429 44.376 ;
     RECT  7.261 31.968 7.513 34.824 ;
     RECT  7.549 26.784 7.669 27.336 ;
     RECT  7.261 28.944 7.669 30.744 ;
     RECT  7.369 20.064 7.808 25.656 ;
     RECT  7.669 26.784 7.808 30.744 ;
     RECT  7.513 31.872 7.808 34.824 ;
     RECT  6.581 36.096 7.808 36.12 ;
     RECT  7.045 37.248 7.808 42.216 ;
     RECT  7.429 43.344 7.808 44.376 ;
     RECT  7.045 45.84 7.808 47.496 ;
     RECT  7.808 2.148 7.912 47.496 ;
     RECT  7.912 2.418 8.104 47.496 ;
     RECT  8.104 28.272 8.165 35.064 ;
     RECT  8.165 28.272 8.243 31.368 ;
     RECT  8.243 28.272 8.273 30.696 ;
     RECT  8.273 28.512 8.531 30.696 ;
     RECT  8.104 18.816 8.741 22.824 ;
     RECT  8.741 18.816 8.777 20.664 ;
     RECT  8.165 32.496 8.813 35.064 ;
     RECT  8.104 23.856 9.097 24.936 ;
     RECT  8.741 22.032 9.107 22.824 ;
     RECT  8.104 43.824 9.245 44.376 ;
     RECT  8.531 28.512 9.461 29.496 ;
     RECT  8.104 36.528 9.565 42.216 ;
     RECT  8.531 30.672 9.569 30.696 ;
     RECT  9.107 22.176 9.601 22.824 ;
     RECT  9.097 23.856 9.601 25.848 ;
     RECT  9.169 27.36 9.601 27.384 ;
     RECT  9.601 26.88 9.673 27.384 ;
     RECT  8.104 45.84 9.673 47.496 ;
     RECT  8.813 32.496 9.677 34.776 ;
     RECT  9.677 34.224 9.713 34.776 ;
     RECT  9.677 32.496 9.733 33.144 ;
     RECT  9.565 36.24 9.749 42.216 ;
     RECT  9.692 31.296 9.779 31.32 ;
     RECT  8.777 19.008 9.857 20.664 ;
     RECT  9.713 34.512 9.961 34.776 ;
     RECT  9.857 19.296 9.965 20.664 ;
     RECT  9.749 36.24 9.971 36.264 ;
     RECT  9.601 22.176 10.105 25.848 ;
     RECT  9.673 26.88 10.105 27.432 ;
     RECT  10.076 13.056 10.163 13.08 ;
     RECT  10.117 14.88 10.204 15.48 ;
     RECT  10.105 22.176 10.357 27.432 ;
     RECT  10.357 22.176 10.505 28.344 ;
     RECT  9.245 43.824 10.645 43.848 ;
     RECT  9.461 29.472 10.717 29.496 ;
     RECT  10.645 43.824 10.748 43.944 ;
     RECT  10.204 15.456 10.757 15.48 ;
     RECT  9.965 19.296 10.825 20.328 ;
     RECT  9.733 32.448 10.825 33.144 ;
     RECT  10.748 43.824 10.835 44.328 ;
     RECT  10.717 16.512 10.861 16.536 ;
     RECT  9.961 34.512 10.969 34.824 ;
     RECT  10.835 43.824 11.173 43.944 ;
     RECT  9.749 37.536 11.189 42.216 ;
     RECT  10.825 18.48 11.221 20.328 ;
     RECT  10.825 31.968 11.221 33.144 ;
     RECT  10.969 34.272 11.221 34.824 ;
     RECT  10.505 22.176 11.257 22.536 ;
     RECT  9.673 45.744 11.365 47.496 ;
     RECT  10.969 36.24 11.369 36.264 ;
     RECT  10.505 23.856 11.405 28.344 ;
     RECT  11.405 23.856 11.441 26.808 ;
     RECT  11.173 43.344 11.477 43.944 ;
     RECT  11.441 23.856 11.581 26.76 ;
     RECT  11.221 31.968 11.603 34.824 ;
     RECT  11.189 38.208 11.653 42.216 ;
     RECT  11.477 43.92 11.699 43.944 ;
     RECT  11.603 33.36 11.729 34.824 ;
     RECT  11.221 18.432 11.909 20.328 ;
     RECT  11.405 28.224 11.941 28.344 ;
     RECT  11.729 33.648 11.941 34.824 ;
     RECT  11.941 28.224 11.945 28.44 ;
     RECT  11.365 45.312 11.977 47.496 ;
     RECT  11.581 23.76 12.017 26.76 ;
     RECT  12.017 24.912 12.053 26.76 ;
     RECT  11.257 21.648 12.085 22.536 ;
     RECT  10.861 16.272 12.121 16.536 ;
     RECT  12.013 30.864 12.121 30.888 ;
     RECT  11.603 31.968 12.121 32.28 ;
     RECT  11.941 33.648 12.161 35.208 ;
     RECT  10.717 29.472 12.193 29.832 ;
     RECT  12.121 30.864 12.193 32.28 ;
     RECT  11.909 18.48 12.373 20.328 ;
     RECT  12.085 21.456 12.373 22.536 ;
     RECT  12.445 10.032 12.481 10.056 ;
     RECT  10.897 12.528 12.481 12.552 ;
     RECT  12.481 10.032 12.517 10.152 ;
     RECT  9.853 11.184 12.517 11.208 ;
     RECT  12.481 14.448 12.517 14.472 ;
     RECT  12.337 37.056 12.553 37.08 ;
     RECT  12.517 14.448 12.589 14.664 ;
     RECT  12.121 16.272 12.589 17.016 ;
     RECT  12.373 18.48 12.589 22.536 ;
     RECT  12.553 36.864 12.589 37.08 ;
     RECT  11.653 38.208 12.589 42.84 ;
     RECT  12.589 36.864 12.625 42.84 ;
     RECT  12.517 10.032 12.697 11.208 ;
     RECT  12.481 12.528 12.697 12.792 ;
     RECT  12.589 18.48 12.697 22.776 ;
     RECT  12.017 23.76 12.697 23.88 ;
     RECT  11.945 28.32 12.697 28.44 ;
     RECT  12.193 29.472 12.697 32.28 ;
     RECT  12.697 28.32 12.805 32.28 ;
     RECT  12.697 10.032 12.901 12.792 ;
     RECT  12.805 28.32 12.949 32.328 ;
     RECT  12.589 14.448 12.985 17.016 ;
     RECT  12.697 18.48 12.985 23.88 ;
     RECT  12.901 9.936 13.021 12.792 ;
     RECT  12.985 14.448 13.021 23.88 ;
     RECT  13.021 9.936 13.057 23.88 ;
     RECT  12.053 25.44 13.093 25.464 ;
     RECT  12.053 26.544 13.093 26.76 ;
     RECT  12.161 34.272 13.093 35.208 ;
     RECT  12.625 36.816 13.093 42.84 ;
     RECT  11.977 45.024 13.093 47.496 ;
     RECT  13.165 7.632 13.208 7.656 ;
     RECT  13.057 9.936 13.208 24.408 ;
     RECT  13.093 25.44 13.208 26.76 ;
     RECT  12.949 28.176 13.208 32.328 ;
     RECT  13.093 34.272 13.208 42.84 ;
     RECT  13.093 44.976 13.208 47.496 ;
     RECT  13.208 2.148 13.312 47.496 ;
     RECT  13.312 2.418 13.504 47.496 ;
     RECT  13.504 10.128 13.601 12.36 ;
     RECT  13.504 15.984 13.601 26.856 ;
     RECT  13.504 13.344 13.619 14.952 ;
     RECT  13.504 28.128 13.673 29.352 ;
     RECT  13.673 28.128 13.781 29.016 ;
     RECT  13.601 15.984 13.853 17.064 ;
     RECT  13.619 13.344 13.997 14.232 ;
     RECT  13.504 30.432 14.249 33.096 ;
     RECT  13.504 34.176 14.321 47.496 ;
     RECT  13.601 18.288 14.357 26.856 ;
     RECT  14.249 32.304 14.429 33.096 ;
     RECT  14.357 19.104 14.573 26.856 ;
     RECT  14.573 19.248 14.645 26.856 ;
     RECT  13.997 14.208 14.681 14.232 ;
     RECT  14.645 19.248 14.681 22.584 ;
     RECT  13.853 16.176 14.78 17.064 ;
     RECT  13.601 10.848 14.821 12.36 ;
     RECT  14.78 16.176 14.821 17.112 ;
     RECT  14.249 30.432 14.857 31.32 ;
     RECT  14.645 23.76 14.861 26.856 ;
     RECT  14.321 34.368 14.861 47.496 ;
     RECT  14.821 16.176 14.867 18.072 ;
     RECT  13.781 28.128 14.897 28.776 ;
     RECT  14.821 10.32 14.933 12.456 ;
     RECT  14.861 34.368 14.969 43.032 ;
     RECT  14.933 10.32 15.041 11.976 ;
     RECT  14.867 16.176 15.073 17.064 ;
     RECT  13.504 7.632 15.145 8.856 ;
     RECT  15.145 7.632 15.293 9.144 ;
     RECT  15.073 15.216 15.293 17.064 ;
     RECT  14.969 43.008 15.299 43.032 ;
     RECT  14.861 23.76 15.329 24.888 ;
     RECT  14.897 28.128 15.365 28.728 ;
     RECT  15.293 15.312 15.473 17.064 ;
     RECT  14.857 30.048 15.509 31.32 ;
     RECT  15.473 15.6 15.545 17.064 ;
     RECT  14.969 34.368 15.617 41.928 ;
     RECT  14.861 44.112 15.617 47.496 ;
     RECT  14.861 26.112 15.685 26.856 ;
     RECT  15.365 28.128 15.685 28.152 ;
     RECT  15.545 15.744 15.689 17.064 ;
     RECT  15.617 44.112 15.725 47.448 ;
     RECT  15.725 44.112 15.769 47.352 ;
     RECT  15.041 10.32 15.833 11.4 ;
     RECT  15.509 30.432 15.833 31.32 ;
     RECT  15.617 35.184 16.013 41.928 ;
     RECT  15.833 11.376 16.121 11.4 ;
     RECT  14.429 32.304 16.261 32.952 ;
     RECT  15.769 44.112 16.307 47.256 ;
     RECT  15.293 7.632 16.373 8.472 ;
     RECT  16.307 44.112 16.403 46.872 ;
     RECT  14.681 19.296 16.477 22.584 ;
     RECT  15.329 23.76 16.477 23.784 ;
     RECT  15.685 26.112 16.513 28.152 ;
     RECT  16.477 19.296 16.549 23.784 ;
     RECT  14.867 18.048 16.595 18.072 ;
     RECT  16.403 44.112 16.595 45.624 ;
     RECT  15.689 15.744 16.652 15.768 ;
     RECT  16.549 19.248 16.657 23.784 ;
     RECT  15.329 24.768 16.657 24.888 ;
     RECT  16.261 32.304 16.657 33.624 ;
     RECT  16.657 19.248 16.661 24.888 ;
     RECT  16.403 46.752 16.691 46.872 ;
     RECT  16.661 22.512 16.729 24.888 ;
     RECT  16.513 26.112 16.729 28.824 ;
     RECT  16.652 15.744 16.739 15.864 ;
     RECT  15.833 31.008 16.837 31.32 ;
     RECT  16.657 32.304 16.837 34.392 ;
     RECT  16.595 44.112 16.837 45.576 ;
     RECT  16.837 43.968 16.873 45.576 ;
     RECT  16.189 13.344 16.877 13.368 ;
     RECT  16.661 19.248 16.877 21.192 ;
     RECT  15.689 16.896 16.945 17.064 ;
     RECT  16.877 19.248 16.945 20.856 ;
     RECT  16.945 19.056 16.981 20.856 ;
     RECT  16.729 22.512 16.981 29.256 ;
     RECT  16.945 16.896 17.029 17.688 ;
     RECT  16.873 43.536 17.075 45.576 ;
     RECT  15.833 10.32 17.089 10.344 ;
     RECT  16.837 31.008 17.089 34.392 ;
     RECT  16.013 35.52 17.089 41.928 ;
     RECT  16.373 7.92 17.117 8.472 ;
     RECT  17.089 10.032 17.117 10.344 ;
     RECT  16.441 11.52 17.125 11.544 ;
     RECT  17.089 31.008 17.129 42.168 ;
     RECT  16.981 22.512 17.165 29.496 ;
     RECT  17.117 7.92 17.171 10.344 ;
     RECT  16.691 46.8 17.171 46.872 ;
     RECT  17.171 8.352 17.228 10.344 ;
     RECT  17.125 11.52 17.228 11.784 ;
     RECT  17.129 33.168 17.309 42.168 ;
     RECT  17.165 22.512 17.345 29.256 ;
     RECT  17.309 33.168 17.381 33.384 ;
     RECT  17.309 34.368 17.381 42.168 ;
     RECT  17.075 43.536 17.381 44.136 ;
     RECT  17.381 43.536 17.417 43.656 ;
     RECT  17.345 22.512 17.453 28.92 ;
     RECT  17.075 45.312 17.459 45.576 ;
     RECT  17.228 8.352 17.485 11.784 ;
     RECT  17.129 31.008 17.525 31.992 ;
     RECT  17.453 22.512 17.561 27.96 ;
     RECT  17.381 36.528 17.633 42.168 ;
     RECT  16.739 15.744 17.701 15.768 ;
     RECT  17.525 31.008 17.773 31.704 ;
     RECT  17.485 8.352 17.809 11.832 ;
     RECT  17.809 8.352 17.917 12.312 ;
     RECT  17.561 22.512 17.953 26.856 ;
     RECT  17.917 8.352 18.025 13.08 ;
     RECT  17.917 14.304 18.025 14.328 ;
     RECT  17.171 46.8 18.097 46.824 ;
     RECT  17.459 45.312 18.241 45.336 ;
     RECT  17.381 33.36 18.277 33.384 ;
     RECT  17.381 34.368 18.277 35.544 ;
     RECT  17.953 21.984 18.349 26.856 ;
     RECT  18.241 45.024 18.421 45.336 ;
     RECT  17.701 15.6 18.493 15.768 ;
     RECT  17.029 16.896 18.565 17.208 ;
     RECT  16.981 18.816 18.565 20.856 ;
     RECT  17.097 6.816 18.608 6.84 ;
     RECT  18.025 8.352 18.608 14.328 ;
     RECT  18.493 15.6 18.608 15.816 ;
     RECT  18.565 16.896 18.608 20.856 ;
     RECT  18.349 21.936 18.608 26.856 ;
     RECT  17.561 27.936 18.608 27.96 ;
     RECT  17.773 30.96 18.608 31.704 ;
     RECT  18.277 33.36 18.608 35.544 ;
     RECT  17.633 36.528 18.608 42.024 ;
     RECT  17.417 43.536 18.608 43.56 ;
     RECT  18.421 45.024 18.608 45.576 ;
     RECT  18.608 2.148 18.712 45.576 ;
     RECT  18.097 46.752 18.803 46.824 ;
     RECT  18.712 2.418 18.904 45.576 ;
     RECT  18.904 10.752 18.965 14.28 ;
     RECT  18.904 28.944 18.965 34.776 ;
     RECT  18.904 6.816 19.037 8.712 ;
     RECT  18.904 21.6 19.109 27.96 ;
     RECT  19.109 22.8 19.181 27.96 ;
     RECT  18.904 16.272 19.361 20.424 ;
     RECT  18.803 46.752 19.379 46.776 ;
     RECT  19.361 16.272 19.397 18.264 ;
     RECT  19.361 19.776 19.397 20.424 ;
     RECT  18.904 36.432 19.397 43.704 ;
     RECT  19.037 8.016 19.433 8.712 ;
     RECT  18.965 10.752 19.469 11.976 ;
     RECT  19.397 20.304 19.469 20.424 ;
     RECT  19.181 23.616 19.577 27.96 ;
     RECT  18.965 28.944 19.613 34.68 ;
     RECT  18.904 44.688 19.613 45.576 ;
     RECT  19.613 28.944 19.685 33.288 ;
     RECT  19.469 10.752 19.708 10.776 ;
     RECT  19.397 17.328 19.793 18.264 ;
     RECT  19.685 30.144 19.793 33.288 ;
     RECT  19.469 20.352 19.829 20.424 ;
     RECT  19.685 28.944 19.829 29.112 ;
     RECT  19.613 34.368 19.829 34.68 ;
     RECT  18.965 13.056 19.964 14.28 ;
     RECT  19.037 6.816 19.973 6.84 ;
     RECT  19.793 30.144 19.973 33.192 ;
     RECT  19.964 13.056 20.051 14.808 ;
     RECT  19.829 20.352 20.081 20.376 ;
     RECT  19.613 45.024 20.153 45.576 ;
     RECT  19.397 36.432 20.189 43.272 ;
     RECT  20.051 13.056 20.221 14.232 ;
     RECT  19.829 29.088 20.225 29.112 ;
     RECT  19.433 8.208 20.261 8.712 ;
     RECT  19.469 11.952 20.329 11.976 ;
     RECT  20.221 13.008 20.329 14.232 ;
     RECT  19.109 21.6 20.437 21.72 ;
     RECT  20.437 21.504 20.473 21.72 ;
     RECT  20.189 36.432 20.477 42.552 ;
     RECT  20.153 45.024 20.513 45.432 ;
     RECT  20.329 11.952 20.549 14.232 ;
     RECT  20.477 37.008 20.549 42.552 ;
     RECT  19.397 16.272 20.588 16.296 ;
     RECT  19.793 17.328 20.588 17.64 ;
     RECT  20.549 11.952 20.617 11.976 ;
     RECT  20.588 16.272 20.675 17.64 ;
     RECT  19.577 23.616 20.693 27.432 ;
     RECT  20.513 45.024 20.773 45.384 ;
     RECT  20.473 21.504 20.797 21.864 ;
     RECT  20.693 23.616 20.797 27.336 ;
     RECT  20.549 13.008 20.837 14.232 ;
     RECT  20.797 21.504 20.837 27.336 ;
     RECT  20.837 21.504 20.873 25.752 ;
     RECT  20.873 21.504 20.905 24.168 ;
     RECT  19.829 34.656 20.905 34.68 ;
     RECT  20.617 11.184 20.945 11.976 ;
     RECT  19.973 30.816 21.013 33.192 ;
     RECT  20.837 26.928 21.017 27.336 ;
     RECT  20.905 21.456 21.049 24.168 ;
     RECT  21.049 20.64 21.085 24.168 ;
     RECT  21.017 27.312 21.125 27.336 ;
     RECT  21.013 30.816 21.161 33.384 ;
     RECT  20.905 46.752 21.193 46.776 ;
     RECT  20.675 16.272 21.229 17.352 ;
     RECT  20.873 25.2 21.233 25.752 ;
     RECT  20.549 38.16 21.253 42.552 ;
     RECT  21.233 25.2 21.269 25.224 ;
     RECT  20.905 34.656 21.269 34.872 ;
     RECT  20.945 11.328 21.305 11.976 ;
     RECT  21.085 20.352 21.404 24.168 ;
     RECT  20.725 29.472 21.409 29.496 ;
     RECT  21.404 20.16 21.491 24.168 ;
     RECT  20.837 13.056 21.517 14.232 ;
     RECT  21.229 15.456 21.517 17.352 ;
     RECT  20.773 44.448 21.517 45.384 ;
     RECT  20.549 37.008 21.553 37.032 ;
     RECT  21.253 38.16 21.553 43.368 ;
     RECT  21.491 20.64 21.557 24.168 ;
     RECT  21.193 46.752 21.589 46.872 ;
     RECT  21.553 37.008 21.593 43.368 ;
     RECT  21.409 28.56 21.625 29.496 ;
     RECT  21.517 44.448 21.683 45.624 ;
     RECT  21.517 13.056 21.773 17.352 ;
     RECT  21.773 15.456 21.779 17.352 ;
     RECT  21.557 20.64 21.809 22.728 ;
     RECT  20.261 8.544 21.841 8.712 ;
     RECT  21.161 30.912 21.877 33.384 ;
     RECT  21.841 8.544 21.913 9.24 ;
     RECT  21.683 44.448 21.917 45.576 ;
     RECT  21.305 11.424 21.923 11.976 ;
     RECT  21.593 37.008 21.925 39.288 ;
     RECT  21.925 36.24 22.012 39.288 ;
     RECT  21.923 11.52 22.021 11.976 ;
     RECT  21.773 13.056 22.021 14.28 ;
     RECT  21.593 40.368 22.025 43.368 ;
     RECT  21.779 15.456 22.061 15.48 ;
     RECT  21.625 28.56 22.129 29.784 ;
     RECT  21.589 46.704 22.162 46.872 ;
     RECT  21.557 23.856 22.165 24.168 ;
     RECT  21.877 30.912 22.237 34.104 ;
     RECT  22.021 11.52 22.313 14.28 ;
     RECT  22.313 11.52 22.349 11.976 ;
     RECT  21.917 44.832 22.393 45.576 ;
     RECT  22.129 28.416 22.493 29.784 ;
     RECT  22.162 46.656 22.547 46.872 ;
     RECT  22.493 28.416 22.561 29.544 ;
     RECT  22.561 28.32 22.565 29.544 ;
     RECT  22.237 30.912 22.601 34.392 ;
     RECT  22.565 28.32 22.637 29.496 ;
     RECT  22.393 44.832 22.739 45.384 ;
     RECT  21.913 8.544 22.741 9.384 ;
     RECT  22.012 36.48 22.741 39.288 ;
     RECT  22.741 8.544 22.777 9.528 ;
     RECT  21.809 20.88 22.777 22.344 ;
     RECT  22.637 28.32 22.777 29.064 ;
     RECT  22.777 27.456 22.781 29.064 ;
     RECT  22.777 8.544 22.787 10.392 ;
     RECT  21.877 18.864 22.817 18.888 ;
     RECT  22.025 40.56 22.817 43.368 ;
     RECT  22.787 9.36 22.921 10.392 ;
     RECT  22.313 13.104 22.925 14.28 ;
     RECT  22.817 40.56 22.961 42.744 ;
     RECT  22.777 20.496 23.101 22.344 ;
     RECT  22.165 23.856 23.101 24.792 ;
     RECT  22.601 30.912 23.389 33.864 ;
     RECT  22.547 46.752 23.411 46.872 ;
     RECT  22.349 11.952 23.461 11.976 ;
     RECT  22.739 44.832 23.461 45.336 ;
     RECT  23.101 20.496 23.497 24.792 ;
     RECT  22.781 27.456 23.605 27.48 ;
     RECT  22.781 28.896 23.701 29.064 ;
     RECT  23.461 44.064 23.749 45.336 ;
     RECT  23.701 28.896 23.821 29.256 ;
     RECT  22.921 9.36 23.857 10.632 ;
     RECT  23.389 30.816 23.857 33.864 ;
     RECT  23.605 27.36 23.893 27.48 ;
     RECT  23.821 28.752 23.893 29.256 ;
     RECT  23.749 44.064 23.941 45.48 ;
     RECT  23.857 8.496 24.008 10.632 ;
     RECT  23.461 11.712 24.008 11.976 ;
     RECT  22.925 13.104 24.008 14.184 ;
     RECT  21.779 16.464 24.008 17.352 ;
     RECT  23.497 20.064 24.008 24.792 ;
     RECT  21.841 26.256 24.008 26.28 ;
     RECT  23.893 27.36 24.008 29.256 ;
     RECT  23.857 30.816 24.008 34.824 ;
     RECT  22.741 36.48 24.008 39.336 ;
     RECT  22.961 40.656 24.008 42.744 ;
     RECT  23.941 44.064 24.008 45.528 ;
     RECT  24.008 2.148 24.037 45.528 ;
     RECT  24.037 2.148 24.112 45.576 ;
     RECT  24.112 2.418 24.133 45.576 ;
     RECT  24.133 2.418 24.219 45.624 ;
     RECT  24.219 2.418 24.304 45.672 ;
     RECT  23.411 46.752 24.433 46.776 ;
     RECT  24.304 12.48 24.545 13.128 ;
     RECT  24.304 25.536 24.725 28.008 ;
     RECT  24.433 46.752 24.853 46.92 ;
     RECT  24.304 43.728 24.905 45.672 ;
     RECT  24.304 17.088 24.941 18.024 ;
     RECT  24.905 45.312 25.009 45.672 ;
     RECT  24.853 46.752 25.009 47.352 ;
     RECT  25.009 45.312 25.043 47.352 ;
     RECT  24.304 15.744 25.049 15.768 ;
     RECT  24.304 30.816 25.085 34.968 ;
     RECT  25.085 30.816 25.165 33.528 ;
     RECT  25.043 45.312 25.235 46.92 ;
     RECT  24.304 37.056 25.285 42.744 ;
     RECT  24.905 43.728 25.285 44.088 ;
     RECT  25.165 32.304 25.301 33.528 ;
     RECT  25.285 37.056 25.331 44.088 ;
     RECT  24.725 26.736 25.337 28.008 ;
     RECT  25.331 37.056 25.373 41.544 ;
     RECT  25.235 45.312 25.427 46.872 ;
     RECT  25.331 42.768 25.445 44.088 ;
     RECT  25.427 46.704 25.523 46.872 ;
     RECT  24.304 29.04 25.549 29.592 ;
     RECT  24.725 25.536 25.553 25.752 ;
     RECT  25.553 25.536 25.585 25.704 ;
     RECT  24.545 12.48 25.621 12.936 ;
     RECT  25.165 30.816 25.621 31.272 ;
     RECT  25.373 37.104 25.667 41.544 ;
     RECT  25.301 32.928 25.697 33.528 ;
     RECT  25.667 37.104 25.697 37.128 ;
     RECT  25.523 46.704 25.715 46.776 ;
     RECT  25.085 34.656 25.801 34.968 ;
     RECT  25.585 25.248 25.805 25.704 ;
     RECT  25.337 26.736 25.805 26.76 ;
     RECT  25.715 46.752 25.811 46.776 ;
     RECT  24.304 8.496 25.876 9.72 ;
     RECT  25.805 25.248 25.985 25.272 ;
     RECT  25.621 30.672 25.985 31.272 ;
     RECT  25.876 8.448 26.017 9.72 ;
     RECT  25.621 11.712 26.053 12.936 ;
     RECT  25.427 45.312 26.053 45.576 ;
     RECT  24.304 19.248 26.089 23.88 ;
     RECT  26.089 19.248 26.161 24.504 ;
     RECT  26.017 8.448 26.201 10.296 ;
     RECT  26.053 11.664 26.237 12.936 ;
     RECT  26.237 11.712 26.269 12.936 ;
     RECT  26.161 19.056 26.309 24.504 ;
     RECT  25.697 32.976 26.345 33.528 ;
     RECT  25.445 43.728 26.437 43.944 ;
     RECT  26.053 45.024 26.437 45.576 ;
     RECT  25.985 30.672 26.485 31.032 ;
     RECT  26.201 10.272 26.525 10.296 ;
     RECT  24.941 17.088 26.525 17.88 ;
     RECT  26.201 8.448 26.597 9.096 ;
     RECT  26.629 15.264 26.737 15.288 ;
     RECT  26.437 43.728 26.737 45.576 ;
     RECT  25.337 27.984 26.845 28.008 ;
     RECT  25.549 28.992 26.845 29.592 ;
     RECT  26.269 11.712 26.885 13.032 ;
     RECT  26.525 17.616 26.963 17.64 ;
     RECT  26.309 20.064 26.963 24.504 ;
     RECT  26.737 43.104 26.989 45.576 ;
     RECT  26.885 11.712 27.029 12.936 ;
     RECT  26.963 20.112 27.029 24.504 ;
     RECT  26.965 36.48 27.052 36.504 ;
     RECT  25.667 38.256 27.109 41.544 ;
     RECT  26.989 42.72 27.109 45.576 ;
     RECT  27.097 26.88 27.133 26.904 ;
     RECT  26.737 14.928 27.137 15.288 ;
     RECT  26.845 27.984 27.137 29.592 ;
     RECT  27.029 11.712 27.205 12.84 ;
     RECT  27.061 37.056 27.281 37.08 ;
     RECT  26.485 30.624 27.349 31.032 ;
     RECT  27.133 26.736 27.385 26.904 ;
     RECT  27.277 14.352 27.397 14.376 ;
     RECT  26.309 19.056 27.425 19.08 ;
     RECT  27.205 10.752 27.443 12.84 ;
     RECT  25.801 34.656 27.493 35.496 ;
     RECT  27.385 26.736 27.497 27.96 ;
     RECT  27.349 30.624 27.541 31.992 ;
     RECT  26.345 32.976 27.541 33.384 ;
     RECT  27.541 30.624 27.601 33.384 ;
     RECT  27.493 34.608 27.601 35.496 ;
     RECT  27.029 20.832 27.605 24.504 ;
     RECT  27.497 26.736 27.641 26.904 ;
     RECT  27.601 30.624 27.641 35.496 ;
     RECT  27.641 30.624 27.857 31.272 ;
     RECT  27.857 31.248 27.893 31.272 ;
     RECT  27.397 14.256 28.001 14.376 ;
     RECT  27.605 22.32 28.001 24.504 ;
     RECT  27.497 27.936 28.037 27.96 ;
     RECT  27.109 38.256 28.045 45.576 ;
     RECT  28.001 23.616 28.069 24.504 ;
     RECT  27.443 11.664 28.172 12.84 ;
     RECT  28.172 11.664 28.309 13.272 ;
     RECT  28.045 38.256 28.316 45.432 ;
     RECT  27.641 32.448 28.325 35.496 ;
     RECT  27.313 15.408 28.355 15.432 ;
     RECT  28.309 11.664 28.397 14.232 ;
     RECT  28.316 37.728 28.403 45.432 ;
     RECT  28.325 33.84 28.429 35.496 ;
     RECT  28.001 22.32 28.433 22.344 ;
     RECT  27.137 29.568 28.573 29.592 ;
     RECT  26.773 46.752 28.595 46.776 ;
     RECT  28.573 29.088 28.825 29.592 ;
     RECT  27.641 26.736 29.221 26.76 ;
     RECT  28.403 37.968 29.276 45.432 ;
     RECT  28.325 32.448 29.365 32.472 ;
     RECT  28.429 33.84 29.365 35.736 ;
     RECT  26.597 8.448 29.408 8.472 ;
     RECT  28.397 11.664 29.408 12.552 ;
     RECT  27.605 20.832 29.408 21.096 ;
     RECT  28.069 23.616 29.408 24.696 ;
     RECT  29.221 26.736 29.408 27.432 ;
     RECT  28.825 28.992 29.408 29.592 ;
     RECT  29.365 32.448 29.408 35.736 ;
     RECT  29.276 37.968 29.408 45.48 ;
     RECT  29.408 2.148 29.509 45.48 ;
     RECT  29.509 2.148 29.512 45.576 ;
     RECT  29.512 2.418 29.704 45.576 ;
     RECT  29.704 43.824 29.797 45.576 ;
     RECT  29.221 47.28 29.797 47.4 ;
     RECT  29.704 37.92 29.843 42.792 ;
     RECT  29.843 42.528 30.089 42.792 ;
     RECT  29.704 35.184 30.125 35.448 ;
     RECT  30.125 35.28 30.197 35.448 ;
     RECT  29.704 30.912 30.233 31.128 ;
     RECT  30.089 42.528 30.233 42.6 ;
     RECT  29.704 34.176 30.241 34.2 ;
     RECT  29.797 43.824 30.269 47.4 ;
     RECT  29.704 23.616 30.521 29.88 ;
     RECT  30.521 29.76 30.665 29.88 ;
     RECT  30.665 29.856 30.701 29.88 ;
     RECT  29.704 20.976 30.709 21.048 ;
     RECT  30.197 35.328 30.737 35.448 ;
     RECT  30.709 20.976 30.769 21.096 ;
     RECT  30.521 23.616 30.773 28.776 ;
     RECT  29.704 33.024 30.805 33.048 ;
     RECT  29.843 37.92 30.908 41.496 ;
     RECT  29.704 36.48 31.021 36.504 ;
     RECT  30.737 35.328 31.061 35.352 ;
     RECT  30.769 21.024 31.093 21.096 ;
     RECT  30.233 30.96 31.309 31.128 ;
     RECT  30.908 37.92 31.309 41.592 ;
     RECT  31.093 21.024 31.421 21.672 ;
     RECT  30.773 23.616 31.453 28.488 ;
     RECT  31.309 30.96 31.597 31.224 ;
     RECT  31.309 37.632 31.597 41.592 ;
     RECT  30.233 42.576 31.597 42.6 ;
     RECT  31.021 36.48 31.669 36.552 ;
     RECT  31.597 37.632 31.669 42.6 ;
     RECT  30.805 32.688 31.741 33.048 ;
     RECT  31.597 30.816 31.745 31.224 ;
     RECT  31.669 36.48 31.777 42.6 ;
     RECT  30.269 43.92 31.777 47.4 ;
     RECT  31.745 30.912 31.861 31.224 ;
     RECT  31.741 32.688 31.861 33.528 ;
     RECT  31.777 36.48 31.861 47.4 ;
     RECT  31.453 22.704 31.885 28.488 ;
     RECT  31.861 36.384 31.948 47.4 ;
     RECT  31.861 30.912 31.961 33.528 ;
     RECT  31.961 33.504 31.993 33.528 ;
     RECT  31.948 36.528 32.401 47.4 ;
     RECT  32.401 36.528 32.465 43.272 ;
     RECT  32.401 44.352 32.605 47.4 ;
     RECT  31.885 22.704 32.677 29.256 ;
     RECT  31.421 21.072 32.749 21.144 ;
     RECT  29.704 8.448 32.821 8.472 ;
     RECT  32.749 20.304 32.963 21.144 ;
     RECT  32.677 22.224 32.963 29.256 ;
     RECT  31.993 33.504 32.965 33.624 ;
     RECT  31.417 35.088 32.965 35.112 ;
     RECT  32.465 36.528 33.005 36.888 ;
     RECT  32.965 33.504 33.041 35.112 ;
     RECT  32.821 8.448 33.061 9.432 ;
     RECT  29.704 11.664 33.061 11.688 ;
     RECT  33.061 8.448 33.107 9.96 ;
     RECT  33.061 11.424 33.107 11.688 ;
     RECT  31.961 30.912 33.289 32.28 ;
     RECT  32.963 22.704 33.361 29.256 ;
     RECT  33.289 30.864 33.361 32.28 ;
     RECT  32.465 37.92 33.505 43.272 ;
     RECT  33.041 34.416 33.577 35.112 ;
     RECT  33.505 37.92 33.577 43.368 ;
     RECT  32.605 44.352 33.577 47.496 ;
     RECT  33.107 9.936 33.617 9.96 ;
     RECT  33.107 8.448 33.689 8.472 ;
     RECT  33.361 22.704 33.761 32.28 ;
     RECT  33.577 34.416 34.153 35.352 ;
     RECT  33.005 36.528 34.153 36.552 ;
     RECT  33.577 37.92 34.153 47.496 ;
     RECT  33.761 22.704 34.165 26.904 ;
     RECT  33.761 28.176 34.501 32.28 ;
     RECT  34.501 28.176 34.549 32.76 ;
     RECT  33.107 11.424 34.604 11.448 ;
     RECT  34.604 11.424 34.621 11.976 ;
     RECT  32.963 20.304 34.645 21.096 ;
     RECT  34.165 22.224 34.645 26.904 ;
     RECT  34.549 28.176 34.765 33.096 ;
     RECT  34.645 9.072 34.808 9.096 ;
     RECT  34.621 11.136 34.808 11.976 ;
     RECT  34.645 20.304 34.808 26.904 ;
     RECT  34.765 27.888 34.808 33.096 ;
     RECT  34.153 34.416 34.808 47.496 ;
     RECT  34.808 2.148 35.104 47.496 ;
     RECT  35.104 29.04 35.165 33.624 ;
     RECT  35.104 35.712 35.165 43.752 ;
     RECT  35.104 27.744 35.273 27.912 ;
     RECT  35.165 29.04 35.273 29.064 ;
     RECT  35.165 30.096 35.417 33.096 ;
     RECT  35.104 21.696 35.489 26.664 ;
     RECT  35.489 22.176 35.633 26.664 ;
     RECT  35.633 23.28 35.705 26.664 ;
     RECT  35.165 43.008 36.133 43.752 ;
     RECT  35.104 44.736 36.133 47.496 ;
     RECT  35.269 1.728 36.216 1.752 ;
     RECT  35.165 35.712 36.313 42.024 ;
     RECT  36.133 43.008 36.313 47.496 ;
     RECT  35.104 10.752 36.38 11.688 ;
     RECT  35.333 0.096 36.385 0.12 ;
     RECT  35.417 30.096 36.421 30.888 ;
     RECT  35.417 31.968 36.421 33.096 ;
     RECT  36.38 10.752 36.467 11.928 ;
     RECT  35.705 23.328 36.601 26.664 ;
     RECT  36.313 35.712 36.709 47.496 ;
     RECT  36.709 35.328 36.749 47.496 ;
     RECT  36.421 30.096 36.773 30.984 ;
     RECT  36.421 31.968 36.773 33.144 ;
     RECT  36.773 30.096 36.805 33.144 ;
     RECT  36.601 23.328 36.821 26.76 ;
     RECT  35.273 27.744 36.857 27.768 ;
     RECT  35.633 22.176 36.997 22.2 ;
     RECT  36.805 30.096 37.001 33.528 ;
     RECT  37.001 33.12 37.033 33.528 ;
     RECT  36.997 22.032 37.037 22.2 ;
     RECT  36.749 36.528 37.043 47.496 ;
     RECT  37.043 36.816 37.109 47.496 ;
     RECT  35.104 9.696 37.249 9.72 ;
     RECT  36.467 10.752 37.249 11.688 ;
     RECT  36.216 1.728 37.333 1.8 ;
     RECT  36.821 23.328 37.361 25.704 ;
     RECT  37.249 9.696 37.429 11.688 ;
     RECT  36.385 0.096 37.621 0.168 ;
     RECT  37.109 42.576 37.649 46.728 ;
     RECT  37.645 29.04 37.681 29.064 ;
     RECT  36.821 26.736 37.717 26.76 ;
     RECT  37.681 28.944 37.717 29.064 ;
     RECT  37.001 30.096 37.717 31.416 ;
     RECT  37.429 9.36 37.721 11.688 ;
     RECT  37.033 33.12 37.721 33.672 ;
     RECT  37.109 36.816 37.721 41.496 ;
     RECT  37.649 43.008 37.901 46.728 ;
     RECT  37.717 26.736 37.909 27.528 ;
     RECT  37.717 28.944 37.909 31.416 ;
     RECT  37.909 26.736 37.955 31.416 ;
     RECT  37.955 28.272 37.996 28.968 ;
     RECT  37.721 33.648 38.045 33.672 ;
     RECT  37.955 26.736 38.113 26.76 ;
     RECT  37.721 36.816 38.147 38.76 ;
     RECT  37.037 22.032 38.197 22.056 ;
     RECT  37.361 23.328 38.197 24.744 ;
     RECT  38.197 22.032 38.243 24.744 ;
     RECT  37.955 30.144 38.257 31.416 ;
     RECT  36.749 35.328 38.261 35.352 ;
     RECT  37.996 28.944 38.441 28.968 ;
     RECT  35.104 7.632 38.732 7.656 ;
     RECT  37.825 13.008 38.761 13.032 ;
     RECT  38.732 7.632 38.773 7.848 ;
     RECT  36.493 20.304 38.773 20.328 ;
     RECT  38.545 21.36 38.773 21.72 ;
     RECT  38.761 13.008 38.819 13.128 ;
     RECT  38.773 20.304 38.819 21.72 ;
     RECT  37.901 43.68 38.873 46.728 ;
     RECT  38.873 44.448 38.941 46.728 ;
     RECT  38.243 22.752 38.981 24.744 ;
     RECT  38.819 20.304 39.017 20.664 ;
     RECT  38.981 23.52 39.017 24.744 ;
     RECT  38.257 30.144 39.049 31.944 ;
     RECT  37.721 10.704 39.053 11.688 ;
     RECT  39.053 11.52 39.121 11.688 ;
     RECT  39.049 29.328 39.121 31.944 ;
     RECT  38.819 21.696 39.161 21.72 ;
     RECT  38.147 37.92 39.193 38.76 ;
     RECT  37.721 39.84 39.193 41.496 ;
     RECT  39.121 11.52 39.233 12.024 ;
     RECT  39.017 23.52 39.233 23.88 ;
     RECT  38.941 44.448 39.521 47.496 ;
     RECT  39.521 46.416 39.629 47.496 ;
     RECT  37.721 9.36 39.661 9.384 ;
     RECT  38.773 6.816 39.733 7.848 ;
     RECT  39.121 29.328 39.769 32.664 ;
     RECT  38.113 25.776 39.805 26.76 ;
     RECT  39.265 34.752 39.877 34.776 ;
     RECT  39.836 35.904 39.877 35.928 ;
     RECT  39.193 37.92 39.877 41.496 ;
     RECT  39.629 46.56 39.917 47.496 ;
     RECT  39.733 6.816 39.98 7.992 ;
     RECT  39.769 29.232 39.98 32.664 ;
     RECT  39.98 6.816 40.021 8.328 ;
     RECT  39.661 9.36 40.021 10.344 ;
     RECT  39.805 25.008 40.021 26.76 ;
     RECT  39.301 33.696 40.021 33.72 ;
     RECT  39.877 34.752 40.021 41.496 ;
     RECT  37.333 1.728 40.208 1.752 ;
     RECT  40.021 6.816 40.208 10.344 ;
     RECT  39.233 11.952 40.208 12.024 ;
     RECT  38.819 13.104 40.208 13.128 ;
     RECT  39.017 20.64 40.208 20.664 ;
     RECT  39.233 23.616 40.208 23.88 ;
     RECT  40.021 25.008 40.208 27.336 ;
     RECT  39.98 28.416 40.208 32.664 ;
     RECT  40.021 33.696 40.208 41.496 ;
     RECT  39.445 42.576 40.208 42.6 ;
     RECT  39.521 44.448 40.208 45.372 ;
     RECT  40.208 1.728 40.504 45.372 ;
     RECT  40.504 1.728 40.537 1.896 ;
     RECT  40.504 25.776 40.565 25.8 ;
     RECT  40.504 13.104 40.601 13.128 ;
     RECT  40.504 7.44 40.817 10.344 ;
     RECT  40.504 23.616 40.889 23.88 ;
     RECT  39.917 47.472 40.988 47.496 ;
     RECT  40.817 7.44 40.997 8.856 ;
     RECT  40.504 33.024 40.997 35.16 ;
     RECT  40.997 7.44 41.027 8.568 ;
     RECT  40.817 10.32 41.033 10.344 ;
     RECT  40.504 45.024 41.065 45.372 ;
     RECT  40.997 33.648 41.068 35.16 ;
     RECT  41.027 7.968 41.069 8.568 ;
     RECT  40.504 27.744 41.069 31.416 ;
     RECT  40.988 46.752 41.075 47.496 ;
     RECT  41.068 33.648 41.105 34.2 ;
     RECT  37.621 0.096 41.209 0.12 ;
     RECT  41.105 33.648 41.315 33.912 ;
     RECT  40.504 42.576 41.465 42.792 ;
     RECT  41.069 29.616 41.569 31.416 ;
     RECT  41.315 33.888 41.573 33.912 ;
     RECT  41.209 0.096 41.605 0.216 ;
     RECT  41.069 27.744 41.645 28.536 ;
     RECT  40.504 37.296 41.651 41.496 ;
     RECT  41.651 39.504 41.681 41.496 ;
     RECT  41.605 0.096 41.689 0.6 ;
     RECT  41.681 41.376 41.845 41.496 ;
     RECT  41.465 42.576 41.845 42.744 ;
     RECT  41.069 8.352 41.861 8.568 ;
     RECT  41.569 29.616 41.933 32.232 ;
     RECT  41.933 30 41.969 32.232 ;
     RECT  41.641 11.52 41.996 11.544 ;
     RECT  41.861 8.448 42.001 8.568 ;
     RECT  42.001 8.448 42.073 8.856 ;
     RECT  41.996 10.752 42.083 11.544 ;
     RECT  40.537 1.728 42.156 1.752 ;
     RECT  41.681 39.504 42.221 40.392 ;
     RECT  41.969 30 42.227 31.368 ;
     RECT  42.227 31.104 42.268 31.368 ;
     RECT  40.504 20.64 42.289 20.664 ;
     RECT  41.651 37.296 42.373 38.28 ;
     RECT  42.373 36 42.46 38.28 ;
     RECT  42.469 34.896 42.617 34.92 ;
     RECT  42.289 20.592 42.649 20.664 ;
     RECT  41.645 28.512 42.649 28.536 ;
     RECT  41.065 45.024 42.685 45.576 ;
     RECT  42.46 36.048 42.869 38.28 ;
     RECT  42.649 27.6 42.937 28.536 ;
     RECT  42.227 30 42.937 30.024 ;
     RECT  42.001 32.688 43.009 32.712 ;
     RECT  42.937 27.6 43.021 30.024 ;
     RECT  41.689 0.096 43.085 0.168 ;
     RECT  41.845 41.376 43.109 42.744 ;
     RECT  43.081 6.096 43.117 6.12 ;
     RECT  42.268 31.104 43.157 31.128 ;
     RECT  43.009 32.688 43.157 33.336 ;
     RECT  42.073 8.448 43.193 8.952 ;
     RECT  43.109 41.376 43.193 42.792 ;
     RECT  42.156 1.728 43.229 1.8 ;
     RECT  43.193 8.448 43.229 8.856 ;
     RECT  42.221 39.888 43.333 40.392 ;
     RECT  43.193 41.376 43.333 42.504 ;
     RECT  42.083 11.52 43.405 11.544 ;
     RECT  43.405 11.52 43.441 11.832 ;
     RECT  42.685 44.832 43.445 45.576 ;
     RECT  43.58 34.704 43.621 34.728 ;
     RECT  41.075 47.472 43.621 47.496 ;
     RECT  43.117 6.096 43.625 6.552 ;
     RECT  43.621 47.376 43.661 47.496 ;
     RECT  43.157 33.312 43.667 33.336 ;
     RECT  43.621 34.704 43.667 34.872 ;
     RECT  43.661 47.376 43.705 47.4 ;
     RECT  42.869 37.296 43.729 38.28 ;
     RECT  42.649 20.592 43.765 21 ;
     RECT  40.889 23.616 43.765 23.64 ;
     RECT  43.441 11.424 43.841 11.832 ;
     RECT  43.333 39.888 43.861 42.504 ;
     RECT  43.729 37.296 43.909 38.52 ;
     RECT  43.861 39.648 43.909 42.504 ;
     RECT  43.909 37.296 44.044 42.504 ;
     RECT  43.021 30 44.273 30.024 ;
     RECT  40.504 4.896 44.305 4.92 ;
     RECT  43.765 20.496 44.305 21 ;
     RECT  44.269 3.84 44.341 3.864 ;
     RECT  43.667 34.8 44.413 34.872 ;
     RECT  43.085 0.096 44.46 0.12 ;
     RECT  43.445 44.928 44.531 45.576 ;
     RECT  44.044 37.296 44.597 41.496 ;
     RECT  44.413 7.488 44.732 7.512 ;
     RECT  43.229 8.832 44.732 8.856 ;
     RECT  44.341 3.696 44.737 3.864 ;
     RECT  44.305 4.896 44.737 5.064 ;
     RECT  44.737 3.696 44.773 5.064 ;
     RECT  44.449 14.256 44.773 14.28 ;
     RECT  44.413 34.8 44.773 35.064 ;
     RECT  44.732 7.488 44.845 8.856 ;
     RECT  44.773 34.752 44.845 35.064 ;
     RECT  42.869 36.048 44.845 36.072 ;
     RECT  44.845 7.488 44.881 9.24 ;
     RECT  44.773 13.776 44.881 14.28 ;
     RECT  44.945 26.112 44.953 26.136 ;
     RECT  43.841 11.808 44.965 11.832 ;
     RECT  44.953 25.536 44.965 26.136 ;
     RECT  43.021 27.6 44.965 28.68 ;
     RECT  43.229 1.728 44.989 1.752 ;
     RECT  44.773 3.408 44.989 5.064 ;
     RECT  44.881 13.104 45.013 14.28 ;
     RECT  44.46 0.096 45.061 0.168 ;
     RECT  44.305 20.496 45.061 21.48 ;
     RECT  45.061 0.096 45.145 0.6 ;
     RECT  44.845 34.752 45.169 36.072 ;
     RECT  45.061 31.44 45.241 31.464 ;
     RECT  44.965 10.848 45.277 11.832 ;
     RECT  44.965 25.536 45.277 28.68 ;
     RECT  45.169 34.656 45.301 36.072 ;
     RECT  44.597 37.296 45.301 39 ;
     RECT  44.989 1.728 45.421 5.064 ;
     RECT  45.061 19.344 45.493 21.48 ;
     RECT  43.693 22.464 45.493 22.488 ;
     RECT  45.205 15.84 45.565 15.864 ;
     RECT  44.377 17.088 45.565 17.112 ;
     RECT  44.044 42.48 45.601 42.504 ;
     RECT  45.421 1.632 45.608 5.064 ;
     RECT  43.625 6.096 45.608 6.12 ;
     RECT  44.881 7.392 45.608 9.24 ;
     RECT  45.277 10.416 45.608 11.832 ;
     RECT  45.013 13.104 45.608 14.856 ;
     RECT  45.565 15.84 45.608 17.112 ;
     RECT  45.493 19.344 45.608 22.488 ;
     RECT  43.765 23.616 45.608 23.976 ;
     RECT  45.277 25.536 45.608 29.016 ;
     RECT  45.241 31.392 45.608 31.464 ;
     RECT  45.301 34.656 45.608 39 ;
     RECT  44.597 40.032 45.608 40.056 ;
     RECT  44.597 41.04 45.608 41.496 ;
     RECT  45.601 42.48 45.608 42.552 ;
     RECT  44.089 43.584 45.608 43.608 ;
     RECT  44.531 45.024 45.608 45.576 ;
     RECT  45.608 1.632 45.904 45.576 ;
     RECT  45.904 25.536 46.019 27.624 ;
     RECT  45.904 7.392 46.145 8.472 ;
     RECT  45.904 1.632 46.181 6.12 ;
     RECT  45.904 31.44 46.181 31.752 ;
     RECT  45.904 35.28 46.181 38.952 ;
     RECT  45.904 40.272 46.181 43.656 ;
     RECT  45.145 0.096 46.213 0.552 ;
     RECT  46.213 0.096 46.249 0.6 ;
     RECT  46.181 1.632 46.249 5.256 ;
     RECT  46.181 35.328 46.325 38.952 ;
     RECT  46.249 0.096 46.355 5.256 ;
     RECT  46.181 31.44 46.361 31.464 ;
     RECT  45.904 32.832 46.433 32.856 ;
     RECT  45.904 15.84 46.469 17.4 ;
     RECT  46.325 35.328 46.613 37.368 ;
     RECT  45.904 28.992 46.865 29.016 ;
     RECT  45.904 45.168 46.885 45.576 ;
     RECT  45.904 10.416 46.897 10.44 ;
     RECT  46.145 8.16 47.077 8.472 ;
     RECT  45.904 20.064 47.077 22.488 ;
     RECT  45.904 23.616 47.077 23.784 ;
     RECT  46.355 1.728 47.081 5.256 ;
     RECT  46.355 0.096 47.117 0.6 ;
     RECT  47.077 8.16 47.149 9.144 ;
     RECT  46.181 43.296 47.149 43.656 ;
     RECT  46.325 38.736 47.173 38.952 ;
     RECT  46.181 40.272 47.173 42.216 ;
     RECT  47.149 43.296 47.233 43.944 ;
     RECT  45.904 12.336 47.257 12.36 ;
     RECT  47.233 43.296 47.261 43.656 ;
     RECT  46.469 17.136 47.293 17.4 ;
     RECT  47.149 8.112 47.317 9.144 ;
     RECT  46.897 10.416 47.317 10.872 ;
     RECT  47.173 38.736 47.401 42.216 ;
     RECT  47.261 43.296 47.401 43.512 ;
     RECT  47.293 17.136 47.617 18.072 ;
     RECT  47.317 8.112 47.653 10.872 ;
     RECT  47.401 38.736 47.653 43.512 ;
     RECT  46.469 15.84 47.689 15.864 ;
     RECT  47.653 7.392 47.693 10.872 ;
     RECT  46.613 36 47.693 37.368 ;
     RECT  47.081 1.728 47.729 4.872 ;
     RECT  47.257 12.336 47.797 12.552 ;
     RECT  47.689 15.84 47.797 15.96 ;
     RECT  47.617 16.992 47.797 18.072 ;
     RECT  47.797 15.84 47.833 18.072 ;
     RECT  46.885 45.024 47.833 45.576 ;
     RECT  47.221 33.264 47.837 33.288 ;
     RECT  47.693 36 47.893 36.072 ;
     RECT  46.019 25.728 47.905 27.624 ;
     RECT  47.729 1.728 47.909 4.824 ;
     RECT  47.693 37.344 47.909 37.368 ;
     RECT  47.653 38.352 47.945 43.512 ;
     RECT  47.693 10.608 47.977 10.872 ;
     RECT  47.797 11.952 47.977 12.552 ;
     RECT  47.833 15.744 47.977 18.072 ;
     RECT  47.833 45.024 47.987 46.2 ;
     RECT  47.693 7.392 48.017 9.144 ;
     RECT  47.893 35.328 48.053 36.072 ;
     RECT  48.017 7.392 48.133 7.416 ;
     RECT  47.117 0.576 48.161 0.6 ;
     RECT  48.133 6.816 48.179 7.416 ;
     RECT  47.977 10.608 48.229 12.552 ;
     RECT  48.085 13.536 48.229 13.56 ;
     RECT  47.977 15.744 48.229 19.032 ;
     RECT  47.077 20.064 48.229 23.784 ;
     RECT  47.945 38.352 48.229 40.392 ;
     RECT  47.909 4.416 48.233 4.824 ;
     RECT  48.229 37.776 48.233 40.392 ;
     RECT  47.945 41.472 48.301 43.512 ;
     RECT  48.229 15.744 48.373 23.784 ;
     RECT  47.905 24.864 48.373 27.624 ;
     RECT  48.373 15.408 48.445 27.624 ;
     RECT  48.179 6.816 48.557 6.84 ;
     RECT  48.017 9.024 48.665 9.144 ;
     RECT  48.517 29.568 48.709 29.592 ;
     RECT  48.301 41.472 48.709 43.944 ;
     RECT  47.987 45.024 48.709 45.576 ;
     RECT  48.709 29.568 48.755 29.832 ;
     RECT  48.229 10.608 48.769 13.56 ;
     RECT  48.769 10.608 48.877 13.848 ;
     RECT  48.877 10.416 48.913 13.848 ;
     RECT  48.913 10.416 48.949 13.896 ;
     RECT  48.445 15.216 48.949 27.624 ;
     RECT  48.709 41.472 48.956 45.576 ;
     RECT  48.517 47.376 48.997 47.4 ;
     RECT  48.337 0.096 49.043 0.552 ;
     RECT  48.949 10.416 49.045 27.624 ;
     RECT  48.956 41.472 49.057 46.2 ;
     RECT  48.997 47.184 49.057 47.4 ;
     RECT  48.373 33.696 49.129 33.72 ;
     RECT  49.057 41.472 49.139 47.4 ;
     RECT  49.139 46.752 49.235 47.4 ;
     RECT  48.755 29.808 49.345 29.832 ;
     RECT  49.345 34.944 49.381 34.968 ;
     RECT  48.053 36.048 49.381 36.072 ;
     RECT  49.129 33.648 49.453 33.72 ;
     RECT  49.381 34.8 49.453 36.072 ;
     RECT  47.909 1.728 49.457 3.336 ;
     RECT  49.457 1.728 49.493 1.944 ;
     RECT  48.233 4.512 49.493 4.824 ;
     RECT  49.235 47.28 49.529 47.4 ;
     RECT  49.453 33.648 49.561 36.072 ;
     RECT  48.233 37.776 49.561 39.912 ;
     RECT  49.345 29.808 49.573 30.6 ;
     RECT  49.561 33.648 49.573 36.312 ;
     RECT  49.573 29.808 49.597 31.464 ;
     RECT  49.573 32.832 49.597 36.312 ;
     RECT  49.045 10.32 49.633 27.624 ;
     RECT  49.597 29.808 49.633 36.312 ;
     RECT  49.633 29.808 49.673 36.36 ;
     RECT  49.673 32.016 49.741 36.36 ;
     RECT  49.561 37.536 49.741 39.912 ;
     RECT  49.741 32.016 50.029 39.912 ;
     RECT  49.139 41.472 50.029 45.576 ;
     RECT  48.665 9.024 50.053 9.048 ;
     RECT  50.053 9.024 50.101 9.096 ;
     RECT  49.633 10.32 50.101 27.672 ;
     RECT  49.043 0.096 50.129 0.168 ;
     RECT  50.129 0.096 50.213 0.6 ;
     RECT  50.101 9.024 50.389 27.672 ;
     RECT  49.813 28.704 50.389 28.728 ;
     RECT  49.453 6.864 50.461 6.888 ;
     RECT  50.245 47.232 50.597 47.256 ;
     RECT  50.597 47.232 50.627 47.4 ;
     RECT  50.389 9.024 50.677 28.728 ;
     RECT  50.029 32.016 50.716 45.576 ;
     RECT  50.627 47.28 50.723 47.4 ;
     RECT  50.677 9.024 50.725 28.776 ;
     RECT  49.673 29.808 50.749 30.6 ;
     RECT  50.725 9.024 50.821 28.824 ;
     RECT  50.749 29.808 50.869 30.84 ;
     RECT  50.716 32.016 50.869 45.624 ;
     RECT  49.493 1.728 51.008 1.848 ;
     RECT  49.457 3.312 51.008 3.336 ;
     RECT  49.493 4.512 51.008 4.536 ;
     RECT  50.461 6.288 51.008 6.888 ;
     RECT  50.821 8.448 51.008 28.824 ;
     RECT  50.869 29.808 51.008 45.624 ;
     RECT  50.213 0.096 51.059 0.552 ;
     RECT  51.008 1.728 51.304 45.624 ;
     RECT  51.304 38.64 51.473 45.624 ;
     RECT  51.304 1.728 51.653 1.8 ;
     RECT  50.723 47.376 51.761 47.4 ;
     RECT  51.304 3.312 51.797 32.28 ;
     RECT  51.473 41.472 51.827 45.624 ;
     RECT  51.304 36.336 51.905 37.128 ;
     RECT  51.059 0.096 52.019 0.216 ;
     RECT  51.797 3.312 52.049 30.6 ;
     RECT  51.827 41.472 52.301 45.576 ;
     RECT  52.019 0.096 52.344 0.12 ;
     RECT  51.905 36.336 52.697 37.08 ;
     RECT  52.301 41.472 52.697 45.384 ;
     RECT  52.697 36.336 52.805 36.36 ;
     RECT  52.049 28.992 52.841 30.6 ;
     RECT  51.797 31.632 52.841 32.28 ;
     RECT  52.841 31.632 53.057 32.04 ;
     RECT  52.508 33.504 53.057 33.528 ;
     RECT  52.909 35.376 53.132 35.4 ;
     RECT  51.473 38.64 53.173 40.392 ;
     RECT  52.049 3.312 53.201 6.072 ;
     RECT  51.653 1.728 53.208 1.752 ;
     RECT  53.132 34.464 53.219 35.4 ;
     RECT  53.173 38.112 53.365 40.392 ;
     RECT  53.365 37.584 53.485 40.392 ;
     RECT  53.449 41.376 53.485 41.4 ;
     RECT  53.201 5.76 53.593 6.072 ;
     RECT  52.049 7.2 53.593 27.912 ;
     RECT  52.841 29.088 53.809 30.6 ;
     RECT  53.219 34.944 53.809 35.4 ;
     RECT  53.485 37.584 53.881 41.4 ;
     RECT  52.697 42.432 53.881 45.384 ;
     RECT  53.593 5.76 54.025 27.912 ;
     RECT  53.809 28.896 54.025 30.6 ;
     RECT  53.881 37.584 54.029 45.384 ;
     RECT  52.344 0.048 54.13 0.12 ;
     RECT  53.809 34.944 54.236 35.784 ;
     RECT  54.236 34.944 54.313 36.12 ;
     RECT  53.057 31.728 54.637 31.752 ;
     RECT  53.201 3.312 54.673 4.296 ;
     RECT  54.025 5.76 54.673 30.6 ;
     RECT  54.637 31.68 54.673 31.752 ;
     RECT  54.029 42.432 54.749 45.384 ;
     RECT  53.208 1.728 54.803 1.8 ;
     RECT  54.313 34.944 54.821 36.216 ;
     RECT  54.821 36 54.853 36.216 ;
     RECT  54.029 37.584 54.961 41.448 ;
     RECT  54.961 37.488 55.001 41.448 ;
     RECT  54.749 42.48 55.073 45.384 ;
     RECT  55.073 42.528 55.109 45.384 ;
     RECT  54.181 33.6 55.213 33.624 ;
     RECT  55.141 34.896 55.213 34.92 ;
     RECT  55.109 45.024 55.249 45.384 ;
     RECT  53.845 46.752 55.249 46.776 ;
     RECT  55.109 42.528 55.331 43.896 ;
     RECT  54.673 3.312 55.465 31.752 ;
     RECT  55.249 45.024 55.475 46.776 ;
     RECT  54.853 36 55.609 36.264 ;
     RECT  55.001 37.488 55.609 41.352 ;
     RECT  55.475 45.024 55.667 45.576 ;
     RECT  55.475 46.752 55.763 46.776 ;
     RECT  55.465 3.312 56.005 32.328 ;
     RECT  55.213 33.6 56.005 34.92 ;
     RECT  54.803 1.728 56.408 1.752 ;
     RECT  56.005 3.312 56.408 34.92 ;
     RECT  55.609 36 56.408 41.352 ;
     RECT  55.331 42.528 56.408 43.032 ;
     RECT  55.667 45.024 56.408 45.372 ;
     RECT  54.13 0.048 56.473 0.168 ;
     RECT  56.408 1.728 56.512 45.372 ;
     RECT  56.473 0.048 56.557 0.6 ;
     RECT  56.512 1.728 56.704 45.102 ;
     RECT  56.704 42.528 56.801 43.032 ;
     RECT  56.704 4.752 56.909 34.2 ;
     RECT  56.909 4.752 56.981 34.152 ;
     RECT  56.801 43.008 57.299 43.032 ;
     RECT  56.981 4.752 57.305 33.96 ;
     RECT  56.704 3.312 57.449 3.624 ;
     RECT  56.557 0.048 57.733 0.12 ;
     RECT  56.704 38.16 57.809 40.488 ;
     RECT  57.733 0.048 57.875 0.168 ;
     RECT  56.704 35.232 57.985 35.256 ;
     RECT  57.985 35.232 58.057 35.976 ;
     RECT  57.809 40.32 58.097 40.488 ;
     RECT  58.057 35.232 58.417 36.024 ;
     RECT  57.305 5.04 58.421 33.96 ;
     RECT  58.421 32.736 58.525 33.96 ;
     RECT  58.417 35.232 58.525 36.696 ;
     RECT  58.525 32.736 58.645 36.696 ;
     RECT  57.809 38.16 58.645 39.048 ;
     RECT  58.645 32.736 58.691 39.048 ;
     RECT  57.875 0.096 58.693 0.168 ;
     RECT  56.704 1.728 58.709 1.8 ;
     RECT  58.693 0.096 58.78 0.6 ;
     RECT  58.097 40.32 58.817 40.344 ;
     RECT  58.691 35.232 58.853 39.048 ;
     RECT  57.449 3.312 58.883 3.48 ;
     RECT  58.853 37.584 59.069 39.048 ;
     RECT  58.421 5.04 59.105 31.752 ;
     RECT  59.069 37.776 59.105 39.048 ;
     RECT  59.105 39.024 59.137 39.048 ;
     RECT  58.853 35.232 59.321 36.408 ;
     RECT  59.105 5.136 59.468 31.752 ;
     RECT  58.691 32.736 59.468 33.96 ;
     RECT  58.883 3.456 59.573 3.48 ;
     RECT  59.321 35.952 60.037 36.408 ;
     RECT  59.105 37.776 60.037 37.896 ;
     RECT  59.468 5.136 60.277 33.96 ;
     RECT  60.037 35.952 60.289 37.896 ;
     RECT  58.709 1.728 60.3 1.752 ;
     RECT  60.289 35.76 60.325 37.896 ;
     RECT  60.277 5.136 60.361 34.776 ;
     RECT  60.325 35.76 60.361 38.04 ;
     RECT  60.361 5.136 60.364 38.04 ;
     RECT  60.364 35.376 60.469 38.04 ;
     RECT  59.137 39.024 60.469 39.48 ;
     RECT  60.364 5.136 60.565 34.344 ;
     RECT  60.469 35.376 60.617 39.48 ;
     RECT  60.565 5.04 60.793 34.344 ;
     RECT  60.793 4.656 60.908 34.344 ;
     RECT  60.908 4.56 60.949 34.344 ;
     RECT  58.78 0.096 61.336 0.12 ;
     RECT  60.949 3.696 61.477 34.344 ;
     RECT  61.477 3.696 61.532 34.392 ;
     RECT  60.617 35.376 61.532 38.664 ;
     RECT  61.336 0.096 61.729 0.168 ;
     RECT  60.3 1.728 61.808 1.8 ;
     RECT  61.532 3.696 61.808 38.664 ;
     RECT  60.829 39.696 61.808 39.864 ;
     RECT  61.808 1.728 61.912 45.372 ;
     RECT  61.912 1.728 62.104 45.102 ;
     RECT  61.729 0.096 62.125 0.552 ;
     RECT  62.104 35.76 62.201 36.024 ;
     RECT  62.125 0.096 62.209 0.6 ;
     RECT  62.201 35.76 62.425 35.928 ;
     RECT  62.104 3.696 62.531 34.392 ;
     RECT  62.531 3.696 62.771 33.912 ;
     RECT  63.133 35.328 63.529 35.352 ;
     RECT  63.5 36.336 63.529 36.36 ;
     RECT  63.529 35.328 63.587 36.36 ;
     RECT  62.104 1.728 63.756 1.752 ;
     RECT  63.587 35.328 63.779 35.928 ;
     RECT  62.209 0.096 64.037 0.168 ;
     RECT  62.771 4.656 64.537 33.912 ;
     RECT  63.779 35.328 64.537 35.448 ;
     RECT  64.537 4.656 64.865 35.448 ;
     RECT  64.865 4.656 64.973 33.912 ;
     RECT  64.865 34.944 65.045 35.448 ;
     RECT  65.045 35.28 65.153 35.448 ;
     RECT  65.153 35.28 65.549 35.352 ;
     RECT  63.756 1.728 65.593 1.8 ;
     RECT  64.973 8.4 66.085 33.912 ;
     RECT  64.973 4.656 66.089 7.416 ;
     RECT  66.089 5.76 66.133 7.416 ;
     RECT  66.085 8.4 66.133 34.248 ;
     RECT  66.133 5.76 66.233 34.248 ;
     RECT  64.037 0.096 66.265 0.12 ;
     RECT  66.233 6 66.265 34.248 ;
     RECT  65.549 35.28 66.265 35.304 ;
     RECT  65.593 1.728 66.733 1.752 ;
     RECT  66.265 0.096 67.093 0.216 ;
     RECT  66.733 1.728 67.208 1.8 ;
     RECT  66.089 4.656 67.208 4.68 ;
     RECT  66.265 6 67.208 35.304 ;
     RECT  67.208 1.728 67.312 45.372 ;
     RECT  67.312 1.728 67.504 45.102 ;
     RECT  67.093 0.096 67.565 0.552 ;
     RECT  67.504 5.712 67.645 7.992 ;
     RECT  67.504 8.976 67.673 35.352 ;
     RECT  67.673 8.976 67.889 34.824 ;
     RECT  67.645 5.808 67.925 7.992 ;
     RECT  67.925 5.808 68.177 7.368 ;
     RECT  67.889 9.264 68.393 34.824 ;
     RECT  68.177 7.344 68.435 7.368 ;
     RECT  68.177 5.808 68.465 6.024 ;
     RECT  68.393 34.8 68.645 34.824 ;
     RECT  67.504 1.728 68.965 1.8 ;
     RECT  68.965 1.728 69.049 1.848 ;
     RECT  68.393 9.264 69.829 33.672 ;
     RECT  69.829 9.264 70.013 33.768 ;
     RECT  67.565 0.096 70.085 0.168 ;
     RECT  70.013 9.264 70.337 33.624 ;
     RECT  67.504 4.656 70.357 4.68 ;
     RECT  68.465 6 70.403 6.024 ;
     RECT  70.357 4.512 70.517 4.68 ;
     RECT  70.337 9.312 70.805 33.624 ;
     RECT  70.805 9.36 71.021 33.624 ;
     RECT  70.085 0.096 71.064 0.12 ;
     RECT  71.021 9.552 71.129 33.624 ;
     RECT  71.064 0.096 71.165 0.168 ;
     RECT  71.129 14.112 71.273 33.624 ;
     RECT  71.129 9.552 71.309 13.128 ;
     RECT  71.309 9.792 72.385 13.128 ;
     RECT  71.273 14.112 72.385 33.048 ;
     RECT  71.165 0.096 72.396 0.12 ;
     RECT  72.396 0.096 72.565 0.168 ;
     RECT  69.049 1.728 72.608 1.8 ;
     RECT  70.693 4.368 72.608 4.392 ;
     RECT  69.757 8.208 72.608 8.232 ;
     RECT  72.385 9.792 72.608 33.048 ;
     RECT  71.449 34.176 72.608 34.2 ;
     RECT  72.565 0.096 72.659 0.552 ;
     RECT  72.608 1.728 72.712 45.372 ;
     RECT  72.712 1.728 72.904 45.102 ;
     RECT  72.904 12.288 73.037 23.688 ;
     RECT  73.037 14.112 73.043 23.688 ;
     RECT  73.043 14.208 73.109 23.688 ;
     RECT  73.037 12.288 73.217 13.128 ;
     RECT  72.904 24.672 73.505 31.464 ;
     RECT  72.904 8.208 73.523 11.064 ;
     RECT  73.109 14.352 73.541 23.688 ;
     RECT  72.659 0.096 73.619 0.264 ;
     RECT  73.217 12.48 73.685 13.128 ;
     RECT  72.904 33.024 73.685 33.048 ;
     RECT  73.523 8.208 73.721 10.728 ;
     RECT  73.505 25.008 73.933 31.464 ;
     RECT  73.933 25.008 73.955 31.896 ;
     RECT  73.541 15.216 73.973 23.688 ;
     RECT  74.077 13.872 74.297 14.184 ;
     RECT  73.973 15.312 74.365 23.688 ;
     RECT  73.955 25.104 74.401 31.896 ;
     RECT  72.904 1.728 74.512 1.752 ;
     RECT  74.401 25.104 74.549 32.28 ;
     RECT  74.365 15.312 74.621 23.832 ;
     RECT  74.512 1.728 74.657 1.8 ;
     RECT  73.685 12.48 74.873 12.552 ;
     RECT  73.721 9.024 74.977 10.728 ;
     RECT  74.977 9.024 75.017 11.208 ;
     RECT  74.621 19.392 75.109 23.832 ;
     RECT  74.297 14.16 75.253 14.184 ;
     RECT  74.549 25.776 75.305 32.28 ;
     RECT  75.253 14.16 75.397 14.28 ;
     RECT  74.621 15.312 75.397 18.168 ;
     RECT  75.017 9.024 75.443 9.816 ;
     RECT  75.397 14.16 75.521 18.168 ;
     RECT  75.109 19.392 75.553 23.928 ;
     RECT  75.305 25.776 75.557 31.896 ;
     RECT  75.557 25.776 75.58 31.224 ;
     RECT  75.58 26.928 75.701 31.224 ;
     RECT  75.521 16.032 75.733 18.168 ;
     RECT  75.553 19.392 75.733 24.744 ;
     RECT  75.733 16.032 75.737 24.744 ;
     RECT  74.873 12.528 75.781 12.552 ;
     RECT  75.781 12.528 75.827 12.792 ;
     RECT  75.521 14.16 75.841 14.472 ;
     RECT  75.701 30.768 75.845 31.224 ;
     RECT  74.657 1.728 75.852 1.752 ;
     RECT  75.737 18.672 75.875 24.744 ;
     RECT  75.443 9.024 75.881 9.048 ;
     RECT  75.875 23.136 75.917 24.744 ;
     RECT  75.827 12.768 75.989 12.792 ;
     RECT  75.58 25.776 75.989 25.896 ;
     RECT  75.017 11.184 76.097 11.208 ;
     RECT  75.737 16.032 76.115 17.64 ;
     RECT  73.619 0.096 76.14 0.12 ;
     RECT  75.917 24.192 76.261 24.744 ;
     RECT  75.989 25.776 76.261 25.848 ;
     RECT  76.261 24.192 76.307 25.848 ;
     RECT  76.307 25.104 76.349 25.848 ;
     RECT  76.14 0.096 76.429 0.168 ;
     RECT  75.875 18.672 76.457 22.152 ;
     RECT  76.429 0.144 76.529 0.168 ;
     RECT  76.349 25.104 76.565 25.272 ;
     RECT  75.852 1.728 76.609 1.8 ;
     RECT  75.841 13.92 76.633 14.472 ;
     RECT  76.609 1.776 76.709 1.8 ;
     RECT  75.701 26.928 76.881 29.256 ;
     RECT  76.457 18.672 76.889 21.96 ;
     RECT  75.917 23.136 76.921 23.16 ;
     RECT  76.115 16.032 76.979 17.112 ;
     RECT  76.881 26.928 76.997 27.192 ;
     RECT  76.921 23.04 77.101 23.16 ;
     RECT  77.101 23.04 77.461 23.832 ;
     RECT  77.489 0.576 77.497 0.6 ;
     RECT  76.889 19.248 77.497 21.96 ;
     RECT  77.461 23.04 77.497 23.928 ;
     RECT  76.881 28.272 77.497 29.256 ;
     RECT  77.497 0.096 77.572 0.6 ;
     RECT  77.572 0.096 77.689 0.648 ;
     RECT  75.845 31.2 77.713 31.224 ;
     RECT  76.979 16.032 77.749 17.016 ;
     RECT  77.497 28.272 77.749 30.072 ;
     RECT  77.713 31.152 77.749 31.224 ;
     RECT  72.904 4.368 77.893 4.392 ;
     RECT  77.749 28.272 77.893 31.224 ;
     RECT  77.713 1.728 78.008 1.752 ;
     RECT  77.893 3.312 78.008 3.336 ;
     RECT  77.893 4.368 78.008 4.488 ;
     RECT  76.633 13.92 78.008 14.52 ;
     RECT  77.749 15.888 78.008 17.016 ;
     RECT  77.569 18.048 78.008 18.264 ;
     RECT  77.497 19.248 78.008 23.928 ;
     RECT  76.565 25.104 78.008 25.128 ;
     RECT  76.997 27.168 78.008 27.192 ;
     RECT  77.893 28.272 78.008 31.752 ;
     RECT  78.008 1.728 78.112 45.372 ;
     RECT  77.689 0.096 78.265 0.6 ;
     RECT  78.112 1.728 78.304 45.102 ;
     RECT  78.304 17.712 78.329 18.168 ;
     RECT  78.304 4.224 78.365 4.488 ;
     RECT  78.304 19.584 78.365 19.896 ;
     RECT  78.304 28.272 78.365 28.728 ;
     RECT  78.304 27.168 78.401 27.192 ;
     RECT  78.329 17.712 78.509 17.736 ;
     RECT  78.365 28.272 78.509 28.296 ;
     RECT  78.365 19.584 78.905 19.608 ;
     RECT  78.304 25.056 78.941 25.08 ;
     RECT  78.265 0.096 79.283 0.552 ;
     RECT  78.365 4.224 79.301 4.248 ;
     RECT  78.304 23.376 79.301 23.4 ;
     RECT  78.304 1.728 79.429 1.8 ;
     RECT  78.304 22.224 79.481 22.248 ;
     RECT  79.429 1.152 79.685 1.8 ;
     RECT  79.685 1.152 79.769 2.28 ;
     RECT  79.769 1.152 79.985 1.8 ;
     RECT  79.985 1.728 80.173 1.8 ;
     RECT  79.283 0.096 80.837 0.12 ;
     RECT  80.837 0.096 80.921 0.216 ;
     RECT  80.921 0.096 81.971 0.168 ;
     RECT  80.173 1.728 83.141 1.752 ;
     RECT  83.141 1.728 83.408 1.8 ;
     RECT  83.408 1.728 83.512 45.372 ;
     RECT  81.971 0.096 83.557 0.12 ;
     RECT  83.512 1.728 83.704 45.102 ;
     RECT  83.557 0.096 83.765 0.552 ;
     RECT  83.704 1.728 84.877 1.8 ;
     RECT  84.877 1.728 84.961 1.848 ;
     RECT  83.765 0.096 86.629 0.168 ;
     RECT  86.629 0.096 86.716 0.6 ;
     RECT  84.961 1.728 87.538 1.752 ;
     RECT  87.538 1.728 87.661 1.8 ;
     RECT  86.716 0.096 87.948 0.12 ;
     RECT  87.661 1.728 88.632 1.752 ;
     RECT  87.948 0.096 88.693 0.168 ;
     RECT  88.632 1.728 88.765 1.8 ;
     RECT  88.765 1.728 88.808 1.896 ;
     RECT  88.693 0.096 88.901 0.552 ;
     RECT  88.808 1.728 88.912 45.372 ;
     RECT  88.901 0.096 88.985 0.6 ;
     RECT  88.912 1.728 89.104 45.102 ;
     RECT  88.985 0.096 89.597 0.12 ;
     RECT  89.104 1.728 89.677 1.8 ;
     RECT  89.677 1.776 89.777 1.8 ;
    LAYER M5 ;
     RECT  35.28 0.016 89.736 0.659 ;
     RECT  35.28 0.659 76.68 1.763 ;
     RECT  77.808 0.659 89.736 1.763 ;
     RECT  36.24 1.763 37.32 1.811 ;
     RECT  42.192 1.763 43.176 1.811 ;
     RECT  50.448 1.763 51.624 1.811 ;
     RECT  53.232 1.763 54.792 1.811 ;
     RECT  56.4 1.763 58.632 1.811 ;
     RECT  60.336 1.763 62.112 1.811 ;
     RECT  63.792 1.763 65.544 1.811 ;
     RECT  66.768 1.763 72.912 1.811 ;
     RECT  74.544 1.763 74.568 1.811 ;
     RECT  75.888 1.763 76.68 1.811 ;
     RECT  78 1.763 80.136 1.811 ;
     RECT  83.184 1.763 84.936 1.811 ;
     RECT  87.6 1.763 87.624 1.811 ;
     RECT  88.656 1.763 89.736 1.811 ;
     RECT  45.168 1.763 49.32 1.859 ;
     RECT  68.976 1.811 69 1.859 ;
     RECT  84.912 1.811 84.936 1.859 ;
     RECT  45.6 1.859 49.32 1.955 ;
     RECT  45.6 1.955 49.128 2.003 ;
     RECT  2.4 2.137 2.52 2.151 ;
     RECT  7.8 2.137 7.92 2.151 ;
     RECT  13.2 2.137 13.32 2.151 ;
     RECT  18.6 2.137 18.72 2.151 ;
     RECT  24 2.137 24.12 2.151 ;
     RECT  29.4 2.137 29.52 2.151 ;
     RECT  45.6 2.003 48.264 2.195 ;
     RECT  79.728 1.811 79.752 2.291 ;
     RECT  47.568 2.195 48.264 2.339 ;
     RECT  48.24 2.339 48.264 2.387 ;
     RECT  78 1.811 78.312 3.301 ;
     RECT  56.4 1.811 56.712 3.349 ;
     RECT  45.6 2.195 45.912 3.397 ;
     RECT  56.4 3.349 56.808 3.445 ;
     RECT  55.44 3.445 56.808 3.491 ;
     RECT  61.8 1.811 62.112 3.685 ;
     RECT  51 1.811 51.312 3.925 ;
     RECT  77.904 3.301 78.312 4.499 ;
     RECT  55.44 3.491 56.712 4.643 ;
     RECT  67.2 1.811 67.512 4.645 ;
     RECT  60.96 3.685 62.76 4.691 ;
     RECT  40.2 1.763 40.512 4.885 ;
     RECT  60.96 4.691 62.328 5.029 ;
     RECT  51 3.925 51.912 5.603 ;
     RECT  67.2 4.645 67.608 5.747 ;
     RECT  60.576 5.029 62.328 5.843 ;
     RECT  58.848 3.301 58.872 7.045 ;
     RECT  67.2 5.747 67.512 7.333 ;
     RECT  48.144 6.805 48.168 7.381 ;
     RECT  53.52 7.189 53.544 7.381 ;
     RECT  55.584 4.643 56.712 7.381 ;
     RECT  47.904 7.381 48.168 7.427 ;
     RECT  40.2 4.885 41.016 7.475 ;
     RECT  34.8 2.137 35.112 7.621 ;
     RECT  38.784 6.805 38.808 7.859 ;
     RECT  53.28 7.381 53.544 7.861 ;
     RECT  67.2 7.333 68.424 7.957 ;
     RECT  47.904 7.427 47.928 8.003 ;
     RECT  58.848 7.045 59.256 8.051 ;
     RECT  40.2 7.475 40.512 8.053 ;
     RECT  40.032 8.053 40.512 8.339 ;
     RECT  17.136 6.805 17.16 8.341 ;
     RECT  18.6 2.151 18.912 8.341 ;
     RECT  13.2 2.151 13.512 8.437 ;
     RECT  51 5.603 51.312 8.437 ;
     RECT  24 2.151 24.312 8.485 ;
     RECT  55.584 7.381 56.808 8.533 ;
     RECT  53.04 7.861 53.544 8.725 ;
     RECT  66.144 7.957 68.424 8.773 ;
     RECT  52.992 8.725 53.544 8.965 ;
     RECT  50.832 8.437 51.312 9.013 ;
     RECT  34.8 7.621 35.784 9.061 ;
     RECT  50.832 9.013 51.816 9.061 ;
     RECT  55.584 8.533 57.192 9.061 ;
     RECT  61.488 5.843 62.328 9.061 ;
     RECT  63.36 8.005 63.384 9.061 ;
     RECT  65.76 8.773 68.424 9.107 ;
     RECT  52.992 8.965 53.64 9.109 ;
     RECT  58.848 8.051 58.968 9.109 ;
     RECT  17.136 8.341 18.912 9.155 ;
     RECT  24 8.485 25.032 9.203 ;
     RECT  58.656 9.109 58.968 9.349 ;
     RECT  59.952 8.293 59.976 9.349 ;
     RECT  61.488 9.061 63.384 9.349 ;
     RECT  58.656 9.349 63.384 9.397 ;
     RECT  55.344 9.061 57.528 9.493 ;
     RECT  58.656 9.397 63.576 9.493 ;
     RECT  22.752 8.533 22.776 9.539 ;
     RECT  55.344 9.493 63.576 9.589 ;
     RECT  64.656 9.061 64.68 9.589 ;
     RECT  55.344 9.589 64.68 9.685 ;
     RECT  24 9.203 24.744 9.731 ;
     RECT  54.96 9.685 64.68 9.731 ;
     RECT  37.44 9.349 37.464 9.779 ;
     RECT  52.992 9.109 53.736 9.829 ;
     RECT  54.96 9.731 64.248 9.829 ;
     RECT  13.2 8.437 13.608 9.925 ;
     RECT  65.76 9.107 65.976 10.021 ;
     RECT  50.064 9.061 51.816 10.213 ;
     RECT  52.992 9.829 64.248 10.213 ;
     RECT  48.336 9.013 48.36 10.309 ;
     RECT  17.184 9.155 17.208 10.355 ;
     RECT  65.664 10.021 65.976 10.405 ;
     RECT  67.104 9.107 68.424 10.405 ;
     RECT  47.328 9.877 47.352 10.451 ;
     RECT  65.664 10.405 68.424 10.453 ;
     RECT  18.6 9.155 18.912 10.741 ;
     RECT  34.656 9.061 35.784 10.741 ;
     RECT  34.656 10.741 36.456 10.883 ;
     RECT  72.6 1.811 72.912 10.933 ;
     RECT  70.368 4.501 70.392 11.027 ;
     RECT  72.48 10.933 72.912 11.029 ;
     RECT  72.48 11.029 73.512 11.173 ;
     RECT  75.408 9.781 75.432 11.173 ;
     RECT  12.912 9.925 13.608 11.219 ;
     RECT  48.336 10.309 49.08 11.413 ;
     RECT  50.064 10.213 64.248 11.413 ;
     RECT  48.336 11.413 64.248 11.459 ;
     RECT  42.048 10.741 42.072 11.555 ;
     RECT  27.408 10.741 27.432 11.653 ;
     RECT  33.072 9.397 33.096 11.699 ;
     RECT  13.056 11.219 13.608 11.795 ;
     RECT  36.432 10.883 36.456 11.939 ;
     RECT  18.6 10.741 19.656 11.987 ;
     RECT  72.432 11.173 73.512 12.035 ;
     RECT  48.768 11.459 64.248 12.277 ;
     RECT  65.376 10.453 68.424 12.277 ;
     RECT  14.832 10.309 14.856 12.467 ;
     RECT  21.888 11.413 21.912 13.139 ;
     RECT  38.784 12.997 38.808 13.139 ;
     RECT  13.2 11.795 13.608 13.429 ;
     RECT  48.768 12.277 68.424 13.667 ;
     RECT  44.784 3.397 45.912 13.811 ;
     RECT  52.992 13.667 68.424 14.053 ;
     RECT  75.408 11.173 75.816 14.149 ;
     RECT  27.408 11.653 28.248 14.197 ;
     RECT  13.2 13.429 13.8 14.243 ;
     RECT  18.6 11.987 19.128 14.291 ;
     RECT  27.408 14.197 28.344 14.291 ;
     RECT  75.264 14.149 75.816 14.291 ;
     RECT  52.992 14.053 68.856 14.725 ;
     RECT  13.2 14.243 13.608 14.963 ;
     RECT  75.408 14.291 75.432 15.301 ;
     RECT  72.48 12.035 73.512 15.349 ;
     RECT  74.832 15.301 75.432 15.349 ;
     RECT  52.896 14.725 69.288 15.397 ;
     RECT  28.32 14.291 28.344 15.443 ;
     RECT  10.128 13.045 10.152 15.491 ;
     RECT  48.768 13.667 51.768 15.685 ;
     RECT  48.768 15.685 51.816 15.733 ;
     RECT  52.896 15.397 69.336 15.733 ;
     RECT  72.48 15.349 75.432 15.733 ;
     RECT  17.28 10.741 17.304 15.829 ;
     RECT  78 4.499 78.312 15.877 ;
     RECT  48.768 15.733 69.336 16.021 ;
     RECT  20.016 14.773 20.04 16.307 ;
     RECT  21.744 15.541 21.768 16.643 ;
     RECT  48.288 16.021 69.336 16.693 ;
     RECT  13.2 14.963 13.512 16.885 ;
     RECT  16.704 15.829 17.304 16.931 ;
     RECT  77.76 15.877 78.312 16.981 ;
     RECT  16.992 16.931 17.304 17.029 ;
     RECT  18.6 14.291 18.912 17.029 ;
     RECT  48.288 16.693 69.384 17.029 ;
     RECT  70.656 15.973 70.68 17.029 ;
     RECT  76.944 16.981 78.312 17.123 ;
     RECT  16.992 17.029 18.912 17.219 ;
     RECT  71.904 15.733 75.432 17.267 ;
     RECT  24 9.731 24.312 17.317 ;
     RECT  75.408 17.267 75.432 17.605 ;
     RECT  20.64 17.077 20.664 17.651 ;
     RECT  16.992 17.219 17.016 17.699 ;
     RECT  48.288 17.029 70.68 17.843 ;
     RECT  14.832 17.077 14.856 18.083 ;
     RECT  48.288 17.843 69.96 18.371 ;
     RECT  75.408 17.605 76.104 18.707 ;
     RECT  48.432 18.371 69.96 19.189 ;
     RECT  48.432 19.189 70.248 19.331 ;
     RECT  71.904 17.267 74.376 19.427 ;
     RECT  71.904 19.427 72.912 19.571 ;
     RECT  7.8 2.151 8.112 19.621 ;
     RECT  9.168 19.285 9.192 19.621 ;
     RECT  71.952 19.571 72.912 19.859 ;
     RECT  48.432 19.331 68.808 19.907 ;
     RECT  69.84 19.331 70.248 20.053 ;
     RECT  7.8 19.621 9.192 20.293 ;
     RECT  74.112 19.427 74.376 20.293 ;
     RECT  75.408 18.707 75.432 20.293 ;
     RECT  77.76 17.123 78.312 20.341 ;
     RECT  48.432 19.907 68.568 20.483 ;
     RECT  23.904 17.317 24.312 20.485 ;
     RECT  44.928 13.811 45.912 20.627 ;
     RECT  69.84 20.053 70.296 20.629 ;
     RECT  74.112 20.293 75.432 20.629 ;
     RECT  69.84 20.629 70.344 20.677 ;
     RECT  74.112 20.629 75.528 20.771 ;
     RECT  74.544 20.771 75.528 20.869 ;
     RECT  26.928 17.605 26.952 21.061 ;
     RECT  46.992 20.917 47.016 21.107 ;
     RECT  48.528 20.483 68.568 21.109 ;
     RECT  6.144 20.053 6.168 21.155 ;
     RECT  45.072 20.627 45.912 21.155 ;
     RECT  23.328 20.485 24.312 21.157 ;
     RECT  74.544 20.869 76.2 21.203 ;
     RECT  21.456 20.149 21.48 21.349 ;
     RECT  72.432 19.859 72.912 21.349 ;
     RECT  23.328 21.157 24.504 21.491 ;
     RECT  72.384 21.349 72.912 21.587 ;
     RECT  38.784 20.629 38.808 21.731 ;
     RECT  77.712 20.341 78.312 21.731 ;
     RECT  48.528 21.109 68.664 21.829 ;
     RECT  69.84 20.677 70.44 21.829 ;
     RECT  74.544 21.203 75.528 22.069 ;
     RECT  48.528 21.829 70.44 22.165 ;
     RECT  72.432 21.587 72.912 22.165 ;
     RECT  74.256 22.069 75.528 22.165 ;
     RECT  7.8 20.293 10.008 22.211 ;
     RECT  34.656 10.883 35.112 22.213 ;
     RECT  32.928 20.293 32.952 22.259 ;
     RECT  21.456 21.349 21.624 22.403 ;
     RECT  48.528 22.165 70.632 22.451 ;
     RECT  30.72 20.965 30.744 22.741 ;
     RECT  72.432 22.165 75.528 22.741 ;
     RECT  16.56 18.037 16.584 22.835 ;
     RECT  48.528 22.451 68.76 22.883 ;
     RECT  23.328 21.491 24.312 23.027 ;
     RECT  34.176 22.213 35.112 23.269 ;
     RECT  33.504 23.269 35.112 23.317 ;
     RECT  26.064 21.061 26.952 23.411 ;
     RECT  52.512 22.883 68.76 23.459 ;
     RECT  72.432 22.741 75.864 23.459 ;
     RECT  38.208 22.021 38.232 23.555 ;
     RECT  12.672 16.885 13.512 23.749 ;
     RECT  21.456 22.403 21.48 23.795 ;
     RECT  18.6 17.219 18.912 24.133 ;
     RECT  74.352 23.459 75.864 24.181 ;
     RECT  69.84 22.451 70.632 24.277 ;
     RECT  69.84 24.277 71.4 24.467 ;
     RECT  52.56 23.459 68.76 24.517 ;
     RECT  69.84 24.467 70.632 24.517 ;
     RECT  30.72 22.741 31.656 24.709 ;
     RECT  33.024 23.317 35.112 24.709 ;
     RECT  72.432 23.459 72.912 24.709 ;
     RECT  30.72 24.709 31.752 24.997 ;
     RECT  72.432 24.709 73.176 24.997 ;
     RECT  74.352 24.181 76.296 24.997 ;
     RECT  72.432 24.997 76.296 25.045 ;
     RECT  52.56 24.517 70.632 25.069 ;
     RECT  33.024 24.709 35.208 25.091 ;
     RECT  7.8 22.211 8.112 25.525 ;
     RECT  45.6 21.155 45.912 25.525 ;
     RECT  45.6 25.525 46.008 25.763 ;
     RECT  72.096 25.045 76.296 25.765 ;
     RECT  34.56 25.091 35.208 25.861 ;
     RECT  45.6 25.763 45.912 26.101 ;
     RECT  52.56 25.069 53.112 26.149 ;
     RECT  54.096 25.069 70.632 26.149 ;
     RECT  18.432 24.133 18.912 26.197 ;
     RECT  48.528 22.883 51.312 26.197 ;
     RECT  52.56 26.149 70.632 26.197 ;
     RECT  11.808 23.749 13.512 26.243 ;
     RECT  48.528 26.197 70.632 26.435 ;
     RECT  49.536 26.435 70.632 26.483 ;
     RECT  19.92 24.853 19.944 26.531 ;
     RECT  49.536 26.483 53.112 26.579 ;
     RECT  71.808 25.765 76.296 26.627 ;
     RECT  12.672 26.243 13.512 26.675 ;
     RECT  49.536 26.579 52.872 26.675 ;
     RECT  17.664 26.197 18.912 26.819 ;
     RECT  44.976 26.101 45.912 26.819 ;
     RECT  29.4 2.151 29.712 26.869 ;
     RECT  30.72 24.997 31.848 26.869 ;
     RECT  48.528 26.435 48.552 26.915 ;
     RECT  49.536 26.675 51.432 26.915 ;
     RECT  29.4 26.869 31.848 27.059 ;
     RECT  20.928 26.917 20.952 27.299 ;
     RECT  40.2 8.339 40.512 27.301 ;
     RECT  73.968 26.627 76.296 27.301 ;
     RECT  77.76 21.731 78.312 27.301 ;
     RECT  23.616 23.027 24.312 27.395 ;
     RECT  29.4 27.059 30.408 27.397 ;
     RECT  54.096 26.483 70.632 27.445 ;
     RECT  71.808 26.627 72.912 27.445 ;
     RECT  73.968 27.301 78.312 27.491 ;
     RECT  54.096 27.445 72.912 27.685 ;
     RECT  73.968 27.491 75.528 27.685 ;
     RECT  50.4 26.915 51.432 27.829 ;
     RECT  52.464 26.675 52.872 27.829 ;
     RECT  50.4 27.829 52.872 27.923 ;
     RECT  54.096 27.685 75.528 27.971 ;
     RECT  40.032 27.301 40.512 28.451 ;
     RECT  33.024 25.091 33.528 28.453 ;
     RECT  34.56 25.861 35.88 28.453 ;
     RECT  41.568 27.877 41.592 28.547 ;
     RECT  72.48 27.971 75.528 28.787 ;
     RECT  54.096 27.971 71.496 28.835 ;
     RECT  23.904 27.395 24.312 28.885 ;
     RECT  7.68 25.525 8.112 28.979 ;
     RECT  76.8 27.491 78.312 28.979 ;
     RECT  7.8 28.979 8.112 28.981 ;
     RECT  9.168 22.211 10.008 28.981 ;
     RECT  54.096 28.835 69.624 29.075 ;
     RECT  42.96 28.501 42.984 29.123 ;
     RECT  50.736 27.923 52.872 29.123 ;
     RECT  54.72 29.075 69.624 29.123 ;
     RECT  70.848 28.835 71.496 29.123 ;
     RECT  72.48 28.787 74.712 29.123 ;
     RECT  23.712 28.885 24.312 29.221 ;
     RECT  26.064 23.411 26.088 29.221 ;
     RECT  23.712 29.221 26.088 29.267 ;
     RECT  76.848 28.979 78.312 29.267 ;
     RECT  72.48 29.123 72.912 29.315 ;
     RECT  12.768 26.675 13.512 29.507 ;
     RECT  16.992 29.365 17.016 29.507 ;
     RECT  54.72 29.123 69.144 29.699 ;
     RECT  73.968 29.123 74.712 29.795 ;
     RECT  37.92 27.493 37.944 29.843 ;
     RECT  54.72 29.699 59.304 30.035 ;
     RECT  33.024 28.453 35.88 30.083 ;
     RECT  40.2 28.451 40.512 30.181 ;
     RECT  50.736 29.123 52.584 30.227 ;
     RECT  74.208 29.795 74.712 30.227 ;
     RECT  55.2 30.035 59.304 30.419 ;
     RECT  40.2 30.181 41.304 30.421 ;
     RECT  71.28 29.123 71.496 30.611 ;
     RECT  55.2 30.419 55.224 30.707 ;
     RECT  40.2 30.421 41.496 30.757 ;
     RECT  74.448 30.227 74.712 30.851 ;
     RECT  77.76 29.267 78.312 30.851 ;
     RECT  71.28 30.611 71.304 30.899 ;
     RECT  50.88 30.227 52.584 30.947 ;
     RECT  13.2 29.507 13.512 30.949 ;
     RECT  31.536 27.059 31.848 30.949 ;
     RECT  39.168 30.853 39.192 30.949 ;
     RECT  40.2 30.757 42.216 30.949 ;
     RECT  60.48 29.699 69.144 30.949 ;
     RECT  39.168 30.949 42.216 30.995 ;
     RECT  77.856 30.851 78.312 31.187 ;
     RECT  34.56 30.083 35.88 31.285 ;
     RECT  37.008 30.181 37.032 31.285 ;
     RECT  40.032 30.995 42.216 31.379 ;
     RECT  34.56 31.285 37.032 31.381 ;
     RECT  48.72 29.557 48.744 31.429 ;
     RECT  50.88 30.947 51.312 31.523 ;
     RECT  56.4 30.419 59.304 31.621 ;
     RECT  60.48 30.949 69.528 31.621 ;
     RECT  56.4 31.621 69.528 31.667 ;
     RECT  59.52 31.667 69.528 31.763 ;
     RECT  13.2 30.949 14.04 31.859 ;
     RECT  7.8 28.981 10.008 31.861 ;
     RECT  59.52 31.763 69.288 31.955 ;
     RECT  74.448 30.851 74.472 31.955 ;
     RECT  27.552 31.909 27.576 32.099 ;
     RECT  59.52 31.955 66.12 32.195 ;
     RECT  24 29.267 26.088 32.243 ;
     RECT  13.2 31.859 13.896 32.339 ;
     RECT  11.232 32.437 11.256 32.485 ;
     RECT  67.2 31.955 69.288 32.579 ;
     RECT  68.736 32.579 69.288 32.627 ;
     RECT  56.4 31.667 58.344 32.723 ;
     RECT  60.48 32.195 66.12 32.723 ;
     RECT  34.512 31.381 37.032 32.771 ;
     RECT  63.744 32.723 66.12 32.867 ;
     RECT  2.4 2.151 2.712 32.965 ;
     RECT  31.536 30.949 31.896 33.059 ;
     RECT  58.32 32.723 58.344 33.059 ;
     RECT  5.616 33.061 5.64 33.203 ;
     RECT  11.232 32.485 11.592 33.251 ;
     RECT  44.064 27.589 44.088 33.301 ;
     RECT  18.432 26.819 18.912 33.493 ;
     RECT  34.56 32.771 37.032 33.539 ;
     RECT  52.56 30.947 52.584 33.539 ;
     RECT  65.808 32.867 66.12 33.587 ;
     RECT  18.432 33.493 19.512 33.635 ;
     RECT  7.536 31.861 10.008 33.683 ;
     RECT  11.232 33.251 11.256 33.683 ;
     RECT  69.264 32.627 69.288 33.683 ;
     RECT  40.032 31.379 41.496 33.875 ;
     RECT  40.08 33.875 41.496 33.923 ;
     RECT  65.952 33.587 66.12 33.923 ;
     RECT  66.096 33.923 66.12 34.259 ;
     RECT  60.48 32.723 62.52 34.307 ;
     RECT  2.4 32.965 3.432 34.355 ;
     RECT  61.584 34.307 62.52 34.403 ;
     RECT  61.584 34.403 62.376 34.595 ;
     RECT  26.064 32.243 26.088 34.645 ;
     RECT  61.632 34.595 62.376 34.691 ;
     RECT  7.536 33.683 8.112 34.741 ;
     RECT  29.232 27.397 30.408 34.741 ;
     RECT  60.48 34.307 60.6 34.741 ;
     RECT  43.632 33.301 44.088 34.835 ;
     RECT  43.632 34.835 43.656 34.883 ;
     RECT  11.952 34.789 11.976 35.219 ;
     RECT  51 31.523 51.312 35.269 ;
     RECT  40.08 33.923 41.016 35.317 ;
     RECT  48.72 31.429 49.608 35.317 ;
     RECT  63.744 32.867 64.68 35.317 ;
     RECT  47.904 35.317 49.608 35.363 ;
     RECT  63.552 35.317 64.68 35.363 ;
     RECT  67.2 32.579 67.656 35.363 ;
     RECT  26.064 34.645 27 35.461 ;
     RECT  45.6 26.819 45.912 35.461 ;
     RECT  29.088 34.741 30.408 35.747 ;
     RECT  61.68 34.691 62.376 35.939 ;
     RECT  63.552 35.363 63.768 35.939 ;
     RECT  50.832 35.269 51.312 35.941 ;
     RECT  60.288 34.741 60.6 36.035 ;
     RECT  47.904 35.363 48.744 36.037 ;
     RECT  47.712 36.037 48.744 36.083 ;
     RECT  5.28 33.877 5.304 36.085 ;
     RECT  54.192 33.589 54.216 36.085 ;
     RECT  4.896 36.085 5.304 36.131 ;
     RECT  50.64 35.941 51.312 36.181 ;
     RECT  47.712 36.083 47.928 36.325 ;
     RECT  63.552 35.939 63.576 36.371 ;
     RECT  31.536 33.059 31.848 36.373 ;
     RECT  26.064 35.461 27.096 36.515 ;
     RECT  18.432 33.635 18.912 36.517 ;
     RECT  31.536 36.373 31.896 36.517 ;
     RECT  37.008 33.539 37.032 36.851 ;
     RECT  46.992 36.325 47.928 36.947 ;
     RECT  61.68 35.939 62.112 36.947 ;
     RECT  24 32.243 24.312 36.997 ;
     RECT  58.656 34.597 58.68 36.997 ;
     RECT  15.984 35.797 16.008 37.043 ;
     RECT  50.544 36.181 51.312 37.045 ;
     RECT  4.896 36.131 4.92 37.091 ;
     RECT  27.072 36.515 27.096 37.091 ;
     RECT  39.888 35.317 41.016 37.091 ;
     RECT  60.288 36.035 60.312 37.091 ;
     RECT  21.936 36.229 21.96 37.283 ;
     RECT  7.056 34.741 8.112 37.331 ;
     RECT  45.312 35.461 45.912 37.331 ;
     RECT  50.256 37.045 51.312 37.333 ;
     RECT  7.2 37.331 8.112 37.525 ;
     RECT  9.168 33.683 10.008 37.525 ;
     RECT  11.088 36.229 11.112 37.571 ;
     RECT  40.08 37.091 41.016 37.571 ;
     RECT  26.064 36.515 26.088 37.573 ;
     RECT  54.192 36.085 54.312 37.573 ;
     RECT  23.136 36.997 24.312 37.667 ;
     RECT  50.208 37.333 51.312 37.667 ;
     RECT  53.184 34.453 53.208 37.669 ;
     RECT  54.192 37.573 55.032 37.669 ;
     RECT  29.232 35.747 30.408 37.717 ;
     RECT  42.384 35.989 42.408 37.811 ;
     RECT  50.256 37.667 51.312 37.811 ;
     RECT  58.656 36.997 58.776 37.861 ;
     RECT  53.184 37.669 55.032 38.147 ;
     RECT  34.56 33.539 35.88 38.149 ;
     RECT  45.6 37.331 45.912 38.149 ;
     RECT  56.4 32.723 57.288 38.149 ;
     RECT  58.656 37.861 59.256 38.149 ;
     RECT  53.376 38.147 55.032 38.195 ;
     RECT  47.712 36.947 47.928 38.387 ;
     RECT  7.2 37.525 10.008 38.725 ;
     RECT  25.632 37.573 26.088 38.725 ;
     RECT  56.4 38.149 59.256 38.725 ;
     RECT  56.304 38.725 59.256 38.819 ;
     RECT  28.368 37.717 30.408 38.917 ;
     RECT  31.536 36.517 31.944 38.917 ;
     RECT  40.08 37.571 40.512 38.965 ;
     RECT  25.632 38.725 26.712 39.061 ;
     RECT  17.568 36.517 18.912 39.301 ;
     RECT  25.632 39.061 26.76 39.301 ;
     RECT  38.112 36.805 38.136 39.301 ;
     RECT  28.368 38.917 31.944 39.395 ;
     RECT  33.024 30.083 33.528 39.395 ;
     RECT  53.376 38.195 54.216 39.395 ;
     RECT  59.232 38.819 59.256 39.395 ;
     RECT  7.2 38.725 10.872 39.443 ;
     RECT  53.376 39.395 54.12 39.443 ;
     RECT  9.168 39.443 10.872 39.493 ;
     RECT  45.6 38.149 46.296 39.493 ;
     RECT  47.712 38.387 47.736 39.493 ;
     RECT  41.616 38.677 41.64 39.539 ;
     RECT  34.56 38.149 36.024 39.541 ;
     RECT  25.632 39.301 27.336 39.685 ;
     RECT  25.344 39.685 27.336 39.731 ;
     RECT  13.2 32.339 13.512 39.829 ;
     RECT  55.296 38.533 55.32 39.829 ;
     RECT  56.304 38.819 58.152 39.829 ;
     RECT  30.96 39.395 31.944 39.877 ;
     RECT  33.024 39.395 33.048 39.877 ;
     RECT  28.368 39.395 29.712 39.923 ;
     RECT  37.488 39.301 38.136 39.923 ;
     RECT  34.224 39.541 36.024 39.971 ;
     RECT  14.976 35.317 15 40.117 ;
     RECT  7.2 39.443 8.112 40.309 ;
     RECT  13.2 39.829 13.608 40.355 ;
     RECT  55.296 39.829 58.152 40.355 ;
     RECT  55.296 40.355 57.288 40.403 ;
     RECT  6.912 40.309 8.112 40.405 ;
     RECT  9.168 39.493 11.4 40.405 ;
     RECT  24 37.667 24.312 40.405 ;
     RECT  25.344 39.731 25.368 40.405 ;
     RECT  39.984 38.965 40.512 40.405 ;
     RECT  28.8 39.923 29.712 40.499 ;
     RECT  34.8 39.971 36.024 40.499 ;
     RECT  53.856 39.443 53.88 40.499 ;
     RECT  17.568 39.301 19.368 40.547 ;
     RECT  13.2 40.355 13.512 40.693 ;
     RECT  43.872 39.637 43.896 40.837 ;
     RECT  29.232 40.499 29.712 40.981 ;
     RECT  0.192 23.845 0.216 41.075 ;
     RECT  17.568 40.547 18.912 41.075 ;
     RECT  29.232 40.981 29.832 41.075 ;
     RECT  39.984 40.405 41.112 41.123 ;
     RECT  6.912 40.405 11.4 41.171 ;
     RECT  17.568 41.075 17.592 41.219 ;
     RECT  13.104 40.693 13.512 41.267 ;
     RECT  39.984 41.123 40.512 41.267 ;
     RECT  45.6 39.493 47.736 41.269 ;
     RECT  26.448 39.731 27.336 41.365 ;
     RECT  43.872 40.837 44.232 41.365 ;
     RECT  38.112 39.923 38.136 41.411 ;
     RECT  45.6 41.269 47.88 41.411 ;
     RECT  24 40.405 25.368 41.509 ;
     RECT  26.448 41.365 27.528 41.509 ;
     RECT  13.2 41.267 13.512 41.557 ;
     RECT  20.496 39.349 20.52 41.557 ;
     RECT  51 37.811 51.312 41.557 ;
     RECT  9.168 41.171 11.4 41.651 ;
     RECT  30.96 39.877 33.048 41.651 ;
     RECT  34.8 40.499 35.88 41.651 ;
     RECT  6.912 41.171 8.112 41.747 ;
     RECT  29.4 41.075 29.832 41.747 ;
     RECT  50.4 41.557 51.312 41.749 ;
     RECT  10.8 41.651 11.4 41.795 ;
     RECT  14.976 40.117 15.432 41.795 ;
     RECT  5.28 37.573 5.304 41.797 ;
     RECT  9.168 41.651 9.192 41.843 ;
     RECT  14.976 41.795 15.384 41.891 ;
     RECT  14.976 41.891 15 41.939 ;
     RECT  43.152 41.365 44.232 41.939 ;
     RECT  50.4 41.749 51.864 42.181 ;
     RECT  4.752 41.797 5.304 42.419 ;
     RECT  24 41.509 27.528 42.467 ;
     RECT  47.184 41.411 47.88 42.467 ;
     RECT  30.96 41.651 32.376 42.611 ;
     RECT  20.496 41.557 20.76 42.661 ;
     RECT  4.752 42.419 4.776 42.709 ;
     RECT  24 42.467 27.144 42.709 ;
     RECT  29.4 41.747 29.712 42.709 ;
     RECT  3.936 42.709 4.776 42.755 ;
     RECT  41.856 42.037 41.88 42.755 ;
     RECT  56.112 40.403 57.288 42.755 ;
     RECT  43.152 41.939 43.176 42.803 ;
     RECT  48.384 42.661 48.408 42.803 ;
     RECT  10.8 41.795 11.208 42.805 ;
     RECT  13.2 41.557 13.704 42.851 ;
     RECT  50.4 42.181 52.2 42.997 ;
     RECT  56.4 42.755 57.288 43.043 ;
     RECT  3.936 42.755 3.96 43.331 ;
     RECT  7.8 41.747 8.112 43.333 ;
     RECT  23.184 42.709 27.144 43.763 ;
     RECT  55.296 43.141 55.32 43.907 ;
     RECT  10.8 42.805 11.688 43.955 ;
     RECT  31.92 42.611 32.376 43.955 ;
     RECT  47.184 42.467 47.208 43.955 ;
     RECT  50.16 42.997 52.2 43.955 ;
     RECT  15.264 42.997 15.288 44.243 ;
     RECT  7.44 43.333 8.112 44.339 ;
     RECT  10.8 43.955 10.824 44.339 ;
     RECT  29.4 42.709 30.024 44.341 ;
     RECT  36.432 43.669 36.456 44.437 ;
     RECT  20.496 42.661 21.384 44.677 ;
     RECT  29.4 44.341 30.408 44.725 ;
     RECT  34.8 41.651 35.112 44.725 ;
     RECT  36.144 44.437 36.456 44.725 ;
     RECT  23.184 43.763 24.936 44.821 ;
     RECT  22.8 44.821 24.936 44.869 ;
     RECT  29.28 44.725 30.408 44.917 ;
     RECT  31.728 44.389 31.752 44.917 ;
     RECT  44.208 41.939 44.232 44.917 ;
     RECT  13.2 42.851 13.512 44.965 ;
     RECT  18.6 41.075 18.912 44.965 ;
     RECT  20.496 44.677 21.576 44.965 ;
     RECT  34.8 44.725 36.456 44.965 ;
     RECT  13.104 44.965 13.512 45.013 ;
     RECT  18.6 44.965 21.576 45.013 ;
     RECT  26.16 43.763 27.144 45.013 ;
     RECT  29.28 44.917 32.52 45.013 ;
     RECT  34.512 44.965 36.456 45.013 ;
     RECT  40.08 41.267 40.512 45.013 ;
     RECT  44.208 44.917 44.52 45.013 ;
     RECT  45.6 41.411 45.912 45.013 ;
     RECT  48.72 44.437 48.744 45.013 ;
     RECT  50.592 43.955 52.2 45.013 ;
     RECT  56.4 43.043 56.712 45.013 ;
     RECT  40.08 45.013 42.792 45.059 ;
     RECT  40.2 45.059 42.792 45.061 ;
     RECT  44.208 45.013 45.912 45.061 ;
     RECT  12.624 45.013 14.28 45.109 ;
     RECT  18.288 45.013 21.576 45.109 ;
     RECT  22.608 44.869 24.936 45.109 ;
     RECT  26.064 45.013 32.904 45.157 ;
     RECT  34.128 45.013 36.552 45.157 ;
     RECT  16.08 45.013 17.064 45.301 ;
     RECT  18.288 45.109 24.936 45.301 ;
     RECT  26.064 45.157 36.552 45.301 ;
     RECT  16.08 45.301 17.256 45.349 ;
     RECT  18.288 45.301 36.552 45.349 ;
     RECT  2.4 34.355 2.712 45.369 ;
     RECT  7.8 44.339 8.112 45.369 ;
     RECT  54.96 45.013 56.712 45.369 ;
     RECT  61.8 36.947 62.112 45.369 ;
     RECT  67.2 35.363 67.512 45.369 ;
     RECT  72.6 29.315 72.912 45.369 ;
     RECT  78 31.187 78.312 45.369 ;
     RECT  83.4 1.811 83.712 45.369 ;
     RECT  88.8 1.811 89.112 45.369 ;
     RECT  2.4 45.369 2.52 45.383 ;
     RECT  7.8 45.369 7.92 45.383 ;
     RECT  40.2 45.061 45.912 45.383 ;
     RECT  54.96 45.369 56.52 45.383 ;
     RECT  61.8 45.369 61.92 45.383 ;
     RECT  67.2 45.369 67.32 45.383 ;
     RECT  72.6 45.369 72.72 45.383 ;
     RECT  78 45.369 78.12 45.383 ;
     RECT  83.4 45.369 83.52 45.383 ;
     RECT  88.8 45.369 88.92 45.383 ;
     RECT  40.848 45.383 45.912 45.445 ;
     RECT  46.896 45.013 52.2 45.445 ;
     RECT  12.624 45.109 14.472 45.493 ;
     RECT  16.08 45.349 36.648 45.541 ;
     RECT  12.624 45.493 14.76 45.637 ;
     RECT  15.888 45.541 36.648 45.637 ;
     RECT  12.624 45.637 36.648 45.829 ;
     RECT  11.376 45.301 11.4 45.925 ;
     RECT  12.432 45.829 36.648 45.925 ;
     RECT  11.376 45.925 36.648 47.504 ;
     RECT  40.848 45.445 52.2 47.504 ;
     RECT  54.96 45.383 55.848 47.504 ;
  END
END ot_hgi_coll_argmax_m_tp192
END LIBRARY
